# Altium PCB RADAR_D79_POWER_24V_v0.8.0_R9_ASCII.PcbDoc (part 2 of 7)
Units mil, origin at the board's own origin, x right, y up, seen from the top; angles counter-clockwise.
Board outline 3110.24 x 3110.24 mil, 8 copper layers (Top Layer, GND1, SIG1, PWR1, PWR2, SIG2, GND2, Bottom Layer), stack 55.2 mil thick; 304 components, 269 nets, 1408 pads, 1366 vias.

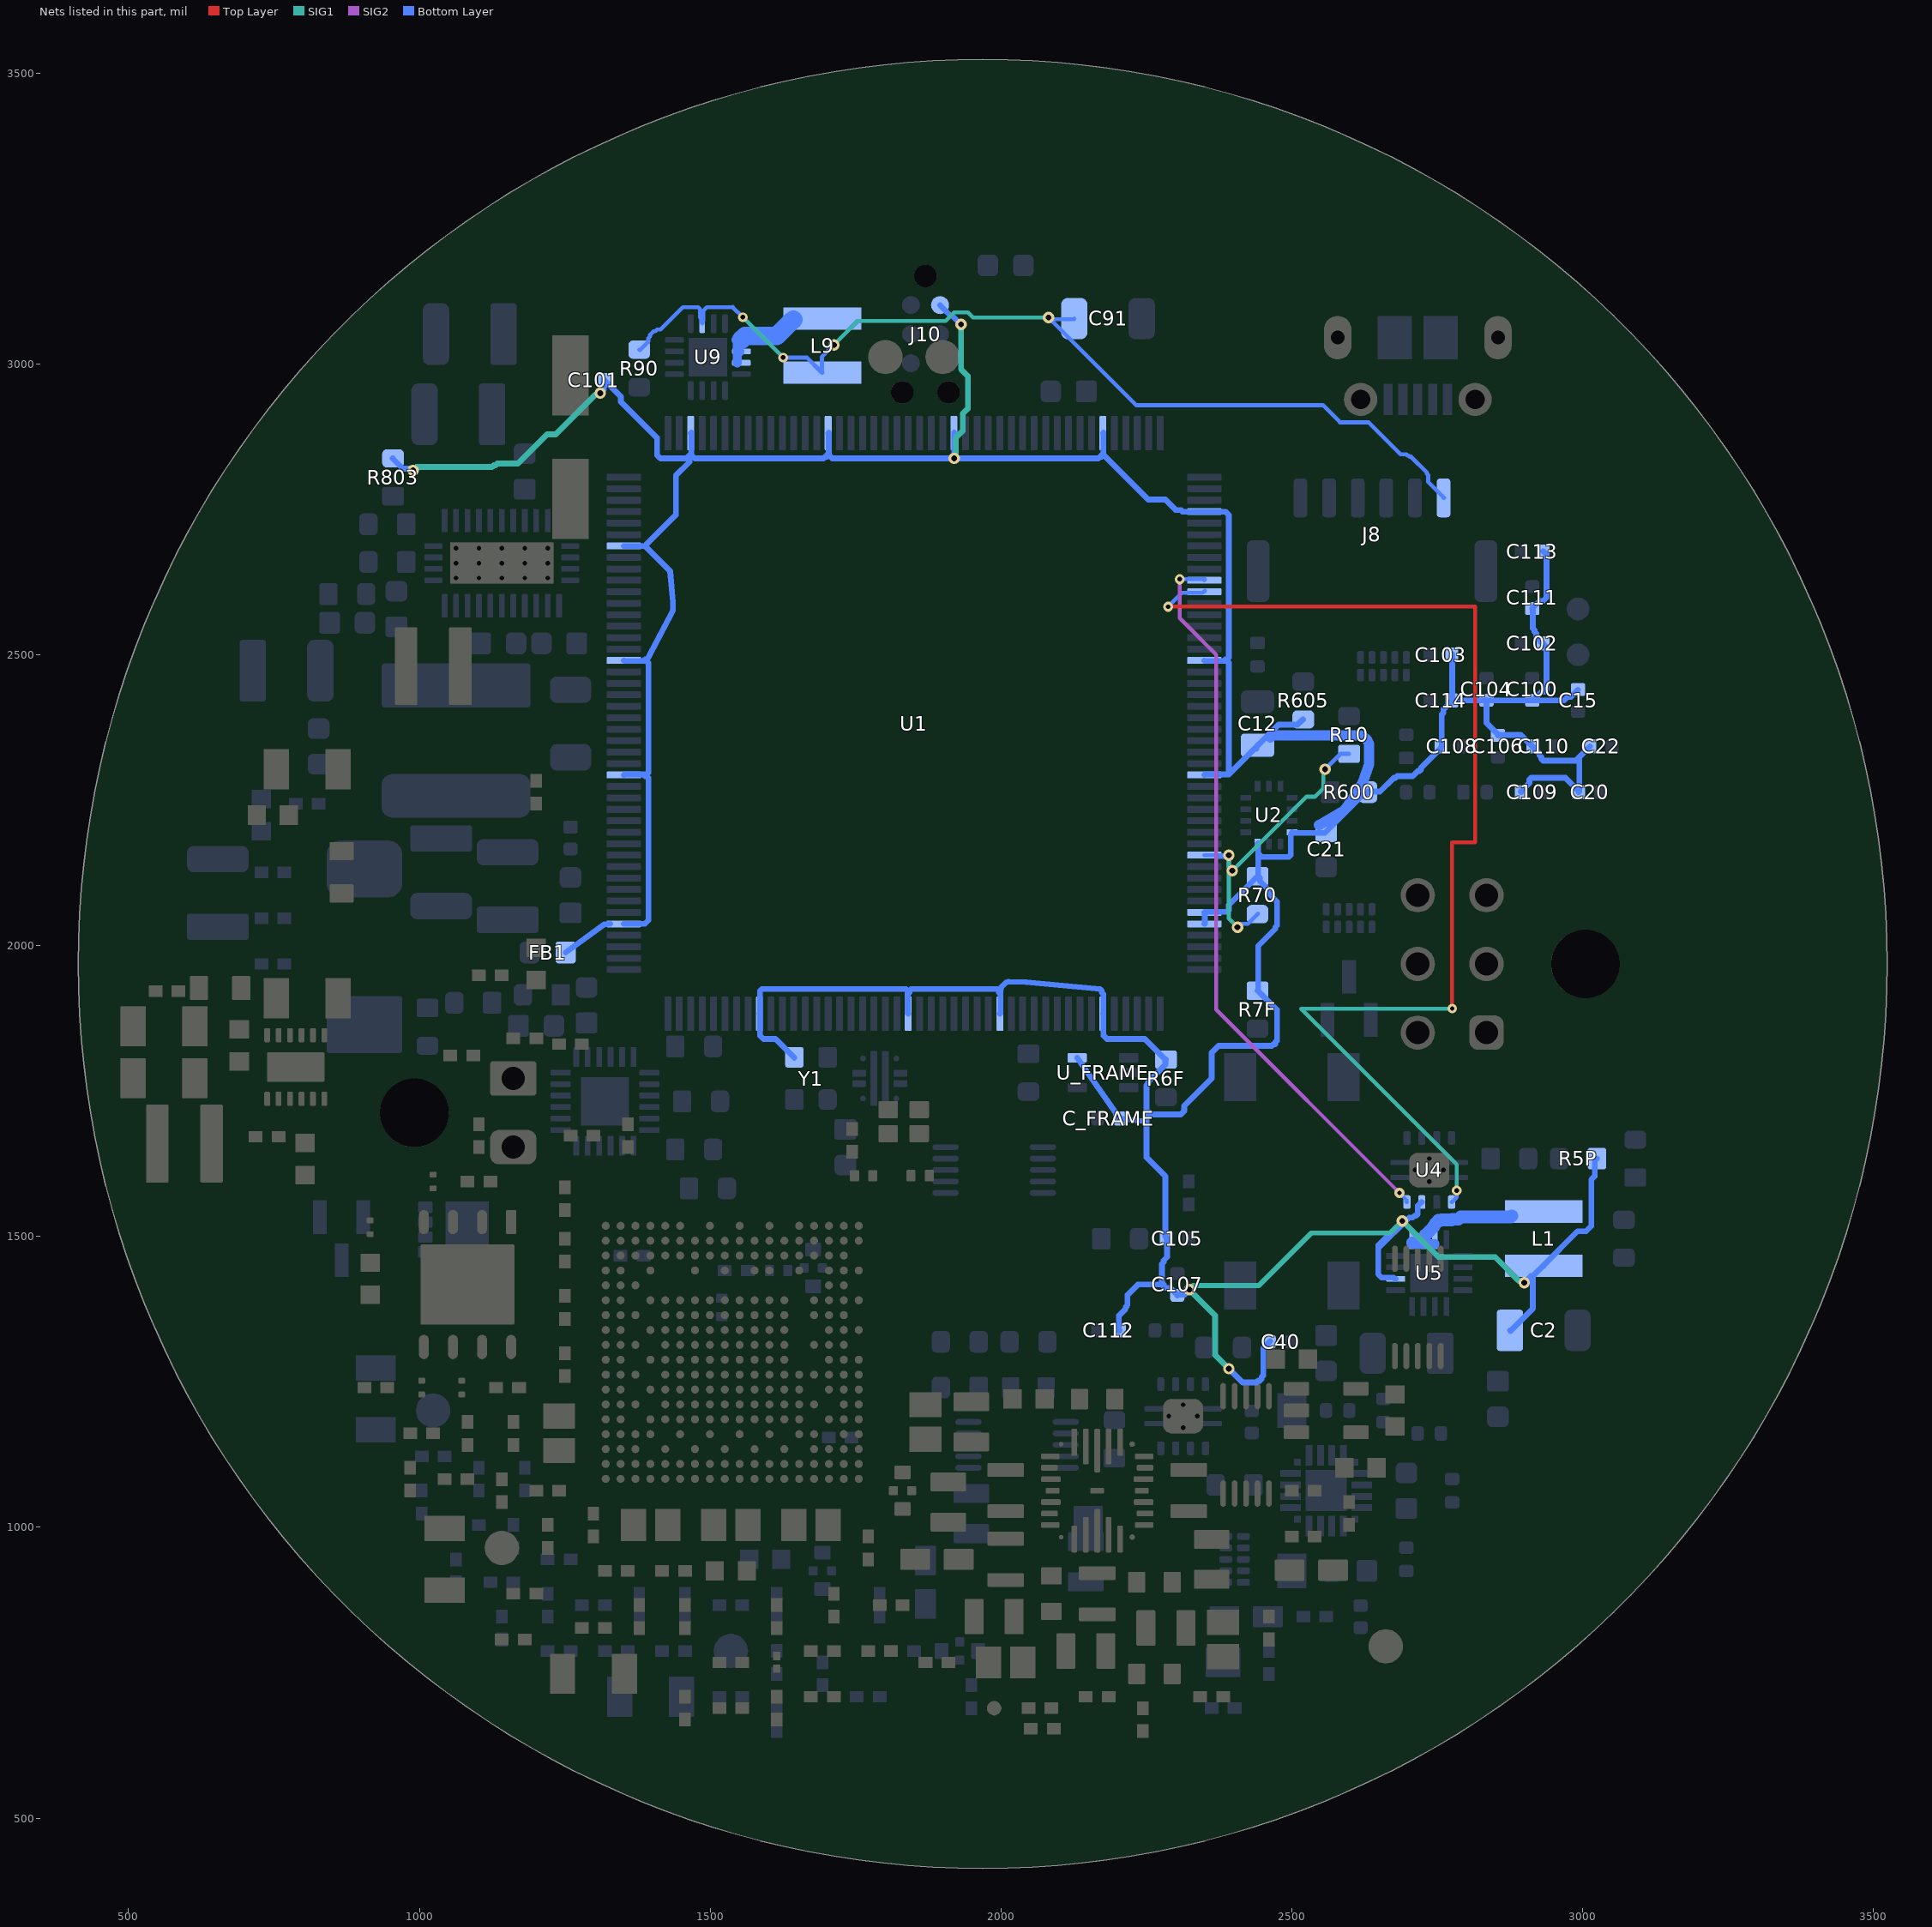
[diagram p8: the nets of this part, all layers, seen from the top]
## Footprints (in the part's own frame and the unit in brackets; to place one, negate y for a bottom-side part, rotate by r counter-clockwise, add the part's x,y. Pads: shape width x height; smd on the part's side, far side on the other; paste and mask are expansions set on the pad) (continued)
RXV0028A-MFG [mm]
  round 0.195 smd paste+0 mask+0: 1(-1.573,2.03) 9(-1.573,-2.03)
  rrect40% 0.8x0.25 smd paste+0 mask+0: 2(-2.05,1.5) 8(-2.05,-1.5) 16(2.05,-1.5) 22(2.05,1.5)
  rrect40% 0.725x0.25 smd paste+0 mask+0: 3(-2.087,1) 7(-2.087,-1) 17(2.087,-1) 21(2.087,1)
  rrect40% 0.85x0.25 smd paste+0 mask+0: 4(-2.025,0.5) 6(-2.025,-0.5) 18(2.025,-0.5) 20(2.025,0.5)
  rrect40% 0.6x0.25 smd paste+0 mask+0: 5(-1.95,0) 5-19(0,0) 19(1.95,0)
  rrect40% 0.25x1.175 smd paste+0 mask+0: 10(-1,-2.113) 14(1,-2.113) 24(1,2.113) 28(-1,2.113)
  rrect40% 0.25x1.55 smd paste-1000 mask+0: 11(-0.5,-1.925) 13(0.5,-1.925) 25(0.5,1.925) 27(-0.5,1.925)
  rrect40% 0.25x1.9 smd paste-1000 mask+0: 12(0,-1.75) 26(0,1.75)
  round 0.243 smd paste+0 mask+0: 15(1.53,-2.03) 23(1.53,2.03)
  silkscreen extent -2.58,-2.78 2.58,2.78
SM_RADIAL_6.3BMM [mm] "Nichicon 6.3x7.7"
  rect 3.5x1.6 smd: 1(-2.7,0) 2(2.7,0)
  silkscreen extent -0.79,-0.88 0.79,0.88
SOT-23 [mm] "JEDEC TO-236 AB, three-pad SOT-23"
  rect 1.475x0.6 smd: 1(-0.937,-0.95) 2(-0.937,0.95) 3(0.937,0)
  silkscreen extent -1.75,-1.33 1.76,1.33
TagConnect_TC2030_NL [mil]
  round 31 smd: 1(-50,-25) 2(-50,25) 3(0,-25) 4(0,25) 5(50,-25) 6(50,25)
  round 39 hole 39: Un1(-100,0) Un2(100,40) Un3(100,-40)
  silkscreen extent -123,-63 123,63
TestPoint_Pad_D1.0mm [mm]
  round 1 smd: 1(0,0)
  silkscreen extent -0.68,-0.68 0.68,0.68
TestPoint_Pad_D1.5mm [mm]
  round 1.5 smd paste-1 mask+0.06: 1(0,0)
  silkscreen extent -0.83,-0.83 0.83,0.83
Texas_DRB0008A [mm]
  rrect50% 0.6x0.31 smd: 1(-1.4,0.975) 2(-1.4,0.325) 3(-1.4,-0.325) 4(-1.4,-0.975) 5(1.4,-0.975) 6(1.4,-0.325) 7(1.4,0.325) 8(1.4,0.975)
  round 0.5 hole 0.2: 9(-0.5,0) 9(0,-0.625) 9(0,0.625) 9(0.5,0)
  rrect50% 0.23x1.025 smd: 9(-0.325,-1.188) 9(-0.325,1.188) 9(0.325,-1.188) 9(0.325,1.188)
  rrect50% 1.5x1.75 smd: 9(0,0)
  rrect50% 1.5x1.75 smd far side: 9(0,0)
  rrect50% 0.23x0.725 on Bottom Paste: Un1(-0.325,1.337) Un2(-0.325,-1.337) Un4(0.325,1.337) Un5(0.325,-1.337)
  rrect50% 1.34x1.55 on Bottom Paste: Un3(0,0)
  silkscreen extent -1.78,-1.78 1.78,1.78
Texas_RGE0024C_VQFN-24-1EP_4x4mm_P0.5mm_EP2.1x2.1mm [mm]
  rrect25% 0.875x0.25 smd mask+0: 1(-1.937,1.25) 2(-1.937,0.75) 3(-1.937,0.25) 4(-1.937,-0.25) 5(-1.937,-0.75) 6(-1.937,-1.25) 13(1.937,-1.25) 14(1.937,-0.75) 15(1.937,-0.25) 16(1.937,0.25) 17(1.937,0.75) 18(1.937,1.25)
  rrect25% 0.25x0.875 smd mask+0: 7(-1.25,-1.937) 8(-0.75,-1.937) 9(-0.25,-1.937) 10(0.25,-1.937) 11(0.75,-1.937) 12(1.25,-1.937) 19(1.25,1.937) 20(0.75,1.937) 21(0.25,1.937) 22(-0.25,1.937) 23(-0.75,1.937) 24(-1.25,1.937)
  rect 2.1x2.1 smd paste-2.1 mask+0: 25(0,0)
  rrect50% 0.85x0.85 on Bottom Paste mask+0: Un1(-0.525,0.525) Un2(-0.525,-0.525) Un3(0.525,0.525) Un4(0.525,-0.525)
  silkscreen extent -2.45,-2.45 2.45,2.45
Texas_RNP0030B_WQFN-30-1EP_4x6mm_P0.5mm_EP1.8x4.5mm_ThermalVias [mm]
  rrect25% 1.025x0.25 smd mask+0: 1(-1.863,2.5) 2(-1.863,2) 3(-1.863,1.5) 4(-1.863,1) 5(-1.863,0.5) 6(-1.863,0) 7(-1.863,-0.5) 8(-1.863,-1) 9(-1.863,-1.5) 10(-1.863,-2) 11(-1.863,-2.5) 16(1.863,-2.5) 17(1.863,-2) 18(1.863,-1.5) 19(1.863,-1) 20(1.863,-0.5) 21(1.863,0) 22(1.863,0.5) 23(1.863,1) 24(1.863,1.5) 25(1.863,2) 26(1.863,2.5)
  rrect25% 0.25x0.775 smd mask+0: 12(-0.75,-2.987) 13(-0.25,-2.987) 14(0.25,-2.987) 15(0.75,-2.987) 27(0.75,2.987) 28(0.25,2.987) 29(-0.25,2.987) 30(-0.75,2.987)
  round 0.5 hole 0.2 paste+0 mask+0: 31(-0.65,-2) 31(-0.65,-1) 31(-0.65,0) 31(-0.65,1) 31(-0.65,2) 31(0,-2) 31(0,-1) 31(0,0) 31(0,1) 31(0,2) 31(0.65,-2) 31(0.65,-1) 31(0.65,0) 31(0.65,1) 31(0.65,2)
  rect 1.8x4.5 smd paste-4.5 mask+0: 31(0,0)
  rect 1.8x4.5 smd far side paste-4.5 mask+0: 31(0,0)
  rrect50% 0.78x0.97 on Bottom Paste mask+0: Un1(-0.45,1.68) Un2(-0.45,0.56) Un3(-0.45,-0.56) Un4(-0.45,-1.68) Un5(0.45,1.68) Un6(0.45,0.56) Un7(0.45,-0.56) Un8(0.45,-1.68)
  silkscreen extent -2.46,-3.45 2.45,3.45
TFM201610ALMA [mm] "TDK"
  rrect17% 0.6x1.6 smd: 1(-0.9,0) 2(0.9,0)
  silkscreen extent -0.49,-0.88 0.49,0.88
TP_25MIL-SMT [mil]
  round 25 smd paste-25 mask+0: 1(0,0)
  silkscreen extent -27,-27 27,27
TPS259470A_RPW0010A_VQFN-HR-10_2x2mm_P0.475mm [mm]
  round 0.25 smd: 1(-0.725,0.875) 4(-0.725,-0.875) 7(0.725,-0.875) 10(0.725,0.875)
  rrect17% 0.6x0.3 smd: 2(-0.9,0.225) 3(-0.9,-0.225) 9(0.9,0.225)
  rrect17% 0.3x2.4 smd: 5(-0.25,0) 6(0.25,0)
  rrect50% 0.6x0.3 smd: 8(0.9,-0.225)
  rrect17% 0.3x1.05 on Bottom Paste: Un1(-0.25,0.675) Un2(-0.25,-0.675) Un3(0.25,0.675) Un4(0.25,-0.675)
  silkscreen extent -1.28,-1.28 1.28,1.28
USON-10_2.5x1.0mm_P0.5mm [mm]
  rrect50% 0.55x0.3 smd: 1(-0.385,1) 2(-0.385,0.5) 3(-0.385,0) 4(-0.385,-0.5) 5(-0.385,-1) 6(0.385,-1) 7(0.385,-0.5) 8(0.385,0) 9(0.385,0.5) 10(0.385,1)
  silkscreen extent -1.33,-1.23 1.33,1.23
VPP_SERVICE_SMT_D1p5_P2p5 [mm]
  round 1.5 smd paste-1 mask+0.06: 1(-1.25,0) 2(1.25,0)
  silkscreen extent -2.08,-0.83 2.08,0.83
VQFN-16-1EP_3x3mm_P0.5mm_EP1.68x1.68mm#1 [mm]
  rrect25% 0.825x0.25 smd: 1(-1.462,0.75) 2(-1.462,0.25) 3(-1.462,-0.25) 4(-1.462,-0.75) 9(1.462,-0.75) 10(1.462,-0.25) 11(1.462,0.25) 12(1.462,0.75)
  rrect25% 0.25x0.825 smd: 5(-0.75,-1.462) 6(-0.25,-1.462) 7(0.25,-1.462) 8(0.75,-1.462) 13(0.75,1.462) 14(0.25,1.462) 15(-0.25,1.462) 16(-0.75,1.462)
  rect 1.68x1.68 smd: 17(0,0)
  rrect25% 0.68x0.68 on Bottom Paste: Un1(-0.42,0.42) Un2(-0.42,-0.42) Un3(0.42,0.42) Un4(0.42,-0.42)
  silkscreen extent -1.95,-1.95 1.95,1.95
VQFN-16-1EP_3x3mm_P0.5mm_EP1.68x1.68mm#2 [mm]
  rrect50% 0.825x0.25 smd: 1(-1.462,0.75) 2(-1.462,0.25) 3(-1.462,-0.25) 4(-1.462,-0.75) 9(1.462,-0.75) 10(1.462,-0.25) 11(1.462,0.25) 12(1.462,0.75)
  rrect50% 0.25x0.825 smd: 5(-0.75,-1.462) 6(-0.25,-1.462) 7(0.25,-1.462) 8(0.75,-1.462) 13(0.75,1.462) 14(0.25,1.462) 15(-0.25,1.462) 16(-0.75,1.462)
  rect 1.68x1.68 smd: 17(0,0)
  rrect50% 0.68x0.68 on Bottom Paste: Un1(-0.42,0.42) Un2(-0.42,-0.42) Un3(0.42,0.42) Un4(0.42,-0.42)
  silkscreen extent -1.95,-1.95 1.95,1.95
VSON-8_3.3x3.3mm_P0.65mm_NexFET [mm]
  rrect25% 0.63x0.495 smd mask+0: 1(-1.44,0.975) 2(-1.44,0.325) 3(-1.44,-0.325) 4(-1.44,-0.975)
  rect 1.9x2.45 smd paste-2.45 mask+0: 5(0.385,0)
  rect 0.57x0.738 on Bottom Paste mask+0: Un1(-0.09,0.61) Un2(-0.09,-0.61) Un3(0.86,0.61) Un4(0.86,-0.61)
  rrect50% 0.63x0.5 on Bottom Paste mask+0: Un5(1.44,0.972) Un6(1.44,0.33) Un7(1.44,-0.33) Un8(1.44,-0.972)
  silkscreen extent -1.84,-1.73 1.83,1.73

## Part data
C1 C2 C3 C4 C6D C6I C7D C10 C11 C12 C13 C14 C15 C20 C21 C22 C40 C90 C91 C92 C93 C100 C101 C102 C103 C104 C105 C106 C107 C108 C109 C110 C111 C112 C113 C114 C115 C800 C801 C802 C803 C804 C805 C806 C807 C808 C809 C_USB_1U C_USB_4U7 C_USB_100N: library part C
D1: library part D_TVS
D3 D8 D_USB: library part TPD4E05U06DQAR
D4: library part ESD2CANFD24DBZRQ1
FB1: library part L_Ferrite
J1: library part Conn_01x02
J6 J8 J10: library part Conn_01x06
JUSB1: library part CMP-0055293-1, "Connector, Receptacle, Micro-USB Type B, R/A, Bottom Mount SMT"
L1 L8 L9: library part L
Q6: library part CSD19537Q3
Q7: library part BSS138
R1 R2 R5P R6F R7F R10 R40 R41 R42 R61 R62 R63 R70 R71 R72 R73 R90 R600 R601 R602 R603 R604 R605 R800 R801 R802 R803 R804 R805 R806 R_USB_CTS R_USB_RESET R_USB_VBUS_H R_USB_VBUS_L R_USB_WAKE: library part R
RAD_C1 RAD_C10 RAD_C60 RAD_C145: library part CMP-0007136-5, "CAP, CERM, 1 uF, 16 V, +/- 10%, X7R, AEC-Q200 Grade 1, 0603"
RAD_C2: library part CMP-0006325-2, "CAP, CERM, 0.1 uF, 50 V, +/- 10%, X7R, AEC-Q200 Grade 1, 0402"
RAD_C3 RAD_C123 RAD_C137 RAD_C146 RAD_C149: library part CMP-0007134-5, "CAP, CERM, 2.2 uF, 6.3 V, +/- 10%, X7R, AEC-Q200 Grade 1, 0603"
RAD_C5 RAD_C21 RAD_C22 RAD_C92 RAD_C96 RAD_C107 RAD_C111 RAD_C113 RAD_C115 RAD_C117 RAD_C138 RAD_C139 RAD_C140 RAD_C141 RAD_C142 RAD_C163 RAD_C164 RAD_C165 RAD_C168 RAD_C170 RAD_C172 RAD_C174 RAD_C175 RAD_C176 RAD_C177 RAD_C199: library part CMP-0078265-1, "CAP, CERM, 0.22 µF, 16 V,+/- 10%, X7R, AEC-Q200 Grade 1, 0402"
RAD_C6 RAD_C8 RAD_C124 RAD_C144 RAD_C153: library part CMP-0091520-1, "Cap Ceramic Multilayer 4.7uF 6.3V DC 10% SMD Paper T/R"
RAD_C9 RAD_C58 RAD_C179 RAD_C181: library part CMP-0088247-2, "3 Terminals Low ESL Chip Multilayer Ceramic Capacitors for Automotive"
RAD_C14 RAD_C17 RAD_C19 RAD_C81: library part CMP-0006350-2, "CAP, CERM, 0.1 uF, 10 V, +/- 10%, X7R, AEC-Q200 Grade 1, 0402"
RAD_C15 RAD_C31 RAD_C110 RAD_C112 RAD_C114 RAD_C116 RAD_C119: library part CMP-0008017-2, "CAP, CERM, 10 uF, 10 V, +/- 10%, X7R, 0805"
RAD_C23 RAD_C25 RAD_C26 RAD_C29: library part CMP-0008811-3, "CAP, CERM, 22 uF, 10 V, +/- 10%, X7R, AEC-Q200 Grade 1, 1206"
RAD_C99: library part CMP-0012608-3, "CAP, Polymer Hybrid, 68 uF, 35 V, +/- 20%, 35 ohm, 6.3x7.7 SMD"
RAD_C100 RAD_C101: library part CMP-0008702-2, "CAP, CERM, 4.7 uF, 50 V, +/- 10%, X7R, 1206"
RAD_C102 RAD_C103: library part CMP-0088425-1, "1µF ±10% 6.3V Ceramic Capacitor X7R 0402 (1005 Metric)"
RAD_C104 RAD_C126: library part CMP-0007104-4, "CAP, CERM, 0.1 uF, 50 V, +/- 10%, X8R, AEC-Q200 Grade 0, 0603"
RAD_C105 RAD_C150 RAD_C200: library part CMP-0006351-2, "CAP, CERM, 0.1 uF, 16 V, +/- 10%, X7R, 0402"
RAD_C106 RAD_C108: library part CMP-0048219-1, "Ceramic Capacitor for Automotive 3.9pF ±0.1pF 50VDC C0G 0402 Paper T/R"
RAD_C118 RAD_C173: library part CMP-0090082-1, "Cap Ceramic 4.7uF 50V X7R 10% Pad SMD 0805 +125°C Automotive T/R"
RAD_C125 RAD_C129 RAD_C130 RAD_C132 RAD_C134 RAD_C143 RAD_C201 RAD_C202: library part CMP-0860846-1, "CAP, CERM, 22 µF, 6.3 V,+/- 20%, X7T, AEC-Q200 Grade 1, 0805"
RAD_C180: library part CMP-0006330-2, "CAP, CERM, 0.047 uF, 50 V, +/- 10%, X7R, AEC-Q200 Grade 1, 0402"
RAD_C195: library part CMP-0007094-5, "CAP, CERM, 0.22 uF, 50 V, +/- 10%, X7R, AEC-Q200 Grade 1, 0603"
RAD_L1: library part CMP-0081093-1, "Inductor, Shielded, Metal Composite, 1.5 µH, 2.3 A, 0.11 ohm, AEC-Q200 Grade 0, SMD"
RAD_L2 RAD_L8 RAD_L9: library part CMP-0091696-1, "240nH Shielded Thin Film Inductor 5A 23mOhm Max 0806 (2016 Metric)"
RAD_L5: library part CMP-0089502-2, "Power Inductor (SMD), 4.7 µH, 5.1 A, Shielded, 4.5 A, XAL40xx Series, 4mm x 4mm x 3.1mm"
RAD_L6: library part CMP-0120010-1, "Ultra-Low Loss Shielded Power Inductors 2.2µH ±20% 7.8A 22.1mOhms"
RAD_NT1: library part CMP-0078142-4, "Single point connection between nets."
RAD_NT2 RAD_NT3 RAD_NT4: library part CMP-0078142-3, "Single point connection between nets."
RAD_R1 RAD_R13 RAD_R14 RAD_R17 RAD_R27 RAD_R29 RAD_R33 RAD_R35 RAD_R37 RAD_R57 RAD_R58 RAD_R59 RAD_R62 RAD_R63 RAD_R71 RAD_R75 RAD_R76 RAD_R128 RAD_R129 RAD_R186 RAD_R190 RAD_R291: library part CMP-0026992-3, "RES, 0, 5%, 0.1 W, AEC-Q200 Grade 0, 0402"
RAD_R2: library part CMP-0026555-2, "RES, 7.50 k, 1%, 0.063 W, AEC-Q200 Grade 0, 0402"
RAD_R7 RAD_R9 RAD_R41 RAD_R43 RAD_R49 RAD_R106 RAD_R125 RAD_R264 RAD_R299 RAD_R301 RAD_R305 RAD_R309 RAD_R310 RAD_R409: library part CMP-0025958-3, "RES, 10.0 k, 1%, 0.063 W, AEC-Q200 Grade 0, 0402"
RAD_R26 RAD_R32 RAD_R47 RAD_R56 RAD_R65 RAD_R66 RAD_R348 RAD_R352: library part CMP-0025964-3, "RES, 10.2, 1%, 0.063 W, AEC-Q200 Grade 0, 0402"
RAD_R30 RAD_R60 RAD_R64 RAD_R346: library part CMP-0017253-2, "RES, 0.001, 1%, 1 W, AEC-Q200 Grade 0, 1206"
RAD_R38: library part CMP-0026395-2, "RES, 47.5 k, 1%, 0.063 W, AEC-Q200 Grade 0, 0402"
RAD_R39 RAD_R40 RAD_R42 RAD_R44 RAD_R45: library part CMP-0089575-2, "Res Thick Film 0201 33.2 Ohm 1% 0.05W(1/20W) ±200ppm/C Pad SMD Automotive T/R"
RAD_R73 RAD_R104 RAD_R111 RAD_R200: library part CMP-0091690-1, "RES 0 OHM JUMPER 1/4W 0603"
RAD_R99: library part CMP-0026071-3, "RES, 1.00 k, 1%, 0.063 W, AEC-Q200 Grade 0, 0402"
RAD_R116: library part CMP-0081856-1, "RES, 0, 0%, 0.2 W, AEC-Q200 Grade 0, 0402"
RAD_R193 RAD_R386: library part CMP-0026299-2, "RES, 33.2, 1%, 0.063 W, AEC-Q200 Grade 0, 0402"
RAD_R218: library part CMP-0027008-4, "RES, 0, 5%, 0.05 W, 0201"
RAD_R276 RAD_R277: library part CMP-0026244-2, "RES, 2.94 k, 1%, 0.063 W, AEC-Q200 Grade 0, 0402"
RAD_R292: library part CMP-0026890-5, "RES, 2.2 k, 5%, 0.063 W, AEC-Q200 Grade 0, 0402"
RAD_R300 RAD_R311: library part CMP-0026557-2, "RES, 7.87 k, 1%, 0.063 W, AEC-Q200 Grade 0, 0402"
RAD_R302 RAD_R307 RAD_R313: library part CMP-0026574-2, "RES, 82.5 k, 1%, 0.063 W, AEC-Q200 Grade 0, 0402"
RAD_TP8: library part CMP-0078143-3, "TEST POINT.  No entry in BOM."
RAD_U1: library part CMP-0091081-1, "3.3V Uniform Sector Dual and Quad Serial Flash SPI 64Mbit 2.7-3.6V WSON8"
RAD_U2: library part CMP-0088353-1, "3.5-V to 36-V, 1.5-A, and 2.5-A Automotive Step-down Voltage Converter"
RAD_U8: library part CMP-0091078-3, "Three Buck Converters and 5-V Boost for AWR and IWR Radar Sensors"
RAD_U9 RAD_U11 RAD_U12 RAD_U22: library part CMP-0037979-1, "High-Side Measurement, Bi-Directional Current / Power Monitor with I2C Interface, 2.7 to 5.5 V, -40 to 125 degC, 10-pin SOP (DGS10), Green (RoHS & no Sb/Br)"
RAD_U27: library part CMP-0092338-1, "Linear Voltage Regulator IC Positive Fixed Output 300mA SOT-23-5"
RAD_U29: library part CMP-0122079-4, "Single-Chip 76- and 81-GHz FMCW Radar Sensor"
RAD_Y3: library part CMP-0001431-1, "50 MHz ±15ppm Crystal 8pF 50 Ohms 4-SMD, No Lead"
SW1: library part SW_Push
TP1 TP2: library part TestPoint
U1: library part STM32H753IITx
U2: library part ICM-42688-P
U4: library part TCAN3404DRBRQ1
U5: library part TPS62132RGTR
U6: library part TPS26630RGER
U7: library part TPS259470ARPWR
U8: library part LM76005RNPR
U9: library part TPS62133RGTR
U_FRAME: library part SN74LVC1G17DCKR
Y1: library part ECS-2520S33-250-FN-TR

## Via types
v1: diameter 13.77, hole 5.9, Top Layer to GND1, tented both sides, 513 vias
v2: diameter 19.68, hole 9.84, Top Layer to Bottom Layer, tented both sides, 196 vias
v3: diameter 16.54, hole 7.87, Top Layer to Bottom Layer, tented both sides, 129 vias
v4: diameter 13.77, hole 5.9, Top Layer to GND1, tented top, 104 vias
v5: diameter 13.78, hole 5.91, Top Layer to GND1, tented both sides, 83 vias
v6: diameter 17.32, hole 7.87, Top Layer to Bottom Layer, tented both sides, 69 vias
v7: diameter 13.78, hole 5.91, GND2 to Bottom Layer, tented both sides, 68 vias
v8: diameter 13.78, hole 5.91, Top Layer to GND1, tented bottom, 55 vias
v9: diameter 13.78, hole 5.91, GND2 to Bottom Layer, tented top, 43 vias
v10: diameter 22.05, hole 11.81, Top Layer to Bottom Layer, tented both sides, 23 vias
v11: diameter 16.54, hole 7.87, GND2 to Bottom Layer, tented both sides, 22 vias
v12: diameter 16.54, hole 7.87, Top Layer to Bottom Layer, 14 vias
v13: diameter 22.83, hole 11.81, Top Layer to Bottom Layer, tented both sides, 11 vias
v14: diameter 18.11, hole 9.06, Top Layer to Bottom Layer, tented both sides, 8 vias
v15: diameter 19.68, hole 7.87, Top Layer to Bottom Layer, 3 vias
v16: diameter 17.32, hole 8.66, Top Layer to Bottom Layer, tented both sides, 3 vias
v17: diameter 20.47, hole 9.84, Top Layer to Bottom Layer, tented both sides, 3 vias
v18: diameter 17.72, hole 9.84, Top Layer to Bottom Layer, tented both sides, 2 vias
v19: diameter 22.05, hole 11.02, Top Layer to Bottom Layer, tented both sides, 2 vias
v20: diameter 19.68, hole 11.81, Top Layer to Bottom Layer, tented both sides, 2 vias
v21: diameter 19.68, hole 9.84, SIG1 to Bottom Layer, tented both sides, 2 vias
v22: diameter 16.54, hole 7.87, SIG1 to SIG2, tented both sides, 2 vias
v23: diameter 16.54, hole 7.87, Top Layer to SIG1, 2 vias
v24: diameter 13.78, hole 5.91, Top Layer to GND1, 2 vias
v25: diameter 18, hole 9.84, Top Layer to Bottom Layer, tented both sides, 1 vias
v26: diameter 19.68, hole 9.84, GND2 to Bottom Layer, tented both sides, 1 vias
v27: diameter 17.32, hole 7.87, SIG1 to Bottom Layer, tented both sides, 1 vias
v28: diameter 19.68, hole 9.84, SIG2 to Bottom Layer, tented both sides, 1 vias
v29: diameter 16.54, hole 7.87, PWR2 to GND1, tented both sides, 1 vias

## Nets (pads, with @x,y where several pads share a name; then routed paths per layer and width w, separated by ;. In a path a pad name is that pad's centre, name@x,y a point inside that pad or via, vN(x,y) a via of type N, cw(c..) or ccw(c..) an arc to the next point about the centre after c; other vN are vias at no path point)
3V3: C2.1 C12.1 C15.1 C20.1 C21.1 C22.1 C40.1 C100.1 C101.1 C102.1 C103.1 C104.1 C105.1 C106.1 C107.1 C108.1 C109.1 C110.1 C111.1 C112.1 C113.1 C114.1 C_FRAME.1 FB1.1 J10.1 L1.2 R5P.2 R6F.2 R7F.2 R70.2 R600.1 R605.1 R803.2 U1.6 U1.15 U1.23 U1.36 U1.49 U1.62 U1.72 U1.82 U1.91 U1.103 U1.114 U1.127 U1.136 U1.149 U1.159 U1.171 U1.172 U2.5 U2.8 U4.3 U5.14 U_FRAME.5 Y1.4 | length 10676.6
  SIG1 w8.66: v2(2323.82,1408.46) 2324.8,1409.45 2330.71,1415.35 2442.91,1415.35 2533.46,1505.91 2669.29,1505.91 2690.94,1527.56 v2(2689.96,1526.57)
  SIG1 w9.84: v2(989.17,2816.93) 995.08,2822.83 1125,2822.83 1127.95,2825.79 1130.91,2825.79 1133.86,2828.74 1169.29,2828.74 1219.49,2878.94 1234.25,2878.94 1302.17,2946.85 1308.07,2946.85 v2(1311.02,2949.8) ; v2(1919.29,2837.6) 1922.24,2840.55 1922.24,2873.03 1934.06,2884.84 1934.06,2914.37 1942.91,2923.23 1942.91,2979.33 1931.1,2991.14 v2(1931.1,3067.91) ; v2(2323.82,1408.46) 2368.11,1364.17 2368.11,1296.26 v2(2391.73,1272.64) ; v2(2689.96,1526.57) 2751.97,1464.57 2849.41,1464.57 2890.75,1423.23 2896.65,1423.23 v2(2899.61,1420.28)
  Bottom Layer w9.84: R803.2@954.72,2837.6 953.74,2837.6 971.46,2819.88 986.22,2819.88 v2(989.17,2816.93) ; FB1.1@1251.48,1988.19 1317.91,2036.42 U1.49@1328.15,2037.4 ; v2(1311.02,2949.8) 1316.93,2955.71 C101.1@1316.93,2973.43 ; C101.1@1318.11,2972.44 C101.1@1316.93,2973.43 ; U1.49@1351.38,2037.4 1352.36,2037.4 1387.8,2037.4 1393.7,2043.31 1393.7,2288.39 1390.75,2291.34 1387.8,2291.34 1384.84,2294.29 U1.62@1352.36,2294.29 ; U1.62@1351.38,2293.31 U1.62@1352.36,2294.29 ; U1.72@1351.38,2490.16 U1.72@1352.36,2489.17 ; U1.82@1351.38,2687.01 1352.36,2687.01 1387.8,2687.01 ; U1.91@1466.54,2880.91 U1.91@1467.52,2881.89 ; U1.36@1584.65,1882.87 U1.36@1585.63,1883.86 ; Y1.4@1644.68,1808.07 1644.68,1807.09 1612.2,1839.57 1591.54,1839.57 1585.63,1845.47 U1.36@1585.63,1883.86 ; U1.103@1702.76,2880.91 U1.103@1703.74,2881.89 ; U1.23@1840.55,1882.87 U1.23@1839.57,1883.86 ; J10.1@1895.08,3101.18 1895.67,3100.39 1913.39,3082.68 1916.34,3082.68 v2(1931.1,3067.91) ; v2(1919.29,2837.6) U1.114@1919.29,2881.89 ; U1.114@1919.29,2880.91 U1.114@1919.29,2881.89 ; U1.15@1998.03,1882.87 U1.15@1999.02,1883.86 ; U_FRAME.5@2130.91,1807.09 C_FRAME.1@2203.94,1702.76 2250,1697.83 ; U1.6@2175.2,1882.87 U1.6@2176.18,1883.86 ; U1.127@2175.2,2880.91 U1.127@2176.18,2881.89 ; C112.1@2203.94,1338.58 2202.76,1337.6 2202.76,1364.17 2214.57,1375.98 2214.57,1378.94 2217.52,1381.89 2217.52,1399.61 2235.24,1417.32 2276.57,1417.32 2282.48,1411.42 ; R6F.2@2283.46,1804.13 R6F.2@2282.48,1804.13 ; C105.1@2284.25,1496.06 C105.1@2285.43,1497.05 ; C107.1@2303.15,1398.42 C107.1@2303.15,1399.61 ; v2(2323.82,1408.46) 2314.96,1399.61 C107.1@2303.15,1399.61 ; U1.172@2349.41,2037.4 2350.39,2037.4 U1.171@2350.39,2058.07 ; U1.171@2349.41,2057.09 U1.171@2350.39,2058.07 ; U1.159@2349.41,2293.31 U1.159@2350.39,2294.29 ; U1.149@2349.41,2490.16 U1.149@2350.39,2489.17 ; U1.136@2349.41,2746.06 U1.136@2350.39,2746.06 ; v2(2391.73,1272.64) 2415.35,1249.02 2438.98,1249.02 2441.93,1251.97 2444.88,1251.97 2447.83,1254.92 2447.83,1257.87 2450.79,1260.83 2450.79,1308.07 2462.6,1319.88 C40.1@2461.42,1318.9 ; C12.1@2438.98,2338.58 2438.98,2341.54 C12.1@2441.93,2344.49 ; R7F.2@2440.94,1922.24 R7F.2@2441.93,1922.24 ; R70.2@2440.94,2119.09 R70.2@2441.93,2120.08 ; U2.5@2440.94,2174.7 U2.5@2441.93,2176.18 ; C12.1@2440.94,2344.49 C12.1@2441.93,2344.49 ; U2.8@2500.49,2194.88 U2.8@2500.98,2193.9 ; R605.1@2519.68,2388.78 2518.7,2388.78 2509.84,2379.92 2477.36,2379.92 C12.1@2441.93,2344.49 ; C21.1@2559.06,2195.87 C21.1@2560.04,2196.85 ; R600.1@2630.91,2263.78 R600.1@2630.91,2264.76 ; U5.14@2678.64,1427.17 2678.15,1426.18 2675.2,1429.13 2654.53,1429.13 2648.62,1435.04 ; v2(2689.96,1526.57) 2648.62,1485.24 2648.62,1435.04 ; U4.3@2723.43,1559.06 2722.44,1559.06 2716.54,1553.15 2716.54,1538.39 2713.58,1535.43 2710.63,1535.43 2707.68,1532.48 2701.77,1532.48 2648.62,1479.33 2648.62,1435.04 ; C108.1@2756.69,2342.52 C108.1@2757.87,2341.54 ; C114.1@2774.8,2421.26 C114.1@2775.59,2421.26 ; C103.1@2774.8,2500 2775.59,2500.98 C114.1@2775.59,2421.26 ; C104.1@2834.65,2422.05 C104.1@2834.65,2421.26 ; C106.1@2854.33,2361.42 C106.1@2855.32,2362.2 ; C2.1@2875,1338.58 2875.98,1337.6 2914.37,1375.98 L1.2@2914.37,1432.09 ; C109.1@2894.49,2263.78 2893.7,2264.76 2908.46,2279.53 2908.46,2285.43 2911.42,2288.39 2970.47,2288.39 C20.1@2994.09,2264.76 ; v2(2899.61,1420.28) 2911.42,1432.09 L1.2@2914.37,1432.09 ; C100.1@2913.39,2422.05 C100.1@2914.37,2421.26 ; C111.1@2913.39,2579.53 C111.1@2914.37,2580.71 ; C110.1@2914.17,2342.52 C110.1@2914.37,2341.54 ; C102.1@2932.28,2519.68 C102.1@2932.09,2518.7 ; C113.1@2932.28,2677.17 2932.09,2678.15 2937.99,2672.24 2937.99,2598.43 2932.09,2592.52 2926.18,2592.52 C111.1@2914.37,2580.71 ; L1.2@2933.07,1449.41 L1.2@2932.09,1449.8 ; C15.1@2992.13,2440.16 2991.14,2438.98 2979.33,2427.17 2973.43,2427.17 2967.52,2421.26 C100.1@2914.37,2421.26 ; C20.1@2992.91,2263.78 C20.1@2994.09,2264.76 ; C22.1@3012.6,2342.52 C22.1@3011.81,2341.54 ; R5P.2@3024.61,1633.86 3023.62,1632.87 3020.67,1629.92 3020.67,1603.35 3014.76,1597.44 3014.76,1517.72 3005.91,1508.86 2991.14,1508.86 L1.2@2932.09,1449.8 ; C101.1@1316.93,2973.43 1346.46,2943.9 1346.46,2935.04 1408.46,2873.03 1408.46,2843.5 1414.37,2837.6 1458.66,2837.6 1461.61,2840.55 1464.57,2840.55 1464.57,2843.5 ; U1.62@1352.36,2294.29 1390.75,2294.29 1393.7,2297.24 1393.7,2486.22 1390.75,2489.17 U1.72@1352.36,2489.17 ; U1.72@1352.36,2489.17 1384.84,2489.17 1387.8,2492.13 1390.75,2492.13 1393.7,2495.08 1436.02,2576.77 1436.02,2590.55 1431.1,2643.7 1393.7,2681.1 1387.8,2687.01 ; 1387.8,2687.01 1440.94,2740.16 1440.94,2808.07 1464.57,2831.69 1464.57,2843.5 ; 1464.57,2843.5 1467.52,2846.46 U1.91@1467.52,2881.89 ; U1.91@1467.52,2881.89 1467.52,2843.5 1473.43,2837.6 1694.88,2837.6 1697.83,2840.55 1700.79,2840.55 1700.79,2843.5 1703.74,2846.46 U1.103@1703.74,2881.89 ; U1.36@1585.63,1883.86 1585.63,1922.24 1588.58,1925.2 1836.61,1925.2 1839.57,1922.24 U1.23@1839.57,1883.86 ; U1.103@1703.74,2881.89 1703.74,2843.5 1709.65,2837.6 1913.39,2837.6 v2@1919.29,2843.5 ; U1.23@1839.57,1883.86 1839.57,1916.34 1842.52,1919.29 1842.52,1922.24 1845.47,1925.2 1993.11,1925.2 1996.06,1922.24 1996.06,1919.29 1999.02,1916.34 U1.15@1999.02,1883.86 ; v2@1919.29,2843.5 U1.114@1919.29,2881.89 ; v2@1919.29,2843.5 1925.2,2837.6 2167.32,2837.6 2170.28,2840.55 2173.23,2840.55 2173.23,2843.5 2176.18,2846.46 U1.127@2176.18,2881.89 ; U1.15@1999.02,1883.86 1999.02,1922.24 2000.98,1929.13 2007.87,1936.02 2012.8,1937.99 2043.31,1937.01 2170.28,1925.2 2173.23,1922.24 2173.23,1919.29 2176.18,1916.34 U1.6@2176.18,1883.86 ; U1.6@2176.18,1883.86 2176.18,1845.47 2182.09,1839.57 2247.05,1839.57 R6F.2@2282.48,1804.13 ; U1.127@2176.18,2881.89 2176.18,2843.5 2252.95,2766.73 2282.48,2766.73 2300.2,2749.02 2309.06,2749.02 2312.01,2746.06 U1.136@2350.39,2746.06 ; 2250,1759.84 2252.95,1762.8 2252.95,1765.75 2282.48,1795.28 R6F.2@2282.48,1804.13 ; 2250,1759.84 2250,1715.55 2252.95,1712.6 2255.91,1712.6 2258.86,1709.65 2309.06,1709.65 2314.96,1715.55 2314.96,1724.41 2362.2,1771.65 2362.2,1815.94 2374.02,1827.76 2465.55,1827.76 2468.5,1830.71 2471.46,1830.71 2471.46,1833.66 2474.41,1836.61 2474.41,1889.76 R7F.2@2441.93,1922.24 ; 2250,1759.84 2250,1635.83 2282.48,1603.35 2282.48,1500 C105.1@2285.43,1497.05 ; 2282.48,1411.42 2291.34,1411.42 C107.1@2303.15,1399.61 ; 2282.48,1411.42 2279.53,1414.37 2279.53,1417.32 2276.57,1420.28 2276.57,1452.76 2279.53,1455.71 2279.53,1458.66 2285.43,1464.57 C105.1@2285.43,1497.05 ; U1.171@2350.39,2058.07 2388.78,2058.07 2391.73,2061.02 2391.73,2069.88 R70.2@2441.93,2120.08 ; U1.159@2350.39,2294.29 2391.73,2294.29 C12.1@2441.93,2344.49 ; U1.159@2350.39,2294.29 2388.78,2294.29 2391.73,2297.24 2391.73,2486.22 2388.78,2489.17 U1.149@2350.39,2489.17 ; U1.149@2350.39,2489.17 2382.87,2489.17 2385.83,2492.13 2388.78,2492.13 2391.73,2495.08 2391.73,2740.16 2385.83,2746.06 U1.136@2350.39,2746.06 ; R7F.2@2441.93,1922.24 2441.93,1999.02 2471.46,2028.54 2471.46,2031.5 2474.41,2034.45 2474.41,2075.79 2462.6,2087.6 2462.6,2093.5 2444.88,2111.22 2444.88,2117.13 R70.2@2441.93,2120.08 ; R70.2@2441.93,2120.08 U2.5@2441.93,2176.18 ; U2.5@2441.93,2176.18 2441.93,2158.46 2447.83,2152.56 2495.08,2152.56 2498.03,2155.51 2498.03,2190.94 U2.8@2500.98,2193.9 ; U2.8@2500.98,2193.9 2557.09,2193.9 C21.1@2560.04,2196.85 ; C21.1@2560.04,2196.85 2622.05,2258.86 2625,2258.86 R600.1@2630.91,2264.76 ; R600.1@2630.91,2264.76 2651.57,2264.76 2675.2,2288.39 2678.15,2288.39 2681.1,2291.34 2707.68,2291.34 2716.54,2300.2 2719.49,2300.2 2722.44,2303.15 2722.44,2306.1 C108.1@2757.87,2341.54 ; C108.1@2757.87,2341.54 2757.87,2397.64 2760.83,2400.59 2760.83,2406.5 C114.1@2775.59,2421.26 ; C114.1@2775.59,2421.26 C104.1@2834.65,2421.26 ; C104.1@2834.65,2421.26 2834.65,2382.87 C106.1@2855.32,2362.2 ; C104.1@2834.65,2421.26 C100.1@2914.37,2421.26 ; C106.1@2855.32,2362.2 2893.7,2362.2 C110.1@2914.37,2341.54 ; L1.2@2914.37,1432.09 L1.2@2932.09,1449.8 ; C110.1@2914.37,2341.54 2926.18,2329.72 2926.18,2326.77 2929.13,2323.82 2929.13,2320.87 2932.09,2317.91 2988.19,2317.91 C22.1@3011.81,2341.54 ; C100.1@2914.37,2421.26 2929.13,2436.02 2935.04,2436.02 2937.99,2438.98 2937.99,2512.8 C102.1@2932.09,2518.7 ; C111.1@2914.37,2580.71 2914.37,2545.28 2917.32,2542.32 2917.32,2539.37 2920.28,2536.42 2920.28,2530.51 C102.1@2932.09,2518.7 ; C20.1@2994.09,2264.76 2994.09,2323.82 C22.1@3011.81,2341.54
  Bottom Layer w17.72: C12.1@2463.19,2357.87 2466.54,2361.22 2618.11,2361.22 2621.06,2360.24 2629.92,2353.35 2632.87,2346.46 2632.87,2312.99 2623.03,2282.48 2596.46,2241.14 2589.57,2232.28 C21.1@2546.65,2207.28
5V_GNSS: C91.1 J8.1 L9.2 R90.2 U9.14 | length 1760.2
  SIG1 w7.09: v3(1555.91,3080.32) v3(1625.2,3011.02) ; v2(1712.6,3032.48) 1753.94,3073.82 1904.53,3073.82 1919.29,3088.58 1942.91,3088.58 1951.77,3079.72 v2(2081.69,3079.72)
  Bottom Layer w7.09: R90.2@1377.95,3024.61 1378.94,3023.62 1393.7,3038.39 1393.7,3044.29 1396.65,3047.24 1396.65,3050.2 1402.56,3056.1 1405.51,3056.1 1408.46,3059.06 1414.37,3059.06 1452.76,3097.44 1479.33,3097.44 1482.28,3094.49 1482.28,3079.72 1485.24,3076.77 U9.14@1485.24,3070.87 ; U9.14@1486.22,3069.39 U9.14@1485.24,3070.87 ; v3(1555.91,3080.32) 1538.58,3097.64 1538.39,3097.44 1494.09,3097.44 1488.19,3091.54 1488.19,3073.82 U9.14@1485.24,3070.87 ; v3(1625.2,3011.02) 1666.14,3011.02 1691.34,2985.83 L9.2@1691.93,2985.24 ; L9.2@1692.91,2984.84 L9.2@1691.93,2985.24 ; v2(1712.6,3032.48) 1691.93,3011.81 L9.2@1691.93,2985.24 ; C91.1@2125.79,3077.95 2125.98,3076.77 2084.65,3076.77 v2(2081.69,3079.72) 2082.68,3078.74 2232.28,2929.13 2553.15,2929.13 2582.68,2899.61 2631.89,2899.61 2687.01,2844.49 2696.85,2844.49 2698.82,2842.52 2700.79,2842.52 2702.76,2840.55 2704.72,2840.55 2732.28,2812.99 2732.28,2811.02 2734.25,2809.06 2734.25,2797.24 2761.81,2769.68 J8.1@2760.83,2769.68
BOOT0: R10.1 R70.1 U1.166 | length 587.2
  SIG1 w7.09: v2(2391.73,2155.51) 2391.73,2046.26 v2(2406.5,2031.5) ; v2(2397.64,2128.94) 2524.61,2255.91 2539.37,2255.91 2554.13,2270.67 2554.13,2300.2 v21(2557.09,2303.15)
  Bottom Layer w7.09: U1.166@2349.41,2155.51 U1.166@2350.39,2155.51 ; v2(2391.73,2155.51) U1.166@2350.39,2155.51 ; v2(2397.64,2128.94) 2391.73,2134.84 2391.73,2146.65 2388.78,2149.61 2388.78,2152.56 2374.02,2152.56 2371.06,2155.51 U1.166@2350.39,2155.51 ; v2(2406.5,2031.5) 2412.4,2037.4 2424.21,2037.4 2441.93,2055.12 R70.1@2440.94,2054.13 ; v21(2557.09,2303.15) 2583.66,2329.72 R10.1@2598.43,2329.72
BUCK5_SW: L9.1 U9.1 U9.2 U9.3 | length 145.7
  Bottom Layer w15.75: U9.3@1546.65,3001.97 1546.26,3001.97 1546.26,3021.65 U9.2@1546.65,3021.65
  Bottom Layer w19.68: U9.2@1548.62,3021.65 1548.23,3021.65 1548.23,3041.34 U9.1@1548.62,3041.34
  Bottom Layer w31.5: U9.1@1553.64,3041.34 1553.15,3041.34 1560.04,3048.23 1614.17,3048.23 1640.75,3074.8 1641.73,3074.8 1642.72,3075.79 L9.1@1643.11,3075.98
BUCK_SW: L1.1 U5.1 U5.2 U5.3 | length 210.2
  Bottom Layer w15.75: U5.2@2726.38,1487.6 2726.38,1487.2 2746.06,1487.2 U5.3@2746.06,1487.6
  Bottom Layer w19.68: U5.1@2706.69,1489.57 2706.69,1489.17 2726.38,1489.17 U5.2@2726.38,1489.57
  Bottom Layer w21.65: U5.2@2726.38,1498.62 2726.38,1499.02 2744.09,1516.73 2744.09,1517.72 2745.08,1518.7 2745.08,1519.68 2747.05,1521.65 2747.05,1522.64 2751.97,1527.56 2755.91,1527.56 2756.89,1528.54 2774.61,1528.54 2775.59,1529.53 2786.42,1529.53 2790.35,1533.46 2875.98,1533.46 2877.95,1535.43 L1.1@2878.35,1535.63
CAN_RX: U1.142 U4.4 | length 1278.8
  SIG2 w6.69: v6(2307.09,2629.92) 2307.09,2562.99 2370.08,2500 2370.08,1889.76 v6(2685.04,1574.8)
  Bottom Layer w6.69: v6(2307.09,2629.92) 2350.39,2629.92 U1.142@2349.41,2627.95 ; v6(2685.04,1574.8) 2696.85,1562.99 2696.85,1559.06 U4.4@2697.83,1559.06
CAN_TX: U1.143 U4.1 | length 2042.1
  Top Layer w6.69: v6(2287.4,2582.68) 2814.96,2582.68 2814.96,2177.17 2775.59,2177.17 v23(2775.59,1891.73)
  SIG1 w6.69: v23(2775.59,1891.73) 2515.75,1891.73 2783.46,1624.02 v6(2783.46,1578.74)
  Bottom Layer w6.69: v6(2287.4,2582.68) 2311.02,2606.3 2346.46,2606.3 2350.39,2610.24 U1.143@2349.41,2608.27 ; U4.1@2774.61,1559.06 2775.59,1559.06 2783.46,1566.93 v6(2783.46,1578.74)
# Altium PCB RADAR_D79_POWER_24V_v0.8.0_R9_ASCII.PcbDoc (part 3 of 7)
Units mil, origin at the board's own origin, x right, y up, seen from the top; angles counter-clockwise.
Board outline 3110.24 x 3110.24 mil, 8 copper layers (Top Layer, GND1, SIG1, PWR1, PWR2, SIG2, GND2, Bottom Layer), stack 55.2 mil thick; 304 components, 269 nets, 1408 pads, 1366 vias.

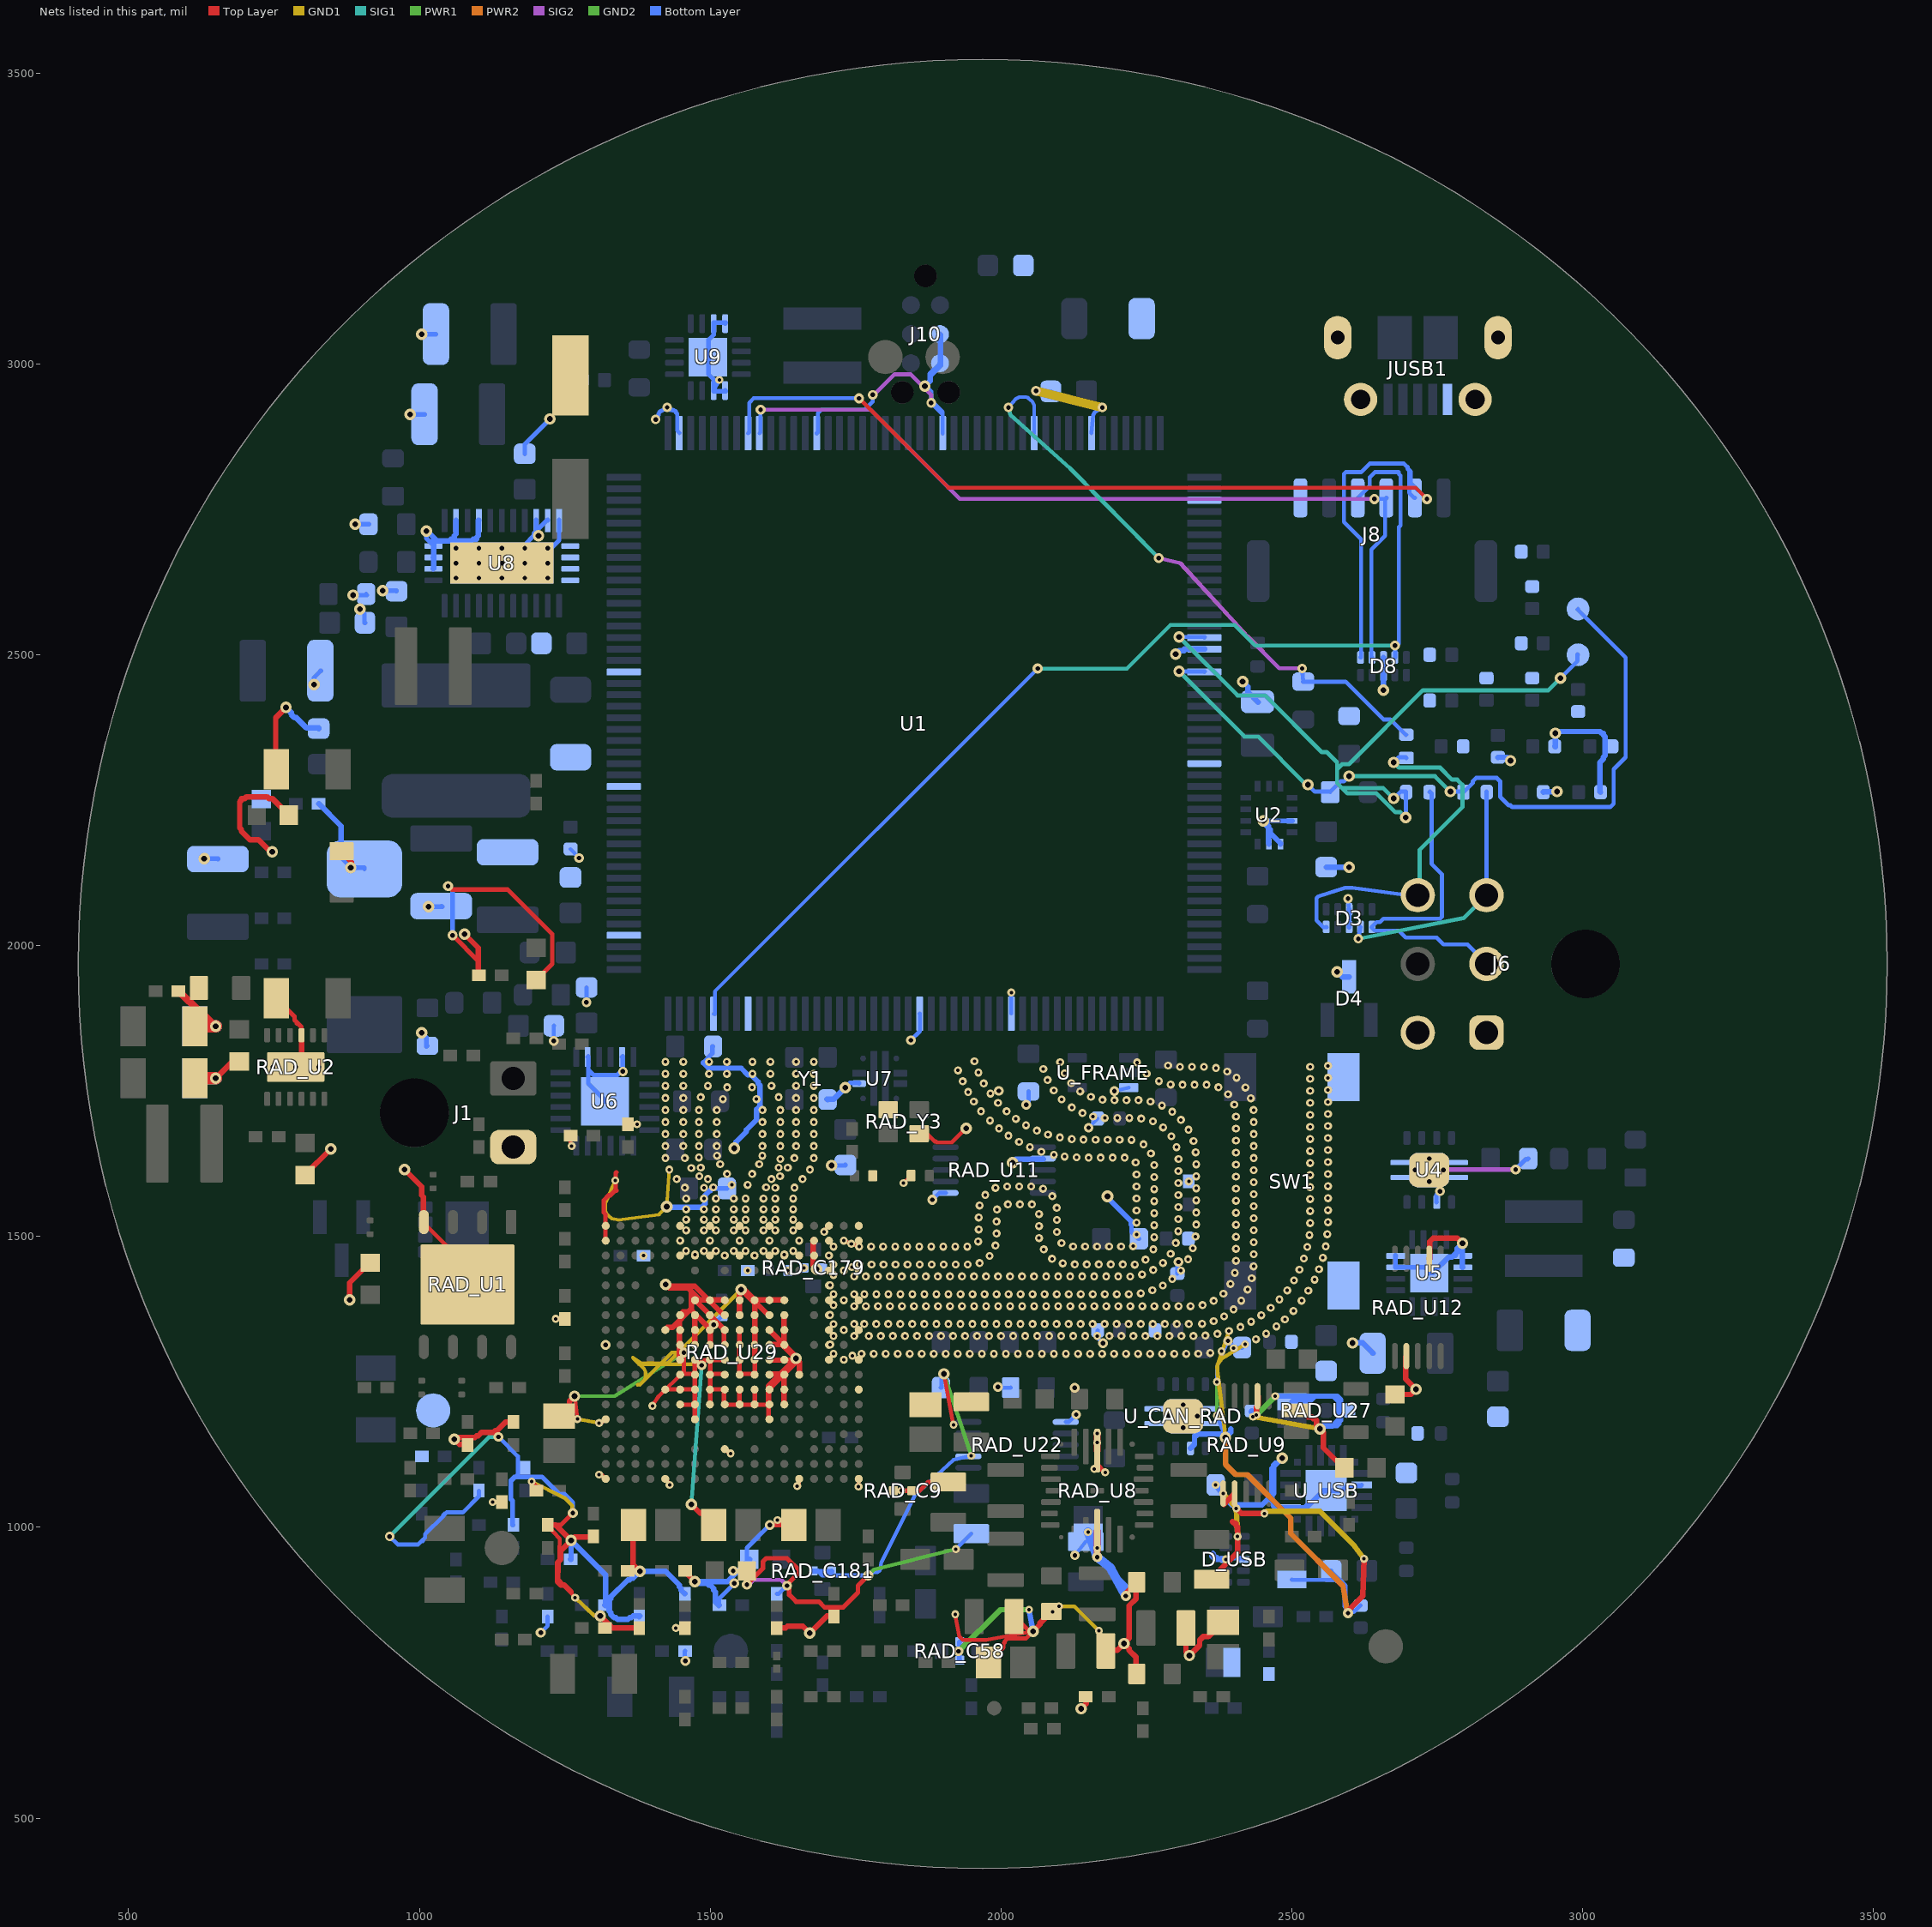
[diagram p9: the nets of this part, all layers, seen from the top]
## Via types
v1: diameter 13.77, hole 5.9, Top Layer to GND1, tented both sides, 513 vias
v2: diameter 19.68, hole 9.84, Top Layer to Bottom Layer, tented both sides, 196 vias
v3: diameter 16.54, hole 7.87, Top Layer to Bottom Layer, tented both sides, 129 vias
v4: diameter 13.77, hole 5.9, Top Layer to GND1, tented top, 104 vias
v5: diameter 13.78, hole 5.91, Top Layer to GND1, tented both sides, 83 vias
v6: diameter 17.32, hole 7.87, Top Layer to Bottom Layer, tented both sides, 69 vias
v7: diameter 13.78, hole 5.91, GND2 to Bottom Layer, tented both sides, 68 vias
v8: diameter 13.78, hole 5.91, Top Layer to GND1, tented bottom, 55 vias
v9: diameter 13.78, hole 5.91, GND2 to Bottom Layer, tented top, 43 vias
v10: diameter 22.05, hole 11.81, Top Layer to Bottom Layer, tented both sides, 23 vias
v11: diameter 16.54, hole 7.87, GND2 to Bottom Layer, tented both sides, 22 vias
v12: diameter 16.54, hole 7.87, Top Layer to Bottom Layer, 14 vias
v13: diameter 22.83, hole 11.81, Top Layer to Bottom Layer, tented both sides, 11 vias
v14: diameter 18.11, hole 9.06, Top Layer to Bottom Layer, tented both sides, 8 vias
v15: diameter 19.68, hole 7.87, Top Layer to Bottom Layer, 3 vias
v16: diameter 17.32, hole 8.66, Top Layer to Bottom Layer, tented both sides, 3 vias
v17: diameter 20.47, hole 9.84, Top Layer to Bottom Layer, tented both sides, 3 vias
v18: diameter 17.72, hole 9.84, Top Layer to Bottom Layer, tented both sides, 2 vias
v19: diameter 22.05, hole 11.02, Top Layer to Bottom Layer, tented both sides, 2 vias
v20: diameter 19.68, hole 11.81, Top Layer to Bottom Layer, tented both sides, 2 vias
v21: diameter 19.68, hole 9.84, SIG1 to Bottom Layer, tented both sides, 2 vias
v22: diameter 16.54, hole 7.87, SIG1 to SIG2, tented both sides, 2 vias
v23: diameter 16.54, hole 7.87, Top Layer to SIG1, 2 vias
v24: diameter 13.78, hole 5.91, Top Layer to GND1, 2 vias
v25: diameter 18, hole 9.84, Top Layer to Bottom Layer, tented both sides, 1 vias
v26: diameter 19.68, hole 9.84, GND2 to Bottom Layer, tented both sides, 1 vias
v27: diameter 17.32, hole 7.87, SIG1 to Bottom Layer, tented both sides, 1 vias
v28: diameter 19.68, hole 9.84, SIG2 to Bottom Layer, tented both sides, 1 vias
v29: diameter 16.54, hole 7.87, PWR2 to GND1, tented both sides, 1 vias

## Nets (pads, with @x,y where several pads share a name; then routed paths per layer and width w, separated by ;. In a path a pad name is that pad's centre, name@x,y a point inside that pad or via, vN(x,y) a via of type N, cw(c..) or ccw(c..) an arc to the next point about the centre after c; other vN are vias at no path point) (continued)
GND: C1.2 C2.2 C3.2 C4.2 C6D.2 C6I.2 C7D.2 C10.2 C11.2 C12.2 C13.2 C14.2 C15.2 C20.2 C21.2 C22.2 C40.2 C90.2 C91.2 C92.2 C93.2 C100.2 C101.2 C102.2 C103.2 C104.2 C105.2 C106.2 C107.2 C108.2 C109.2 C110.2 C111.2 C112.2 C113.2 C114.2 C115.2 C800.2 C801.2 C802.2 C803.2 C804.2 C806.2 C807.2 C808.2 C809.2 C_CAN_RAD.2 C_FRAME.2 C_USB_1U.2 C_USB_4U7.2 C_USB_100N.2 D1.2 D3.3 D3.8 D4.3 D8.3 D8.8 D_USB.3 D_USB.8 J1.2 J6.1 J6.4 J8.6 J10.3 J10.5 JUSB1.5 JUSB1.6 JUSB1.9 JUSB1.10 JUSB1.11 R1.2 R2.2 R10.2 R41.2 R42.2 R63.2 R73.2 R801.2 R802.2 R805.2 R_CAN_SHDN.2 R_CAN_STB.2 R_FRAME_PD.2 R_USB_CTS.1 R_USB_VBUS_L.2 RAD_C1.1 RAD_C2.1 RAD_C5.1 RAD_C6.1 RAD_C8.1 RAD_C9.2 RAD_C10.2 RAD_C15.2 RAD_C22.1 RAD_C23.2 RAD_C25.2 RAD_C26.2 RAD_C29.2 RAD_C31.2 RAD_C58.2 RAD_C60.2 RAD_C92.1 RAD_C96.1 RAD_C99.2 RAD_C100.2 RAD_C101.2 RAD_C102.2 RAD_C103.2 RAD_C104.2 RAD_C105.1 RAD_C106.2 RAD_C107.1 RAD_C108.2 RAD_C110.2 RAD_C111.1 RAD_C112.2 RAD_C113.1 RAD_C114.2 RAD_C115.1 RAD_C116.2 RAD_C117.1 RAD_C118.1 RAD_C119.2 RAD_C125.2 RAD_C126.2 RAD_C129.2 RAD_C130.2 RAD_C132.2 RAD_C134.2 RAD_C137.1 RAD_C138.1 RAD_C139.1 RAD_C140.1 RAD_C141.1 RAD_C142.1 RAD_C143.2 RAD_C144.1 RAD_C145.2 RAD_C146.1 RAD_C149.1 RAD_C150.1 RAD_C153.1 RAD_C163.1 RAD_C164.1 RAD_C165.1 RAD_C168.1 RAD_C170.1 RAD_C172.1 RAD_C173.1 RAD_C174.1 RAD_C175.1 RAD_C176.1 RAD_C177.1 RAD_C179.2 RAD_C180.2 RAD_C181.2 RAD_C195.2 RAD_C199.2 RAD_C200.2 RAD_C201.2 RAD_C202.2 RAD_NT1.1 RAD_NT2.2 RAD_NT3.2 RAD_NT4.2 RAD_R1.2 RAD_R2.1 RAD_R292.1 RAD_R302.1 RAD_R307.1 RAD_R313.1 RAD_U1.4 RAD_U1.9 RAD_U2.9 RAD_U2.13 RAD_U8.12 RAD_U8.26 RAD_U9.1 RAD_U9.2 RAD_U9.7 RAD_U11.1 RAD_U11.7 RAD_U12.2 RAD_U12.7 RAD_U22.1 RAD_U22.7 RAD_U27.2 RAD_U29.A1 RAD_U29.A2 RAD_U29.A4 RAD_U29.A6 RAD_U29.A8 RAD_U29.A10 RAD_U29.A12 RAD_U29.A18 RAD_U29.B2 RAD_U29.B4 RAD_U29.B6 RAD_U29.B8 RAD_U29.B10 RAD_U29.C1 RAD_U29.C2 RAD_U29.C3 RAD_U29.C4 RAD_U29.C5 RAD_U29.C6 RAD_U29.C7 RAD_U29.C8 RAD_U29.C9 RAD_U29.C10 RAD_U29.D2 RAD_U29.D3 RAD_U29.E1 RAD_U29.E2 RAD_U29.E3 RAD_U29.E11 RAD_U29.E18 RAD_U29.F3 RAD_U29.F6 RAD_U29.F7 RAD_U29.F8 RAD_U29.F9 RAD_U29.F10 RAD_U29.F11 RAD_U29.F12 RAD_U29.F13 RAD_U29.G1 RAD_U29.G2 RAD_U29.G3 RAD_U29.G6 RAD_U29.G7 RAD_U29.G8 RAD_U29.G9 RAD_U29.G10 RAD_U29.G11 RAD_U29.G12 RAD_U29.G13 RAD_U29.G14 RAD_U29.H3 RAD_U29.H6 RAD_U29.H7 RAD_U29.H8 RAD_U29.H9 RAD_U29.H10 RAD_U29.H11 RAD_U29.H12 RAD_U29.H13 RAD_U29.J1 RAD_U29.J2 RAD_U29.J3 RAD_U29.J6 RAD_U29.J7 RAD_U29.J8 RAD_U29.J9 RAD_U29.J10 RAD_U29.J11 RAD_U29.J12 RAD_U29.J13 RAD_U29.K3 RAD_U29.K6 RAD_U29.K7 RAD_U29.K8 RAD_U29.K9 RAD_U29.K10 RAD_U29.K11 RAD_U29.K12 RAD_U29.K13 RAD_U29.K16 RAD_U29.L1 RAD_U29.L2 RAD_U29.L3 RAD_U29.L6 RAD_U29.L7 RAD_U29.L8 RAD_U29.L9 RAD_U29.L10 RAD_U29.L11 RAD_U29.L12 RAD_U29.L13 RAD_U29.M3 RAD_U29.M6 RAD_U29.M7 RAD_U29.M8 RAD_U29.M9 RAD_U29.M10 RAD_U29.M11 RAD_U29.M12 RAD_U29.M13 RAD_U29.M14 RAD_U29.N1 RAD_U29.N2 RAD_U29.N3 RAD_U29.N7 RAD_U29.N8 RAD_U29.N9 RAD_U29.N10 RAD_U29.N11 RAD_U29.N12 RAD_U29.N13 RAD_U29.P8 RAD_U29.P12 RAD_U29.P18 RAD_U29.V1 RAD_U29.V2 RAD_U29.V9 RAD_U29.V14 RAD_U29.V18 RAD_Y3.2 RAD_Y3.4 SW1.2 TP_RAD_GND.1 U1.14 U1.22 U1.37 U1.48 U1.61 U1.71 U1.90 U1.102 U1.113 U1.126 U1.135 U1.148 U1.158 U2.6 U2.7 U2.9 U4.2 U4.9 U5.5 U5.6 U5.15 U5.16 U5.17 U6.8 U6.11 U6.25 U7.8 U8.13 U8.14 U8.15 U8.17 U8.19 U8.24 U8.25 U8.26 U8.27 U8.28 U8.29 U8.30 U8.31 U9.5 U9.6 U9.15 U9.16 U9.17 U_CAN_RAD.2 U_CAN_RAD.9 U_FRAME.3 U_USB.3 U_USB.12 U_USB.21 Y1.2 | length 20619
  Top Layer w6.3: v5(1309.06,1179.13) 1310.04,1180.12 1313.98,1180.12 1319.88,1186.02 RAD_U29.V14@1320.3,1185.62 ; RAD_U29.P18@1422.67,1083.26 1422.24,1083.66 1428.15,1077.76 1428.15,1074.8 v5(1430.12,1072.83) ; v5(1649.61,1070.87) 1652.56,1073.82 1652.56,1083.66 RAD_U29.E18@1652.98,1083.26 ; v5(1696.01,1507.92) 1696.65,1508.56 1696.65,1510.48 1704.33,1518.16 RAD_U29.C1@1704.16,1518.3 ; v5(1754.92,1069.88) 1754.92,1083.66 RAD_U29.A18@1755.34,1083.26 ; v5(1832.28,1591.73) 1845.08,1604.53 RAD_C108.2@1845.21,1604.58
  Top Layer w6.69: RAD_C176.1@1219.49,1003.94 1241.14,980.32 1239.17,910.43 v5(1267.72,878.94) ; v2(1266.73,1225.39) v5(1271.65,1186.02) ; v5(1400.59,1208.66) 1411.42,1225.39 1454.72,1267.72 v3(1454.72,1300.2) ; v2(1901.57,1263.78) v5(1918.31,1176.18) ; v5(1921.26,850.39) 1928.15,812.01 1934.06,806.1 1974.41,806.1 v2(2055.12,820.87) v5(2088.58,854.33) ; v5(2099.41,864.17) RAD_C8.1@2099.61,845.28 ; v8(2160.43,1100.39) 2171.26,1100.39 ; v8(2165.35,964.57) RAD_U8.12@2165.35,994.09 ; v5(2168.31,821.85) RAD_C202.2@2168.6,813.19
  Top Layer w7.09: v5(1125.98,1043.31) RAD_C174.1@1141.73,1043.31 ; v5(1192.91,1078.74) 1200.79,1070.87 RAD_C115.1@1200.79,1062.99 ; v5(1234.25,1358.27) RAD_C2.1@1250,1358.27 ; RAD_C139.1@1259.84,1673.23 1259.84,1657.48 v5(1261.81,1655.51) ; v5(1309.06,1090.55) 1312.99,1090.55 1320.87,1082.68 RAD_U29.V18@1320.3,1083.26 ; v5(1336.71,1596.26) 1337.6,1597.15 1337.6,1609.55 1337.6,1609.25 ; RAD_C142.1@1358.27,1692.91 v5(1374.02,1692.91) ; v5(1440.94,826.77) RAD_C168.1@1456.69,826.77 ; RAD_U29.K16@1525.03,1134.44 1525.39,1134.74 1530.71,1129.43 1532.48,1129.43 v5(1535.14,1126.77) ; v6(1602.36,1003.94) RAD_C114.2@1643.7,1003.94 1644.09,1003.64 1624.61,1003.64 v5(1615.75,1012.5) ; v1(1729.75,1492.7) v1(1742.56,1487.4) v1(1756,1482.45) ; RAD_C9.2@1815.35,1062.99 RAD_C9.2@1814.96,1062.99 v5(1828.74,1062.99) ; RAD_Y3.2@1859.26,1676.68 1860.24,1677.17 1872.05,1677.17 1885.83,1663.39 1887.8,1663.39 1889.76,1661.42 1915.35,1661.42 1938.98,1685.04 v2(1939.96,1686.02) ; RAD_C119.2@1978.35,767.72 2003.94,793.31 2003.94,799.21 2005.91,801.18 2005.91,803.15 2011.81,809.06 2043.31,809.06 v2(2055.12,820.87) ; RAD_U8.26@2165.35,1131.89 2165.35,1108.27 2171.26,1102.36 2171.26,1100.39 2173.23,1098.43 2175.2,1098.43 v5(2179.13,1094.49)
  Top Layer w7.87: RAD_C101.2@753.94,1909.45 785.43,1877.95 785.43,1872.05 789.37,1868.11 789.37,1866.14 791.34,1866.14 797.24,1860.24 797.24,1846.46 RAD_U2.9@797.24,1846.06 ; RAD_U1.4@1006.89,1523.62 1083.66,1446.85 1083.66,1417.32 RAD_U1.9@1082.68,1417.32 ; v6(1049.21,2102.36) 1055.12,2096.46 1151.57,2096.46 1228.35,2019.68 1228.35,1968.5 RAD_C126.2@1200.79,1940.94 ; v6(1057.09,2017.72) 1102.36,1972.44 RAD_R1.2@1102.36,1948.82 ; RAD_C176.1@1219.49,1003.94 1243.11,1003.94 v6(1263.78,1024.61) ; RAD_U29.V2@1320.3,1492.7 1319.88,1494.09 RAD_U29.V1@1319.88,1517.72 ; RAD_U29.V1@1320.3,1518.3 RAD_U29.V1@1319.88,1517.72 ; 1338.58,1578.74 1337.6,1579.72 ; 1338.58,1610.24 1337.6,1609.25 1337.6,1579.72 ; RAD_U29.P12@1422.67,1236.8 1423.23,1237.2 RAD_U29.N12@1446.85,1237.2 ; RAD_U29.N13@1448.26,1211.21 1446.85,1210.63 RAD_U29.M13@1473.43,1210.63 ; RAD_U29.N12@1448.26,1236.8 RAD_U29.N12@1446.85,1237.2 ; RAD_U29.N11@1448.26,1262.39 1446.85,1263.78 RAD_U29.M11@1473.43,1263.78 ; RAD_U29.M14@1473.85,1185.62 1473.43,1187.01 RAD_U29.M13@1473.43,1210.63 ; RAD_U29.M13@1473.85,1211.21 RAD_U29.M13@1473.43,1210.63 ; RAD_U29.M12@1473.85,1236.8 RAD_U29.M12@1473.43,1237.2 ; RAD_U29.M11@1473.85,1262.39 RAD_U29.M11@1473.43,1263.78 ; RAD_U29.M10@1473.85,1287.98 RAD_U29.M10@1473.43,1287.4 ; RAD_U29.L13@1499.44,1211.21 1500,1210.63 RAD_U29.L12@1500,1237.2 ; RAD_U29.L12@1499.44,1236.8 RAD_U29.L12@1500,1237.2 ; RAD_U29.L11@1499.44,1262.39 RAD_U29.L11@1500,1263.78 ; RAD_U29.L10@1499.44,1287.98 RAD_U29.L10@1500,1287.4 ; RAD_U29.K13@1525.03,1211.21 RAD_U29.K13@1523.62,1210.63 ; RAD_U29.K12@1525.03,1236.8 RAD_U29.K12@1523.62,1237.2 ; RAD_U29.K11@1525.03,1262.39 1523.62,1263.78 RAD_U29.L11@1500,1263.78 ; RAD_U29.K10@1525.03,1287.98 1523.62,1287.4 RAD_U29.L10@1500,1287.4 ; RAD_U29.K9@1525.03,1313.57 1523.62,1313.98 1523.62,1340.55 RAD_U29.K8@1525.03,1339.16 ; v6(1539.37,925.2) RAD_C146.1@1562.99,925.2 ; RAD_U29.J13@1550.62,1211.21 RAD_U29.J13@1550.2,1210.63 ; RAD_U29.J12@1550.62,1236.8 1550.2,1237.2 RAD_U29.J13@1550.2,1210.63 ; RAD_U29.J11@1550.62,1262.39 RAD_U29.J11@1550.2,1263.78 ; RAD_U29.J10@1550.62,1287.98 RAD_U29.J10@1550.2,1287.4 ; RAD_U29.J9@1550.62,1313.57 RAD_U29.J9@1550.2,1313.98 ; RAD_U29.J8@1550.62,1339.16 1550.2,1340.55 RAD_U29.J9@1550.2,1313.98 ; v6(1562.99,901.57) 1590.55,929.13 1590.55,940.94 1596.46,946.85 1631.89,946.85 1653.54,925.2 1653.54,923.23 1635.83,905.51 1635.83,883.86 1647.64,872.05 1687.01,872.05 1696.85,862.2 1728.35,862.2 1753.94,887.8 1753.94,899.61 v6(1771.65,917.32) ; RAD_U29.H13@1576.21,1211.21 RAD_U29.H13@1576.77,1210.63 ; RAD_U29.H12@1576.21,1236.8 1576.77,1237.2 RAD_U29.H13@1576.77,1210.63 ; RAD_U29.H11@1576.21,1262.39 RAD_U29.H11@1576.77,1263.78 ; RAD_U29.H10@1576.77,1287.4 RAD_U29.H11@1576.77,1263.78 ; RAD_U29.G14@1601.8,1185.62 1600.39,1187.01 1600.39,1210.63 RAD_U29.H13@1576.77,1210.63 ; v6(1602.36,1003.94) RAD_C114.2@1643.7,1003.94 ; RAD_C9.2@1814.96,1062.99 1815.94,1062.99 RAD_C9.2@1845.47,1062.99 ; RAD_C9.2@1846.46,1062.99 RAD_C9.2@1845.47,1062.99 ; RAD_C134.2@1909.45,1077.76 1910.43,1077.76 1875,1077.76 1860.24,1062.99 RAD_C9.2@1845.47,1062.99 ; RAD_C129.2@2022.64,846.46 2022.64,847.44 2049.21,820.87 v2(2055.12,820.87) ; v6(2214.57,881.89) 2214.57,887.8 2232.28,905.51 RAD_C6.1@2232.28,906.5 ; RAD_U29.V1@1319.88,1517.72 1319.88,1538.39 1316.93,1541.34 1316.93,1562.01 1325.79,1570.87 1328.74,1570.87 1337.6,1579.72 ; RAD_U29.N12@1446.85,1237.2 RAD_U29.M12@1473.43,1237.2 ; RAD_U29.M13@1473.43,1210.63 RAD_U29.M12@1473.43,1237.2 ; RAD_U29.M12@1473.43,1237.2 RAD_U29.M11@1473.43,1263.78 ; RAD_U29.M11@1473.43,1263.78 RAD_U29.M10@1473.43,1287.4 ; RAD_U29.M10@1473.43,1287.4 RAD_U29.L10@1500,1287.4 ; RAD_U29.L12@1500,1237.2 RAD_U29.K12@1523.62,1237.2 ; RAD_U29.L12@1500,1237.2 RAD_U29.L11@1500,1263.78 ; RAD_U29.L11@1500,1263.78 RAD_U29.L10@1500,1287.4 ; RAD_U29.K13@1523.62,1210.63 RAD_U29.J13@1550.2,1210.63 ; RAD_U29.K13@1523.62,1210.63 RAD_U29.K12@1523.62,1237.2 ; RAD_U29.J13@1550.2,1210.63 RAD_U29.H13@1576.77,1210.63 ; RAD_U29.J11@1550.2,1263.78 RAD_U29.J10@1550.2,1287.4 ; RAD_U29.J11@1550.2,1263.78 RAD_U29.H11@1576.77,1263.78 ; RAD_U29.J10@1550.2,1287.4 RAD_U29.J9@1550.2,1313.98
  Top Layer w9.45: v2(649.61,1772.02) 649.61,1771.65 679.13,1801.18 690.94,1801.18 RAD_C195.2@690.2,1801.01 ; v2(747.05,2161.42) 744.09,2164.37 741.14,2164.37 723.43,2182.09 708.66,2182.09 693.9,2196.85 693.9,2199.8 690.94,2202.76 690.94,2247.05 693.9,2250 693.9,2252.95 699.8,2252.95 702.76,2255.91 738.19,2255.91 741.14,2252.95 747.05,2252.95 776.57,2223.43 RAD_C104.2@775.59,2224.41 ; RAD_C100.2@753.94,2303.15 752.95,2303.15 752.95,2391.73 v2(770.67,2409.45) ; v15(787.4,1791.34) 788.39,1792.32 797.24,1801.18 797.24,1845.47 RAD_U2.9@797.24,1846.06 ; RAD_C10.2@803.56,1605.4 803.15,1606.3 v2(847.44,1650.59) ; RAD_C173.1@866.14,2162.4 865.16,2161.42 882.87,2143.7 882.87,2134.84 v2(881.89,2133.86) ; v2(879.92,1390.75) 879.92,1420.28 915.35,1455.71 RAD_C1.1@915.35,1454.72 ; v2(974.41,1615.16) 1003.94,1585.63 1003.94,1570.87 1006.89,1567.91 1006.89,1523.62 RAD_U1.4@1007.68,1524.67 ; v2(1077.76,2019.68) 1101.38,1996.06 1101.38,1948.82 RAD_R1.2@1102.36,1948.82 ; RAD_C5.1@1082.68,1141.73 1083.66,1142.72 1068.9,1142.72 v2(1060.04,1151.57) 1062.99,1154.53 1095.47,1154.53 1098.43,1157.48 1101.38,1157.48 1107.28,1163.39 1127.95,1163.39 1130.91,1166.34 1133.86,1166.34 1148.62,1181.1 1160.43,1181.1 RAD_C117.1@1161.42,1181.1 ; RAD_C176.1@1220.47,1003.94 1219.49,1003.94 1234.25,1003.94 v2(1260.83,977.36) ; RAD_C112.2@1240.16,1190.94 1240.16,1189.96 1257.87,1207.68 1257.87,1216.54 v2(1266.73,1225.39) ; 1259.84,889.76 1260.83,888.78 1249.02,900.59 1243.11,900.59 1237.2,906.5 1237.2,938.98 1243.11,944.88 1243.11,959.65 v2(1260.83,977.36) ; RAD_C111.1@1299.21,984.25 1299.21,983.27 1266.73,983.27 v2(1260.83,977.36) ; RAD_R307.1@1318.9,826.77 1319.88,826.77 1319.88,838.58 v2(1311.02,847.44) 1331.69,826.77 1378.94,826.77 RAD_C96.1@1377.95,826.77 ; RAD_C165.1@1358.27,925.2 1358.27,924.21 v2(1378.94,924.21) 1367.13,936.02 1367.13,1003.94 RAD_C116.2@1368.11,1003.94 ; RAD_U29.P8@1422.67,1339.16 1423.23,1340.55 1426.18,1343.5 1435.04,1343.5 1467.52,1375.98 ; RAD_U29.N10@1448.26,1287.98 1446.85,1287.4 1446.85,1355.32 ; RAD_U29.N9@1448.26,1313.57 1446.85,1313.98 1446.85,1355.32 ; RAD_U29.N8@1448.26,1339.16 1446.85,1340.55 1446.85,1355.32 ; RAD_U29.N7@1448.26,1364.75 1446.85,1364.17 1452.76,1370.08 1461.61,1370.08 1467.52,1375.98 ; RAD_C107.1@1456.69,925.2 1455.71,924.21 v2(1473.43,906.5) ; v2(1467.52,1039.37) 1482.28,1024.61 1485.24,1024.61 RAD_C110.2@1505.91,1003.94 ; RAD_U29.M9@1473.85,1313.57 1473.43,1313.98 RAD_U29.M7@1473.43,1367.13 ; RAD_U29.M8@1473.85,1339.16 1473.43,1340.55 RAD_U29.M7@1473.43,1367.13 ; RAD_U29.M7@1473.85,1364.75 1473.43,1364.17 RAD_U29.M7@1473.43,1367.13 ; RAD_U29.M6@1473.85,1390.34 1473.43,1390.75 1467.52,1396.65 ; RAD_U29.L9@1499.44,1313.57 1500,1313.98 RAD_U29.L8@1500,1340.55 ; RAD_U29.L8@1499.44,1339.16 RAD_U29.L8@1500,1340.55 ; RAD_U29.L7@1499.44,1364.75 1500,1364.17 1467.52,1396.65 ; RAD_U29.L6@1499.44,1390.34 1500,1390.75 1482.28,1390.75 ; RAD_U29.K8@1525.03,1339.16 1523.62,1340.55 1467.52,1396.65 ; RAD_U29.K7@1525.03,1364.75 1523.62,1364.17 1473.43,1414.37 1426.18,1414.37 v2(1423.23,1417.32) 1429.13,1411.42 1461.61,1411.42 ; RAD_U29.K6@1525.03,1390.34 1523.62,1390.75 1482.28,1390.75 ; RAD_U29.J7@1550.62,1364.75 1550.2,1364.17 1550.2,1405.51 v2(1553.15,1408.46) ; RAD_U29.H10@1576.21,1287.98 1576.77,1287.4 RAD_U29.H6@1576.77,1384.84 ; RAD_U29.H9@1576.21,1313.57 1576.77,1313.98 RAD_U29.H6@1576.77,1384.84 ; RAD_U29.H8@1576.21,1339.16 1576.77,1340.55 RAD_U29.H6@1576.77,1384.84 ; RAD_U29.H7@1576.21,1364.75 1576.77,1364.17 RAD_U29.H6@1576.77,1384.84 ; RAD_U29.H6@1576.21,1390.34 1576.77,1390.75 1559.06,1408.46 v2(1553.15,1408.46) ; RAD_U29.G13@1601.8,1211.21 1600.39,1210.63 1600.39,1243.11 v2(1647.64,1290.35) ; RAD_U29.G12@1601.8,1236.8 1600.39,1237.2 1635.83,1272.64 1635.83,1278.54 v2(1647.64,1290.35) ; RAD_U29.G11@1601.8,1262.39 1600.39,1263.78 1621.06,1263.78 v2(1647.64,1290.35) ; RAD_U29.G10@1601.8,1287.98 1600.39,1287.4 v2@1644.68,1287.4 ; RAD_U29.G9@1601.8,1313.57 1600.39,1313.98 1624.02,1313.98 v2(1647.64,1290.35) ; RAD_U29.G8@1601.8,1339.16 1600.39,1340.55 1635.83,1305.12 1635.83,1302.17 v2(1647.64,1290.35) ; RAD_U29.G7@1601.8,1364.75 1600.39,1364.17 1564.96,1399.61 1562.01,1399.61 v2(1553.15,1408.46) ; RAD_C163.1@1614.17,826.77 1615.16,826.77 1629.92,826.77 1632.87,829.72 1659.45,829.72 v2(1671.26,817.91) 1700.79,847.44 1712.6,847.44 RAD_C175.1@1712.6,846.46 ; RAD_U29.F13@1627.39,1211.21 1626.97,1210.63 1626.97,1269.68 ; RAD_U29.F12@1627.39,1236.8 1626.97,1237.2 1626.97,1269.68 ; RAD_U29.F11@1627.39,1262.39 1626.97,1263.78 1644.68,1281.5 v2@1644.68,1287.4 ; RAD_U29.F10@1627.39,1287.98 1626.97,1287.4 v2@1644.68,1287.4 ; RAD_U29.F9@1627.39,1313.57 1626.97,1313.98 1644.68,1296.26 1644.68,1293.31 v2(1647.64,1290.35) ; RAD_U29.F8@1627.39,1339.16 1626.97,1340.55 RAD_U29.F9@1626.97,1311.02 ; RAD_U29.F7@1627.39,1364.75 1626.97,1364.17 RAD_U29.F9@1626.97,1311.02 ; RAD_U29.F6@1627.39,1390.34 1626.97,1390.75 1570.87,1390.75 v2(1553.15,1408.46) ; RAD_U29.E11@1652.98,1262.39 1653.54,1263.78 1653.54,1284.45 v2(1647.64,1290.35) ; RAD_U29.D3@1678.57,1467.11 1677.17,1467.52 v2@1677.17,1449.8 ; RAD_U29.D2@1678.57,1492.7 1677.17,1494.09 v2@1677.17,1449.8 ; v2(1683.07,1443.9) v2@1677.17,1449.8 ; v2(2055.12,820.87) 2066.93,832.68 2066.93,835.63 2087.6,856.3 RAD_C8.1@2086.61,855.32 ; v2(2137.8,687.99) 2146.65,696.85 2146.65,708.66 RAD_C200.2@2145.67,708.66 ; RAD_C202.2@2180.12,787.4 2179.13,788.39 2199.8,788.39 v2(2211.61,800.2) ; RAD_C153.1@2233.27,748.03 2232.28,747.05 2232.28,776.57 2220.47,788.39 2220.47,791.34 v2(2211.61,800.2) ; RAD_C6.1@2233.27,905.51 2232.28,906.5 2232.28,876.97 2220.47,865.16 2220.47,809.06 v2(2211.61,800.2) ; RAD_C201.2@2317.91,826.77 2317.91,785.43 v2(2323.82,779.53) 2341.54,797.24 2341.54,806.1 2347.44,812.01 2356.3,812.01 2379.92,835.63 2382.87,835.63 RAD_C31.2@2381.89,836.61 ; RAD_C143.2@2362.2,910.43 2362.2,909.45 2362.2,912.4 2406.5,956.69 2406.5,1000.98 2403.54,1003.94 2403.54,1006.89 2400.59,1006.89 2397.64,1009.84 ; v8(2381.89,1058.07) RAD_U9.1@2382.87,1057.09 ; RAD_U9.1@2382.87,1039.37 2400.59,1057.09 RAD_U9.2@2401.57,1058.07 ; v5(2404.53,1032.48) 2413.39,1023.62 v5(2452.76,1023.62) ; 2438.98,1195.87 2438.98,1207.68 2441.93,1210.63 2441.93,1225.39 RAD_U9.7@2440.94,1225.39 ; RAD_U27.2@2507.87,1200.79 2506.89,1201.77 2515.75,1201.77 2527.56,1189.96 2533.46,1189.96 2536.42,1187.01 2539.37,1187.01 2542.32,1184.06 2542.32,1175.2 v2(2548.23,1169.29) 2554.13,1163.39 2554.13,1136.81 2589.57,1101.38 RAD_C149.1@2590.55,1102.36 ; v6@2595.47,855.32 2622.05,881.89 v5(2624.02,945.87) ; RAD_C145.2@2677.17,1228.35 2678.15,1228.35 2704.72,1228.35 v2(2713.58,1237.2) 2695.87,1254.92 2695.87,1293.31 RAD_U12.7@2696.85,1294.29 ; RAD_U12.2@2736.22,1461.61 2737.2,1461.61 2737.2,1491.14 2743.11,1497.05 2784.45,1497.05 v2(2793.31,1488.19) ; 1446.85,1355.32 1467.52,1375.98 ; 1461.61,1411.42 1467.52,1405.51 ; 1461.61,1411.42 1482.28,1390.75 ; 1467.52,1373.03 RAD_U29.M7@1473.43,1367.13 ; 1467.52,1373.03 1467.52,1405.51 ; 1467.52,1373.03 RAD_U29.L8@1500,1340.55 ; 1467.52,1375.98 1467.52,1405.51 ; 1467.52,1396.65 1467.52,1405.51 ; v2(1553.15,1408.46) RAD_U29.H6@1576.77,1384.84 ; 1626.97,1269.68 v2(1647.64,1290.35) ; RAD_U29.F9@1626.97,1311.02 v2(1647.64,1290.35) ; v2@1644.68,1287.4 v2(1647.64,1290.35)
  Top Layer w11.81: v6(2165.35,948.82) RAD_U8.12@2165.35,994.09 ; v8(2165.35,1145.67) RAD_U8.26@2165.35,1131.89 v5(2165.35,1161.42)
  Top Layer w12.6: RAD_C22.1@585.65,1921.91 v2(649.61,1861.12)
  Top Layer w21.65: RAD_C29.2@614.12,1772.02 v2(649.61,1772.02) ; RAD_C25.2@614.12,1861.12 v2(649.61,1861.12)
  PWR1 w6.3: v2(1266.73,1225.39) 1335.63,1225.39 v3(1454.72,1300.2)
  PWR2 w9.45: v2(2385.83,1154.53) 2385.83,1108.27 2403.54,1090.55 2423.23,1090.55 2498.03,1015.75 2498.03,989.17 2587.6,899.61 v6@2595.47,855.32
  GND1 w6.3: v5(1336.71,1596.26) 1319.88,1557.09 1319.88,1543.31 1322.83,1537.4 1330.71,1530.51 1342.52,1528.54 1411.42,1537.4 v17(1425.2,1551.18) v1(1429.74,1615) ; 1367.13,1291.34 1386.81,1271.65 1388.78,1265.75 1388.78,1258.86 1385.83,1251.97 1379.92,1246.06 1375,1245.08 ; 1378.94,1245.08 1434.06,1300.2 v3(1454.72,1300.2)
  GND1 w6.69: v5(1192.91,1078.74) 1250,1050.2 1262.8,1037.4 v6(1263.78,1024.61) ; v5(1267.72,878.94) 1301.18,847.44 v2(1311.02,847.44) ; v5(1271.65,1186.02) v5(1309.06,1179.13) ; v3(1485.24,1278.54) 1483.27,1280.51 1377.95,1280.51 1367.13,1291.34 1381.89,1281.5 1426.18,1281.5 v2(1553.15,1408.46) ; v5(2099.41,864.17) 2125.98,864.17 v5(2168.31,821.85) ; v1(2392,1337.51) 2371.06,1275.59 v2(2385.83,1154.53) 2372.05,1263.78 2372.05,1279.53 2378.94,1289.37 v1(2419.66,1314.71)
  GND1 w7.09: v1(1729.75,1492.7) v1(1742.56,1487.4) v1(1756,1482.45)
  GND1 w9.45: v8(2381.89,1058.07) v5(2404.53,1032.48) v8(2406.5,984.25) ; v8(2433.07,1189.96) v2(2548.23,1169.29) ; v5(2452.76,1023.62) 2456.69,1027.56 2548.23,1027.56 2606.3,969.49 v5(2624.02,945.87)
  GND1 w15.75: v3(2060.04,2953.74) v3(2174.21,2925.2)
  SIG1 w6.69: v2(1467.52,1039.37) v3(1485.24,1278.54)
  SIG1 w7.09: v3(948.82,984.25) 1120.08,1155.51 v3(1135.83,1155.51)
  SIG2 w7.09: v6(1562.99,901.57) 1566.93,901.57 1574.8,909.45 1622.05,909.45 v3(1631.89,899.61) ; v3(1779.53,2946.85) 1781.5,2946.85 1816.93,2982.28 1844.49,2982.28 1879.92,2946.85 v3(1879.92,2933.07)
  SIG2 w7.87: U4.9@2760.83,1614.17 2760.83,1615.16 v6(2884.84,1615.16)
  GND2 w6.69: v6(1771.65,917.32) 1781.5,927.17 v7(1922.24,962.6) ; v2(1901.57,1263.78) v9(1948.82,1123.03) ; v7(2371.06,1191.93) v7(2371.06,1250)
  GND2 w9.45: v11(1926.97,786.91) 1999.02,858.27 v7(2048.23,858.27) ; v9(2369.09,1072.83) v9@2370.08,1071.85 ; v9(2438.98,1192.91) v7(2471.46,1225.39)
  Bottom Layer w6.3: C13.2@1259.84,2166.14 v11(1274.61,2150.59) ; v11(1505.91,1348.43) RAD_C103.2@1519.69,1362.21 ; U9.6@1505.91,2953.49 v7(1515.75,2972.44) ; U1.14@2017.72,1882.87 v7(2017.72,1919.29) ; v11(2126.97,951.77) RAD_C132.2@2145.67,975.39 ; v11(2150.59,1687.01) C_FRAME.2@2166.14,1702.76 ; v11(2194.88,1750) U_FRAME.3@2219.49,1755.91 ; v11(2596.46,2080.71) D3.8@2598.43,2062.4
  Bottom Layer w6.69: v6(1771.65,917.32) 1792.32,928.15 1794.29,939.96 1851.38,1054.13 1918.31,1116.14 ; v7(1922.24,962.6) RAD_C130.2@1948.82,989.17 ; RAD_U22.7@1943.9,1122.05 1918.31,1116.14 ; v9(1948.82,1123.03) 1918.31,1116.14 ; v7(2371.06,1191.93) v2(2385.83,1154.53) ; v7(2371.06,1250) 2371.06,1275.59 v11(2390.16,1320.47)
  Bottom Layer w7.09: v3(948.82,984.25) 962.6,970.47 998.03,970.47 1003.94,976.38 1005.91,976.38 1005.91,978.35 1009.84,982.28 1009.84,988.19 1041.34,1019.68 1041.34,1021.65 1043.31,1021.65 1043.31,1023.62 1045.28,1023.62 1047.24,1025.59 1074.8,1025.59 1102.36,1053.15 RAD_C177.1@1102.36,1062.99 ; v3(1135.83,1155.51) 1169.29,1122.05 1169.29,1090.55 1157.48,1078.74 1157.48,1047.24 1157.48,1048.23 ; v6(1208.66,818.9) 1220.47,830.71 RAD_R302.1@1220.47,846.46 ; v11(1230.91,1836.12) 1230.91,1861.71 C6I.2@1231.3,1862.2 ; v11(1287.2,1902.66) 1287.2,1928.25 C6D.2@1287.4,1928.15 ; v11@1349.41,1786.42 1349.9,1786.22 v11(1349.9,1783.66) ; v11(1406.2,2904.53) 1410.04,2908.37 1410.04,2910.93 1411.32,2912.2 1411.32,2914.76 1412.6,2916.04 1412.6,2917.32 1413.88,2918.6 1415.16,2918.6 1416.44,2919.88 1417.72,2919.88 1419,2921.16 1435.63,2921.16 1436.91,2919.88 1438.19,2919.88 1439.47,2918.6 1440.75,2918.6 1440.75,2917.32 1443.31,2914.76 1443.31,2885.33 1447.15,2881.5 U1.90@1446.85,2880.91 ; v11(1425.89,2925.39) 1426.97,2924.31 1428.05,2924.31 1431.3,2921.06 1434.55,2921.06 1435.63,2919.98 1437.8,2919.98 1442.13,2915.65 1442.37,2916.09 ; RAD_C105.1@1456.69,787.4 1456.1,786.91 1456.1,771.56 v11(1457.38,770.28) ; RAD_C170.1@1614.17,885.83 1618.11,885.83 v3(1631.89,899.61) ; U1.102@1683.07,2880.91 1683.07,2879.92 1685.04,2881.89 1685.04,2915.35 1690.94,2921.26 1765.75,2921.26 1779.53,2935.04 v3(1779.53,2946.85) ; v6(1771.65,917.32) 1777.56,923.23 1787.4,923.23 1789.37,925.2 1791.34,925.2 ; v11(1845.08,1837.4) 1860.43,1852.76 1860.43,1883.46 U1.22@1860.24,1882.87 ; v2(1869.09,2961.61) 1870.08,2962.6 1879.92,2952.76 1879.92,2940.94 1881.89,2938.98 1881.89,2935.04 1899.61,2917.32 U1.113@1899.61,2879.92 ; v3(1879.92,2933.07) 1899.61,2913.39 U1.113@1899.61,2879.92 ; v6(1881.89,1562.99) 1893.7,1574.8 1905.51,1574.8 RAD_U11.1@1904.53,1574.8 ; U1.113@1899.61,2880.91 U1.113@1899.61,2879.92 ; v11(1926.97,786.91) 1928.25,785.63 1928.25,770.28 RAD_C58.2@1928.15,770.67 ; v11(1994.78,1241.14) 1996.06,1239.86 2016.54,1239.86 RAD_C144.1@2016.73,1240.16 ; v6(2043.31,1726.38) 2047.24,1730.32 2047.24,1750 R_FRAME_PD.2@2047.24,1749.02 ; v3(2060.04,2953.74) C11.2@2085.63,2952.76 ; RAD_U22.1@2111.22,1181.1 2111.22,1181 2116.34,1181 v11(2129.13,1193.8) ; U1.126@2155.51,2880.91 2158.46,2911.42 2160.43,2916.34 v3(2174.21,2925.2) ; C112.2@2166.14,1338.58 2166.24,1338.39 2166.24,1325.59 v11(2175.2,1316.63) ; C107.2@2303.15,1436.22 2302.85,1436.71 2302.85,1454.04 v11(2305.02,1456.2) ; 2364.17,956.69 2366.14,954.72 2366.14,952.76 2370.08,948.82 2372.05,948.82 2374.02,946.85 2415.35,946.85 2417.32,944.88 D_USB.3@2416.73,944.88 ; v11(2390.16,1320.47) 2401.67,1308.96 2414.47,1308.96 R_CAN_SHDN.2@2414.37,1309.06 ; RAD_NT1.1@2500,910.2 2500,909.45 2574.8,909.45 2576.77,907.48 2578.74,907.48 2590.55,895.67 2590.55,864.17 2594.49,860.24 2594.49,854.33 v6(2596.46,852.36) ; C_USB_4U7.2@2567.91,925.2 2566.93,925.2 2592.52,899.61 2592.52,856.3 v6(2596.46,852.36) ; C_USB_100N.2@2618.11,865.35 2618.11,866.14 2606.3,854.33 2598.43,854.33 v6(2596.46,852.36) ; U4.2@2749.02,1559.06 2748.43,1558.46 2748.43,1571.26 v11(2754.82,1577.66)
  Bottom Layer w7.87: v2(629.92,2149.61) 653.54,2149.61 C809.2@653.54,2148.62 ; v2(818.9,2448.82) 818.9,2460.63 830.71,2472.44 C808.2@829.72,2472.44 ; v2(881.89,2133.86) 905.51,2133.86 D1.2@905.51,2131.89 ; v2(885.83,2602.36) 909.45,2602.36 R802.2@908.46,2604.33 ; v2(889.76,2724.41) 913.39,2724.41 R801.2@912.4,2724.41 ; v2(897.64,2578.74) 905.51,2570.87 905.51,2555.12 C804.2@906.5,2555.12 ; v2(937.01,2610.24) 960.63,2610.24 C803.2@960.63,2609.25 ; v2(984.25,2913.39) 1007.87,2913.39 C800.2@1008.86,2913.39 ; v2(1003.94,1850.39) 1011.81,1842.52 1011.81,1826.77 R63.2@1013.78,1827.76 ; v2(1003.94,3051.18) 1027.56,3051.18 C801.2@1028.54,3051.18 ; v2(1011.81,2712.6) 1011.81,2700.79 1023.62,2688.98 U8.15@1024.11,2687.01 ; v2(1015.75,2066.93) 1039.37,2066.93 C806.2@1037.4,2067.91 ; v6(1049.21,2102.36) 1057.09,2094.49 v6(1057.09,2017.72) ; RAD_C92.1@1161.42,1003.94 1160.43,1003.94 1160.43,1045.28 1157.48,1048.23 1157.48,1080.71 1163.39,1086.61 1210.63,1086.61 1240.16,1057.09 1249.02,1057.09 1263.78,1042.32 v6(1263.78,1024.61) ; U8.31@1181.1,2688.98 1196.85,2704.72 1196.85,2708.66 1220.47,2732.28 U8.25@1220.47,2730.81 ; C802.2@1181.1,2845.47 1181.1,2846.46 1181.1,2862.2 v2(1224.41,2905.51) ; U8.24@1200.79,2730.81 1200.79,2732.28 1200.79,2708.66 v2(1204.72,2704.72) ; U8.31@1224.41,2681.1 1240.16,2696.85 1240.16,2732.28 U8.26@1240.16,2730.81 ; U6.8@1289.37,1808.56 U6.8@1290.35,1810.04 ; U6.25@1318.9,1732.28 1319.88,1733.27 1290.35,1762.8 U6.8@1290.35,1810.04 ; U6.11@1348.43,1808.56 1349.41,1810.04 1349.41,1786.42 1340.55,1777.56 1299.21,1777.56 1290.35,1786.42 U6.8@1290.35,1810.04 ; 1488.19,1799.21 1503.94,1814.96 1503.94,1826.77 R1.2@1504.92,1826.77 ; U9.17@1496.06,3011.81 U9.17@1497.05,3011.81 ; 1500,1578.74 1503.94,1582.68 1527.56,1582.68 R805.2@1528.54,1582.68 ; U9.6@1505.91,2954.23 U9.6@1505.91,2952.76 ; U9.15@1505.91,3069.39 U9.15@1505.91,3070.87 ; RAD_C164.1@1514.76,865.16 1514.76,876.97 v6(1541.34,903.54) ; U9.5@1525.59,2954.23 1526.57,2952.76 U9.6@1505.91,2952.76 ; U9.16@1525.59,3069.39 1526.57,3070.87 U9.15@1505.91,3070.87 ; v6(1539.37,925.2) 1547.24,925.2 RAD_C137.1@1566.93,944.88 ; v6(1562.99,901.57) 1562.99,964.57 v6(1602.36,1003.94) ; RAD_C181.2@1708.66,925.2 1709.65,924.21 1677.17,924.21 RAD_C181.2@1677.17,925.2 1685.04,925.2 1692.91,917.32 v6(1771.65,917.32) ; v2(1708.66,1622.05) 1732.28,1622.05 C7D.2@1732.28,1623.03 ; v2(1732.28,1755.91) 1740.16,1763.78 1755.91,1763.78 U7.8@1755.91,1762.8 ; R73.2@1896.65,1240.16 1897.64,1240.16 1897.64,1259.84 v2(1901.57,1263.78) ; RAD_C58.2@1929.13,771.65 1928.15,770.67 1928.15,803.15 RAD_C58.2@1929.13,803.15 ; v6(2165.35,948.82) 2214.57,899.61 v6(2214.57,881.89) ; 2224.41,1519.68 2224.41,1507.87 2236.22,1496.06 R2.2@2237.2,1496.06 ; v2(2450.79,2214.57) 2500.98,2214.57 U2.9@2500.49,2214.57 ; U_USB.21@2560.04,1062.99 2586.61,1062.99 2595.47,1071.85 2619.09,1071.85 U_USB.3@2620.08,1072.83 ; D3.3@2598.43,2032.09 2598.43,2031.5 2598.43,2061.02 D3.8@2598.43,2062.4 ; U5.15@2678.64,1446.85 U5.15@2678.15,1446.85 ; U5.16@2678.64,1466.54 2678.15,1467.52 U5.15@2678.15,1446.85 ; U5.17@2736.22,1437.01 2737.2,1437.99 2728.35,1446.85 U5.15@2678.15,1446.85 ; v6(2884.84,1615.16) 2902.56,1632.87 2905.51,1632.87 R41.2@2906.5,1633.86 ; U9.17@1497.05,3011.81 1497.05,3041.34 1505.91,3050.2 U9.15@1505.91,3070.87 ; U9.17@1497.05,3011.81 1497.05,2982.28 1505.91,2973.43 U9.6@1505.91,2952.76
  Bottom Layer w9.06: v17(1425.2,1551.18) 1426.18,1550.2 1485.24,1550.2 1491.14,1556.1 1491.14,1570.87 1500,1579.72 1500,1578.74 ; 1488.19,1799.21 1488.19,1798.23 1497.05,1789.37 1553.15,1789.37 1564.96,1777.56 1570.87,1777.56 1582.68,1765.75 1582.68,1762.8 1585.63,1759.84 1585.63,1724.41 1579.72,1718.5 1579.72,1700.79 1562.01,1683.07 1562.01,1680.12 1544.29,1662.4 1544.29,1653.54 1541.34,1650.59 v17(1541.34,1651.57) ; v17(2183.07,1568.9) 2182.09,1567.91 2223.43,1526.57 2223.43,1520.67 2224.41,1519.68
  Bottom Layer w9.45: v2(770.67,2409.45) 779.53,2400.59 779.53,2397.64 785.43,2391.73 788.39,2391.73 806.1,2374.02 826.77,2374.02 C93.2@826.77,2373.03 ; RAD_R2.1@826.77,2244.09 865.16,2205.71 865.16,2152.56 882.87,2134.84 v2(881.89,2133.86) ; v2(1011.81,2712.6) v2@1012.8,2713.58 ; U8.13@1024.11,2647.64 1024.61,2648.62 1024.61,2701.77 ; U8.14@1024.11,2667.32 1024.61,2666.34 1024.61,2701.77 ; U8.17@1062.99,2730.81 1062.99,2731.3 1062.99,2707.68 1060.04,2704.72 1060.04,2701.77 1057.09,2698.82 1054.13,2698.82 1051.18,2695.87 1030.51,2695.87 ; U8.19@1102.36,2730.81 1101.38,2731.3 1101.38,2704.72 1098.43,2701.77 1098.43,2698.82 1092.52,2698.82 1089.57,2695.87 1030.51,2695.87 ; RAD_C138.1@1259.84,944.88 1260.83,944.88 v2(1260.83,977.36) 1319.88,918.31 1319.88,865.16 RAD_C140.1@1318.9,866.14 ; RAD_C113.1@1377.95,846.46 1378.94,847.44 1367.13,847.44 1364.17,844.49 1361.22,844.49 1358.27,841.54 1340.55,841.54 1337.6,844.49 1334.65,844.49 1328.74,850.39 1328.74,853.35 1325.79,856.3 1325.79,874.02 1328.74,876.97 1328.74,879.92 1358.27,909.45 1361.22,909.45 1364.17,912.4 1367.13,912.4 v2(1378.94,924.21) 1423.23,924.21 1446.85,900.59 1446.85,897.64 1449.8,894.68 1449.8,891.73 1455.71,885.83 RAD_C172.1@1456.69,885.83 ; RAD_C164.1@1515.75,866.14 1514.76,865.16 1508.86,871.06 1508.86,888.78 1505.91,891.73 1505.91,894.68 1500,900.59 1497.05,900.59 1494.09,903.54 1476.38,903.54 v2(1473.43,906.5) 1529.53,906.5 1567.91,944.88 RAD_C137.1@1566.93,944.88 ; Y1.2@1701.77,1735.24 1700.79,1736.22 1712.6,1736.22 1733.27,1756.89 v2(1732.28,1755.91) ; v2(1869.09,2961.61) 1877.95,2970.47 ; J10.5@1895.08,3001.18 1895.67,3000 1877.95,2982.28 1877.95,2970.47 ; J10.3@1895.08,3051.18 1895.67,3050.2 1895.67,2997.05 1877.95,2979.33 1877.95,2970.47 ; v2(2019.68,1626.97) 2025.59,1632.87 2072.83,1632.87 RAD_U11.7@2071.85,1633.86 ; v7(2048.23,858.27) v2(2055.12,820.87) ; v2(2300.2,2500.98) 2306.1,2506.89 2314.96,2506.89 2314.96,2509.84 2350.39,2509.84 U1.148@2349.41,2509.84 ; U_CAN_RAD.2@2325.79,1135.83 2326.77,1136.81 2332.68,1142.72 2332.68,1157.48 2335.63,1157.48 2338.58,1160.43 2379.92,1160.43 v2(2385.83,1154.53) 2394.68,1163.39 2394.68,1169.29 ; 2362.2,950.79 2368.11,944.88 2385.83,944.88 v9(2386.42,944.88) ; R_CAN_STB.2@2368.11,1071.85 v9(2369.09,1072.83) ; R_CAN_STB.2@2370.08,1071.85 2385.83,1049.21 2396.65,1038.39 2448.82,1038.39 2468.5,1058.07 2468.5,1104.33 ; v2(2415.35,2453.74) 2424.21,2444.88 2424.21,2436.02 2441.93,2418.31 C12.2@2440.94,2419.29 ; C_CAN_RAD.2@2430.12,1198.82 C_CAN_RAD.2@2431.1,1200 ; U2.6@2460.63,2174.7 2459.65,2176.18 2459.65,2205.71 v2(2450.79,2214.57) 2450.79,2211.61 2462.6,2199.8 2462.6,2193.9 2480.32,2176.18 U2.7@2480.31,2174.7 ; v7(2471.46,1225.39) 2571.85,1225.39 2580.71,1216.54 2580.71,1185.04 2569.88,1174.21 2553.15,1174.21 v2(2548.23,1169.29) 2554.13,1175.2 2577.76,1175.2 2580.71,1178.15 2580.71,1181.1 2583.66,1184.06 2583.66,1219.49 2577.76,1225.39 2539.37,1225.39 2530.51,1216.54 2500.98,1216.54 RAD_NT2.2@2500,1215.79 ; U_USB.21@2559.06,1062.99 2560.04,1062.99 2554.13,1062.99 2527.56,1036.42 2524.61,1036.42 2521.65,1033.46 2474.41,1033.46 2471.46,1036.42 2468.5,1036.42 2468.5,1042.32 2465.55,1045.28 2465.55,1101.38 2468.5,1104.33 ; C21.2@2559.06,2134.84 2560.04,2134.84 v2(2598.43,2134.84) ; v26(2577.76,1954.72) 2586.61,1945.87 2598.43,1945.87 D4.3@2598.43,1946.36 ; v2(2604.33,1316.93) 2622.05,1316.93 2639.76,1299.21 C1.2@2638.78,1299.21 ; D8.8@2657.48,2465.16 2657.48,2465.55 v2(2657.48,2438.98) 2657.48,2495.08 D8.3@2657.48,2495.47 ; U5.17@2736.22,1437.01 2737.2,1437.99 2743.11,1437.99 2769.68,1464.57 2775.59,1464.57 2778.54,1467.52 2781.5,1467.52 2781.5,1470.47 2784.45,1473.43 2784.45,1479.33 v2(2793.31,1488.19) 2793.31,1446.85 U5.6@2793.8,1446.85 ; C106.2@2854.33,2323.62 2855.32,2323.82 2870.08,2323.82 v2(2875.98,2317.91) ; C109.2@2932.28,2263.78 2932.09,2264.76 v2(2955.71,2264.76) ; C110.2@2951.97,2342.52 2952.76,2341.54 v2(2952.76,2365.16) 2955.71,2368.11 3029.53,2368.11 3032.48,2365.16 3035.43,2365.16 3035.43,2362.2 3038.39,2359.25 3038.39,2326.77 3035.43,2323.82 3035.43,2320.87 3029.53,2314.96 3029.53,2264.76 C20.2@3030.71,2263.78 ; v2@1012.8,2713.58 1024.61,2701.77 ; v2@1012.8,2713.58 1030.51,2695.87 ; 2468.5,1104.33 2468.5,1107.28 2471.46,1110.24 2474.41,1110.24 v2(2483.27,1119.09) 2468.5,1104.33
  Bottom Layer w15.75: v7(2149.61,991.65) v6(2165.35,948.82) 2187.99,930.61 v6(2214.57,881.89)
  Bottom Layer w21.65: RAD_C26.2@614.12,1772.02 v2(649.61,1772.02) ; RAD_C23.2@614.12,1861.12 v2(649.61,1861.12)
  other v1: 1729.75,1287.99 1744.37,1294.88 1712.04,1298.21 1760.24,1298.23 1780.91,1298.23 1801.58,1298.23 1822.25,1298.23 1842.92,1298.23 1863.59,1298.23 1884.26,1298.23 1904.93,1298.23 1925.6,1298.23 1946.27,1298.23 1966.94,1298.23 1987.61,1298.23 2008.28,1298.23 2028.95,1298.23 2049.62,1298.23 2070.29,1298.23 2090.96,1298.23 2111.63,1298.23 2132.3,1298.23 2152.97,1298.23 2173.64,1298.23 2194.31,1298.23 2214.98,1298.23 2235.65,1298.23 2256.32,1298.23 2276.99,1298.23 2297.66,1298.23 2318.33,1298.23 2339,1298.38 2359.62,1299.73 2379,1302.66 2400.09,1308.07 1706.32,1314.04 2438.43,1323.23 1712.04,1328.92 1747.47,1328.91 1772.7,1328.91 1793.37,1328.91 1814.04,1328.91 1834.71,1328.91 1855.38,1328.91 1876.05,1328.91 1896.72,1328.91 1917.39,1328.91 1938.06,1328.91 1958.73,1328.91 1979.4,1328.91 2000.07,1328.91 2020.74,1328.91 2041.41,1328.91 2062.08,1328.91 2082.75,1328.91 2103.42,1328.91 2124.09,1328.91 2144.76,1328.91 2165.43,1328.91 2186.1,1328.91 2206.77,1328.91 2227.44,1328.91 2248.11,1328.91 2268.78,1328.91 2289.45,1328.91 2310.12,1328.91 2330.79,1328.91 2351.45,1329.74 2371.91,1332.63 2455.69,1332.7 1729.75,1339.17 2411.5,1344.36 2473.41,1345.4 1712.04,1349.39 1747.47,1349.41 1764.76,1349.41 1785.43,1349.41 1806.1,1349.41 1826.77,1349.41 1847.44,1349.41 1868.11,1349.41 1888.78,1349.41 1909.45,1349.41 1930.12,1349.41 1950.79,1349.41 1971.46,1349.41 1992.13,1349.41 2012.8,1349.41 2033.47,1349.41 2054.14,1349.41 2074.81,1349.41 2095.48,1349.41 2116.15,1349.41 2136.82,1349.41 2157.49,1349.41 2178.16,1349.41 2198.83,1349.41 2219.5,1349.41 2240.17,1349.41 2260.84,1349.41 2281.51,1349.41 2302.18,1349.41 2322.85,1349.41 2345.71,1349.81 2430.04,1353.5 2365.56,1354.36 2487.89,1357.48 2383.56,1362.57 1706.09,1364.91 2447.48,1364.6 2502.65,1371.87 2399.72,1374.56 2463.74,1377.36 1747.47,1380.09 1767.62,1380.09 1788.29,1380.09 1808.96,1380.09 1829.63,1380.09 1850.3,1380.09 1870.97,1380.09 1891.64,1380.09 1912.31,1380.09 1932.98,1380.09 1953.65,1380.09 1974.32,1380.09 1994.99,1380.09 2015.66,1380.09 2036.33,1380.09 2057,1380.09 2077.67,1380.09 2098.34,1380.09 2119.01,1380.09 2139.68,1380.09 2160.35,1380.09 2181.02,1380.09 2201.69,1380.09 2222.36,1380.09 2243.03,1380.09 2263.7,1380.09 2284.37,1380.09 2305.04,1380.09 2325.71,1380.09 1712.04,1381.9 2346.31,1381.9 2365.56,1389.42 1729.75,1390.35 2412.9,1389.51 2516.82,1389.51 2478.66,1391.67 1712.04,1400.57 1747.47,1400.59 1764.95,1400.59 1785.62,1400.59 1806.29,1400.59 1826.96,1400.59 1847.63,1400.59 1868.3,1400.59 1888.97,1400.59 1909.64,1400.59 1930.31,1400.59 1950.98,1400.59 1971.65,1400.59 1992.32,1400.59 2012.99,1400.59 2033.66,1400.59 2054.33,1400.59 2075,1400.59 2095.67,1400.59 2116.34,1400.59 2137.01,1400.59 2157.68,1400.59 2178.35,1400.59 2199.02,1400.59 2219.69,1400.59 2240.22,1402.13 2382.28,1401.57 2492.09,1407.37 2528.3,1406.7 2260.27,1407.54 2423.95,1408.82 1706.09,1416.13 2278.2,1415.68 2394.44,1418.28 2503.58,1424.56 2539.06,1425.63 2294.34,1427 2431.02,1428.24 1747.47,1431.27 1767.44,1431.27 1788.11,1431.27 1808.78,1431.27 1829.45,1431.27 1850.12,1431.27 1870.79,1431.27 1891.46,1431.27 1912.13,1431.27 1932.8,1431.27 1953.47,1431.27 1974.14,1431.27 1994.81,1431.27 2015.48,1431.27 2036.15,1431.27 2056.82,1431.27 2077.49,1431.27 2098.16,1431.27 2118.83,1431.27 2139.5,1431.27 2160.17,1431.27 2180.84,1431.27 2201.51,1431.27 2222.18,1431.18 1712.04,1433.8 2242.4,1434.57 2401.98,1437.53 2309.37,1441.25 1729.75,1441.53 2261.74,1442.51 2513.09,1442.91 2546.69,1443.69 1743.37,1447.38 2434.12,1448.68 1712.04,1451.75 1756.68,1451.78 1777.35,1451.78 1798.02,1451.78 1818.69,1451.78 2278.25,1454.41 2403.81,1458.12 2248.48,1460.21 2321.56,1460.89 2520.75,1462.11 2553.33,1463.27 1525.03,1467.11 1576.21,1467.11 1704.16,1467.11 1473.85,1469 1627.51,1469 2434.49,1469.34 2291.54,1470.21 1458.5,1474.99 1489.21,1474.99 1509.68,1474.99 1540.39,1474.99 1560.86,1474.99 1591.57,1474.99 1612.04,1474.99 1642.75,1474.99 2403.81,1478.79 2329.8,1479.84 1712.04,1482.46 1776.67,1482.45 1797.34,1482.45 1818.01,1482.45 2526.47,1481.97 2558.24,1482.98 2300.47,1488.85 2434.49,1490.01 1448.26,1492.7 1499.43,1492.7 1550.61,1492.7 1601.79,1492.7 1652.97,1492.7 2403.81,1499.46 2334.41,1499.99 2530.22,1502.3 2560.87,1503.89 2304.57,1509.11 1458.51,1510.42 1489.19,1510.42 1509.69,1510.42 1540.37,1510.42 1560.87,1510.42 1591.55,1510.42 1612.05,1510.42 1642.73,1510.42 2434.49,1510.68 2403.81,1520.13 2335.64,1520.63 2531.57,1522.93 2562.22,1524.51 1458.51,1528.81 1489.19,1528.81 1509.69,1528.81 1540.37,1528.81 1560.87,1528.81 1591.55,1528.81 1612.05,1528.81 1642.73,1528.81 2304.96,1529.78 2434.49,1531.35 2335.64,1541.3 2403.81,1540.8 2531.49,1543.6 2562.16,1545.18 1458.51,1546.48 1489.19,1546.48 1509.69,1546.48 1540.37,1546.48 1560.87,1546.48 1591.55,1546.48 1612.05,1546.48 1642.73,1546.48 2304.96,1550.45 2434.49,1552.02 2403.81,1561.47 2335.64,1561.97 2531.49,1564.27 1458.51,1565.15 1489.19,1565.15 1509.69,1565.15 1540.37,1565.15 1560.87,1565.15 1591.55,1565.15 1612.05,1565.15 1642.73,1565.15 2562.16,1565.85 2088.07,1569.29 2304.96,1571.12 2434.49,1572.69 2403.81,1582.14 2335.64,1582.64 1456.32,1583.87 1489.39,1583.78 1505.27,1584.43 1595.96,1584.43 1611.85,1583.78 1644.92,1583.87 2531.49,1584.94 2562.16,1586.52 1537.02,1588.67 1564.21,1588.67 2304.96,1591.79 2434.49,1593.36 1442.47,1598.71 1495.95,1598.71 1605.28,1598.71 1658.77,1598.71 2335.64,1603.31 2403.81,1602.81 1481.13,1603.5 1620.1,1603.5 2531.49,1605.61 1528.96,1607.5 1572.27,1607.5 2562.16,1607.19 2304.96,1612.46 2434.49,1614.03 1671.49,1615 1467.45,1617.7 1483.69,1618.42 1617.55,1618.42 1633.3,1618.42 2403.81,1623.48 1517.16,1624.22 1584.08,1624.22 2335.64,1623.98 2531.49,1626.28 2562.16,1627.86 1620.62,1632.98 2305.08,1633.13 1423.08,1634.73 1456.53,1634.79 1644.71,1634.79 1678.17,1634.73 2434.49,1634.7 1480.61,1635.81 1511.76,1638.83 1589.48,1638.83 2403.81,1644.15 2334.72,1644.55 2531.49,1646.95 2562.16,1648.53 2301.61,1653.5 1423.08,1655.46 1453.75,1655.46 1480.61,1655.46 1511.29,1655.46 1589.95,1655.46 1620.62,1655.46 1647.48,1655.46 1678.16,1655.46 2434.49,1655.37 2245.04,1658.29 2330.87,1664.12 2403.81,1664.82 2531.49,1667.62 2562.16,1669.2 2292.97,1672.28 1423.08,1676.13 1453.75,1676.13 1480.61,1676.13 1511.29,1676.13 1589.95,1676.13 1620.62,1676.13 1647.48,1676.13 1678.16,1676.13 2434.49,1676.04 2322.33,1683.47 2403.81,1685.49 2278.55,1687.28 2531.49,1688.29 2562.16,1689.87 1423.08,1696.8 1453.75,1696.8 1480.61,1696.8 1511.29,1696.8 1589.95,1696.8 1620.62,1696.8 1647.48,1696.8 1678.16,1696.8 2434.49,1696.71 2261.23,1697.97 2309.37,1700.34 2241,1702.67 2178.35,1703.67 2199.86,1703.67 2220.53,1703.67 2158.11,1706.16 2403.81,1706.16 2531.49,1708.96 2562.16,1710.54 2140.12,1712.27 2294.34,1714.52 1423.08,1717.47 1453.75,1717.47 1480.61,1717.47 1511.29,1717.47 1589.95,1717.47 1620.62,1717.47 1647.48,1717.47 1678.16,1717.47 2434.12,1717.46 2121.71,1721.9 2276.67,1725 2400.91,1726.62 2531.49,1729.63 2562.16,1731.21 2256.97,1731.84 2194.95,1734.34 2215.62,1734.34 2236.29,1734.24 2104.14,1735.44 2174.29,1735.04 1521.71,1735.97 1579.53,1735.97 1423.08,1738.14 1453.75,1738.14 1647.48,1738.14 1678.16,1738.14 2429.45,1737.58 1483.69,1739.6 1617.55,1739.6 2154.51,1740.1 2390.36,1744.39 2135.99,1749.41 2531.49,1750.3 2090.6,1751 2562.16,1751.88 1529.26,1756.34 1571.98,1756.34 2373.59,1756.48 2420.19,1756.06 1423.08,1758.81 1453.75,1758.81 1495.95,1758.81 1605.28,1758.81 1647.48,1758.81 1678.16,1758.81 2291.54,1761.07 2312.06,1760.84 2332.73,1760.84 2353.4,1760.9 2120.86,1763.48 2271.41,1767.02 2080.02,1768.88 2531.49,1770.97 2404.8,1773.02 2562.16,1772.55 1423.08,1779.48 1453.75,1779.48 1497.88,1779.48 1528.56,1779.48 1572.68,1779.48 1603.36,1779.48 1647.48,1779.48 1678.16,1779.48 2250.23,1779.72 2109.22,1780.52 2388.94,1783.42 2072.69,1787.96 2369.58,1789.73 2307.65,1791.52 2328.32,1791.52 2348.99,1791.52 2531.49,1791.64 2562.16,1793.22 2287.12,1793.89 2233.77,1799.27 1423.08,1800.15 1453.75,1800.15 1497.88,1800.15 1528.56,1800.15 1572.68,1800.15 1603.36,1800.15 1647.48,1800.15 1678.16,1800.15 2101.73,1799.58
  other v3: 1320.3,1313.57
  other v4: 1839.36,1451.78 1860.03,1451.78 1880.7,1451.78 1901.37,1451.78 1922.04,1451.78 1942.71,1451.78 2126.73,1452.11 2147.4,1452.11 2168.07,1452.11 2188.74,1452.11 2209.41,1452.11 2230.07,1451.58 1963.15,1454.3 2106.13,1453.76 2087.7,1461.46 1980.35,1466.44 2073.32,1477.76 2261.9,1477.87 1838.68,1482.45 1859.35,1482.45 1880.02,1482.45 1900.69,1482.45 1921.36,1482.45 1942.03,1482.45 2123.72,1482.78 2144.39,1482.78 2165.06,1482.78 2185.73,1482.78 2206.4,1482.78 2227.06,1483.33 1990.48,1484.46 2103.88,1488.59 1960.72,1491.29 2065.42,1497.25 2263.46,1498.66 2232.79,1503.19 1992.42,1505.04 2096.1,1507.74 1961.74,1511.93 2065.42,1517.89 2263.46,1519.34 2232.79,1523.86 1992.42,1525.71 2096.1,1528.41 1961.74,1532.6 2065.42,1538.56 2263.46,1540.01 2232.79,1544.53 1992.99,1546.37 2095.67,1549.33 1963.15,1553.22 2011.71,1555.12 2032.38,1555.12 2053.05,1555.12 2263.46,1560.67 2232.79,1565.2 1972.82,1571.49 2263.46,1581.35 2072.22,1581.87 1990.48,1583.43 2010.48,1585.8 2031.15,1585.8 2051.82,1585.8 2232.79,1585.87 2263.46,1602.02 2232.79,1606.54 2263.26,1622.68 2231.37,1627.16 2129.85,1635.98 2150.52,1635.66 2171.19,1635.66 2191.86,1635.66 2212.53,1635.66 2109.23,1637.34 2090.96,1640.28 2257.74,1642.6 2069.2,1645.53 2049.5,1653.53 2030.96,1662.67 2162.62,1666.34 2183.29,1666.34 2203.96,1666.34 2224.28,1665.99 2121.62,1667.37 2141.66,1666.62 2101.13,1670.23 2012.8,1673.06 2080.9,1675.04 2061.53,1682.03 1996.63,1685.65 2042.9,1691.19 1981.09,1699.28 2025.63,1702.26 1965.66,1715.09 2009.48,1715.24 1994.85,1729.7 1953.36,1731.84 1981.71,1745.71 1943.34,1748.32 1970.3,1762.96 1934.2,1766.85 1961.21,1781.7 1926.03,1785.47 1954.28,1801.21
  other v9: 1564.4,1441.52 1633.29,1441.52 1661.42,1445.87 1385.26,1467.11 2322.83,1594.49
  other v11: 2126.57,1239.86 1996.06,1750.39
  other v15: 748.03,1791.34 826.77,1791.34
GNSS_PPS: D8.4 J8.4 U1.40 | length 1929.4
  SIG1 w6.69: v27(2062.99,2476.38) 2216.54,2476.38 2291.34,2551.18 2401.57,2551.18 2437.01,2515.75 v6(2677.17,2515.75)
  Bottom Layer w6.69: U1.40@1505.91,1882.87 1507.87,1881.89 1507.87,1921.26 v27(2062.99,2476.38) ; D8.4@2677.17,2495.47 2677.17,2496.06 v6(2677.17,2515.75)
  Bottom Layer w7.09: J8.4@2613.19,2769.68 2633.86,2790.35 2633.86,2805.12 2642.72,2813.98 2684.06,2813.98 2684.06,2811.02 2687.01,2808.07 2687.01,2722.44 2684.06,2719.49 2684.06,2518.7 2678.15,2512.8 2678.15,2495.08 D8.4@2677.17,2495.47
GNSS_RX_EXT: D8.1 J8.2 U1.96 | length 1867.5
  Top Layer w6.69: v6(1755.91,2940.94) 1909.45,2787.4 2712.6,2787.4 v6(2732.28,2767.72)
  Bottom Layer w6.69: U1.96@1564.96,2880.91 1566.93,2881.89 1566.93,2933.07 1574.8,2940.94 v6(1755.91,2940.94) ; 2698.82,2819.88 2700.79,2818.9 2704.72,2814.96 2704.72,2795.28 v6(2732.28,2767.72)
  Bottom Layer w7.09: D8.1@2618.11,2495.47 2619.09,2495.08 2619.09,2698.82 2589.57,2728.35 2589.57,2811.02 2592.52,2813.98 2619.09,2813.98 2633.86,2828.74 2692.91,2828.74 2698.82,2822.83 2698.82,2819.88 2701.77,2816.93 2701.77,2778.54 2710.63,2769.68 J8.2@2711.61,2769.68
GNSS_TX_EXT: D8.2 J8.3 U1.97 | length 1469.8
  SIG2 w6.69: v6(1586.61,2921.26) 1775.59,2921.26 1929.13,2767.72 v6(2641.73,2767.72)
  Bottom Layer w6.69: U1.97@1584.65,2880.91 1586.61,2881.89 v6(1586.61,2921.26) ; v6(2641.73,2767.72) 2661.42,2767.72 J8.3@2662.4,2769.68
  Bottom Layer w7.09: D8.2@2637.8,2495.47 2636.81,2495.08 2636.81,2681.1 2660.43,2704.72 2660.43,2766.73 2663.39,2769.68 J8.3@2662.4,2769.68
HOST_UART1_RX: R600.2 R602.2 TP2.1 U1.150 | length 1331.2
  SIG1 w7.09: v2(2306.1,2471.46) 2418.31,2359.25 2441.93,2359.25 2521.65,2279.53 2524.61,2279.53 v21(2527.56,2276.57) ; v2(2598.43,2291.34) 2746.06,2291.34 v2(2772.64,2264.76)
  Bottom Layer w7.09: v2(2306.1,2471.46) 2350.39,2471.46 U1.150@2349.41,2470.47 ; v21(2527.56,2276.57) 2539.37,2264.76 R600.2@2565.94,2264.76 ; R600.2@2565.94,2263.78 R600.2@2565.94,2264.76 ; v2(2598.43,2291.34) 2589.57,2282.48 2583.66,2282.48 R600.2@2565.94,2264.76 ; v2(2772.64,2264.76) R602.2@2796.26,2264.76 ; R602.2@2794.88,2263.78 R602.2@2796.26,2264.76 ; TP2.1@2992.13,2578.74 2991.14,2577.76 3073.82,2495.08 3073.82,2323.82 3053.15,2303.15 3053.15,2244.09 3047.24,2238.19 2878.94,2238.19 2875.98,2241.14 2873.03,2241.14 2858.27,2255.91 2858.27,2282.48 2852.36,2288.39 2816.93,2288.39 2811.02,2282.48 2811.02,2279.53 R602.2@2796.26,2264.76
HOST_UART1_RX_EXT: D3.2 J6.3 R602.1 | length 440.1
  SIG1 w7.09: v3(2614.17,2011.81) 2795.28,2047.24 J6.3@2834.65,2086.61
  Bottom Layer w7.09: v3(2614.17,2011.81) D3.2@2618.11,2032.09 ; J6.3@2834.65,2086.61 2834.65,2087.6 2834.65,2264.76 R602.1@2835.04,2263.78
HOST_UART1_TX: R601.2 TP1.1 U1.147 | length 1291.3
  SIG1 w7.09: v2(2306.1,2530.51) 2406.5,2430.12 2453.74,2430.12 2551.18,2332.68 2560.04,2332.68 2577.76,2314.96 2577.76,2279.53 ; v2(2675.2,2252.95) 2657.48,2270.67 2586.61,2270.67 2577.76,2279.53 ; v2(2695.87,2220.47) 2687.01,2229.33 2678.15,2229.33 2645.67,2261.81 2595.47,2261.81 2577.76,2279.53 ; v2(2961.61,2459.65) 2940.94,2438.98 2725.39,2438.98 2598.43,2312.01 2586.61,2312.01 2577.76,2303.15 2577.76,2279.53
  Bottom Layer w7.09: v2(2306.1,2530.51) 2350.39,2530.51 U1.147@2349.41,2529.53 ; v2(2675.2,2252.95) 2687.01,2264.76 R601.2@2695.87,2264.76 ; v2(2695.87,2220.47) R601.2@2695.87,2264.76 ; R601.2@2696.46,2263.78 R601.2@2695.87,2264.76 ; v2(2961.61,2459.65) 2991.14,2489.17 2991.14,2500.98 TP1.1@2992.13,2500
HOST_UART1_TX_EXT: D3.1 J6.2 R601.1 | length 579.3
  Bottom Layer w7.09: D3.1@2637.8,2032.09 D3.1@2636.81,2031.5 ; R601.1@2736.61,2263.78 2737.2,2264.76 2740.16,2261.81 2740.16,2140.75 2757.87,2123.03 2757.87,2049.21 2754.92,2046.26 2657.48,2046.26 2651.57,2040.35 2645.67,2040.35 D3.1@2636.81,2031.5 ; J6.2@2834.65,1968.5 2834.65,1969.49 2802.17,2001.97 2760.83,2001.97 2749.02,2013.78 2695.87,2013.78 2684.06,2025.59 2642.72,2025.59 D3.1@2636.81,2031.5
HOST_UART2_RX: R604.2 R605.2 U1.121 | length 1039.6
  SIG1 w7.09: v3(2012.8,2925.2) 2016.14,2912.6 2118.9,2820.47 v3(2271.26,2666.34)
  SIG2 w7.09: v3(2271.26,2666.34) 2308.46,2657.48 2423.62,2531.69 2478.54,2476.77 v3(2517.72,2476.38)
  Bottom Layer w6.3: v3(2012.8,2925.2) 2025.59,2939.96 2031.5,2942.91 2043.31,2942.91 2046.26,2941.93 2054.13,2935.04 2057.09,2929.13 U1.121@2057.09,2880.91
  Bottom Layer w7.09: v3(2517.72,2476.38) R605.2@2519.68,2453.74 2518.7,2453.74 2592.52,2453.74 2657.48,2388.78 2669.29,2388.78 2695.87,2362.2 R604.2@2696.85,2362.6
HOST_UART2_RX_EXT: D3.5 J6.6 R604.1 | length 624.9
  SIG1 w7.09: v2(2675.2,2314.96) 2684.06,2306.1 2754.92,2306.1 2775.59,2285.43 2784.45,2285.43 2793.31,2276.57 2793.31,2238.19 2719.49,2164.37 2719.49,2090.55 2716.54,2087.6 J6.6@2716.54,2086.61
  Bottom Layer w7.09: D3.5@2559.06,2032.09 2560.04,2031.5 2554.13,2031.5 2542.32,2043.31 2542.32,2081.69 2545.28,2084.65 2591.54,2099.41 2604.33,2099.41 2713.58,2084.65 2716.54,2087.6 J6.6@2716.54,2086.61 ; v2(2675.2,2314.96) 2684.06,2323.82 2695.87,2323.82 R604.1@2696.85,2322.44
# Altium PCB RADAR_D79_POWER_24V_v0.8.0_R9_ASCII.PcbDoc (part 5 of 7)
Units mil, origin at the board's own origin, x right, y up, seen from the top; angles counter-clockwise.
Board outline 3110.24 x 3110.24 mil, 8 copper layers (Top Layer, GND1, SIG1, PWR1, PWR2, SIG2, GND2, Bottom Layer), stack 55.2 mil thick; 304 components, 269 nets, 1408 pads, 1366 vias.

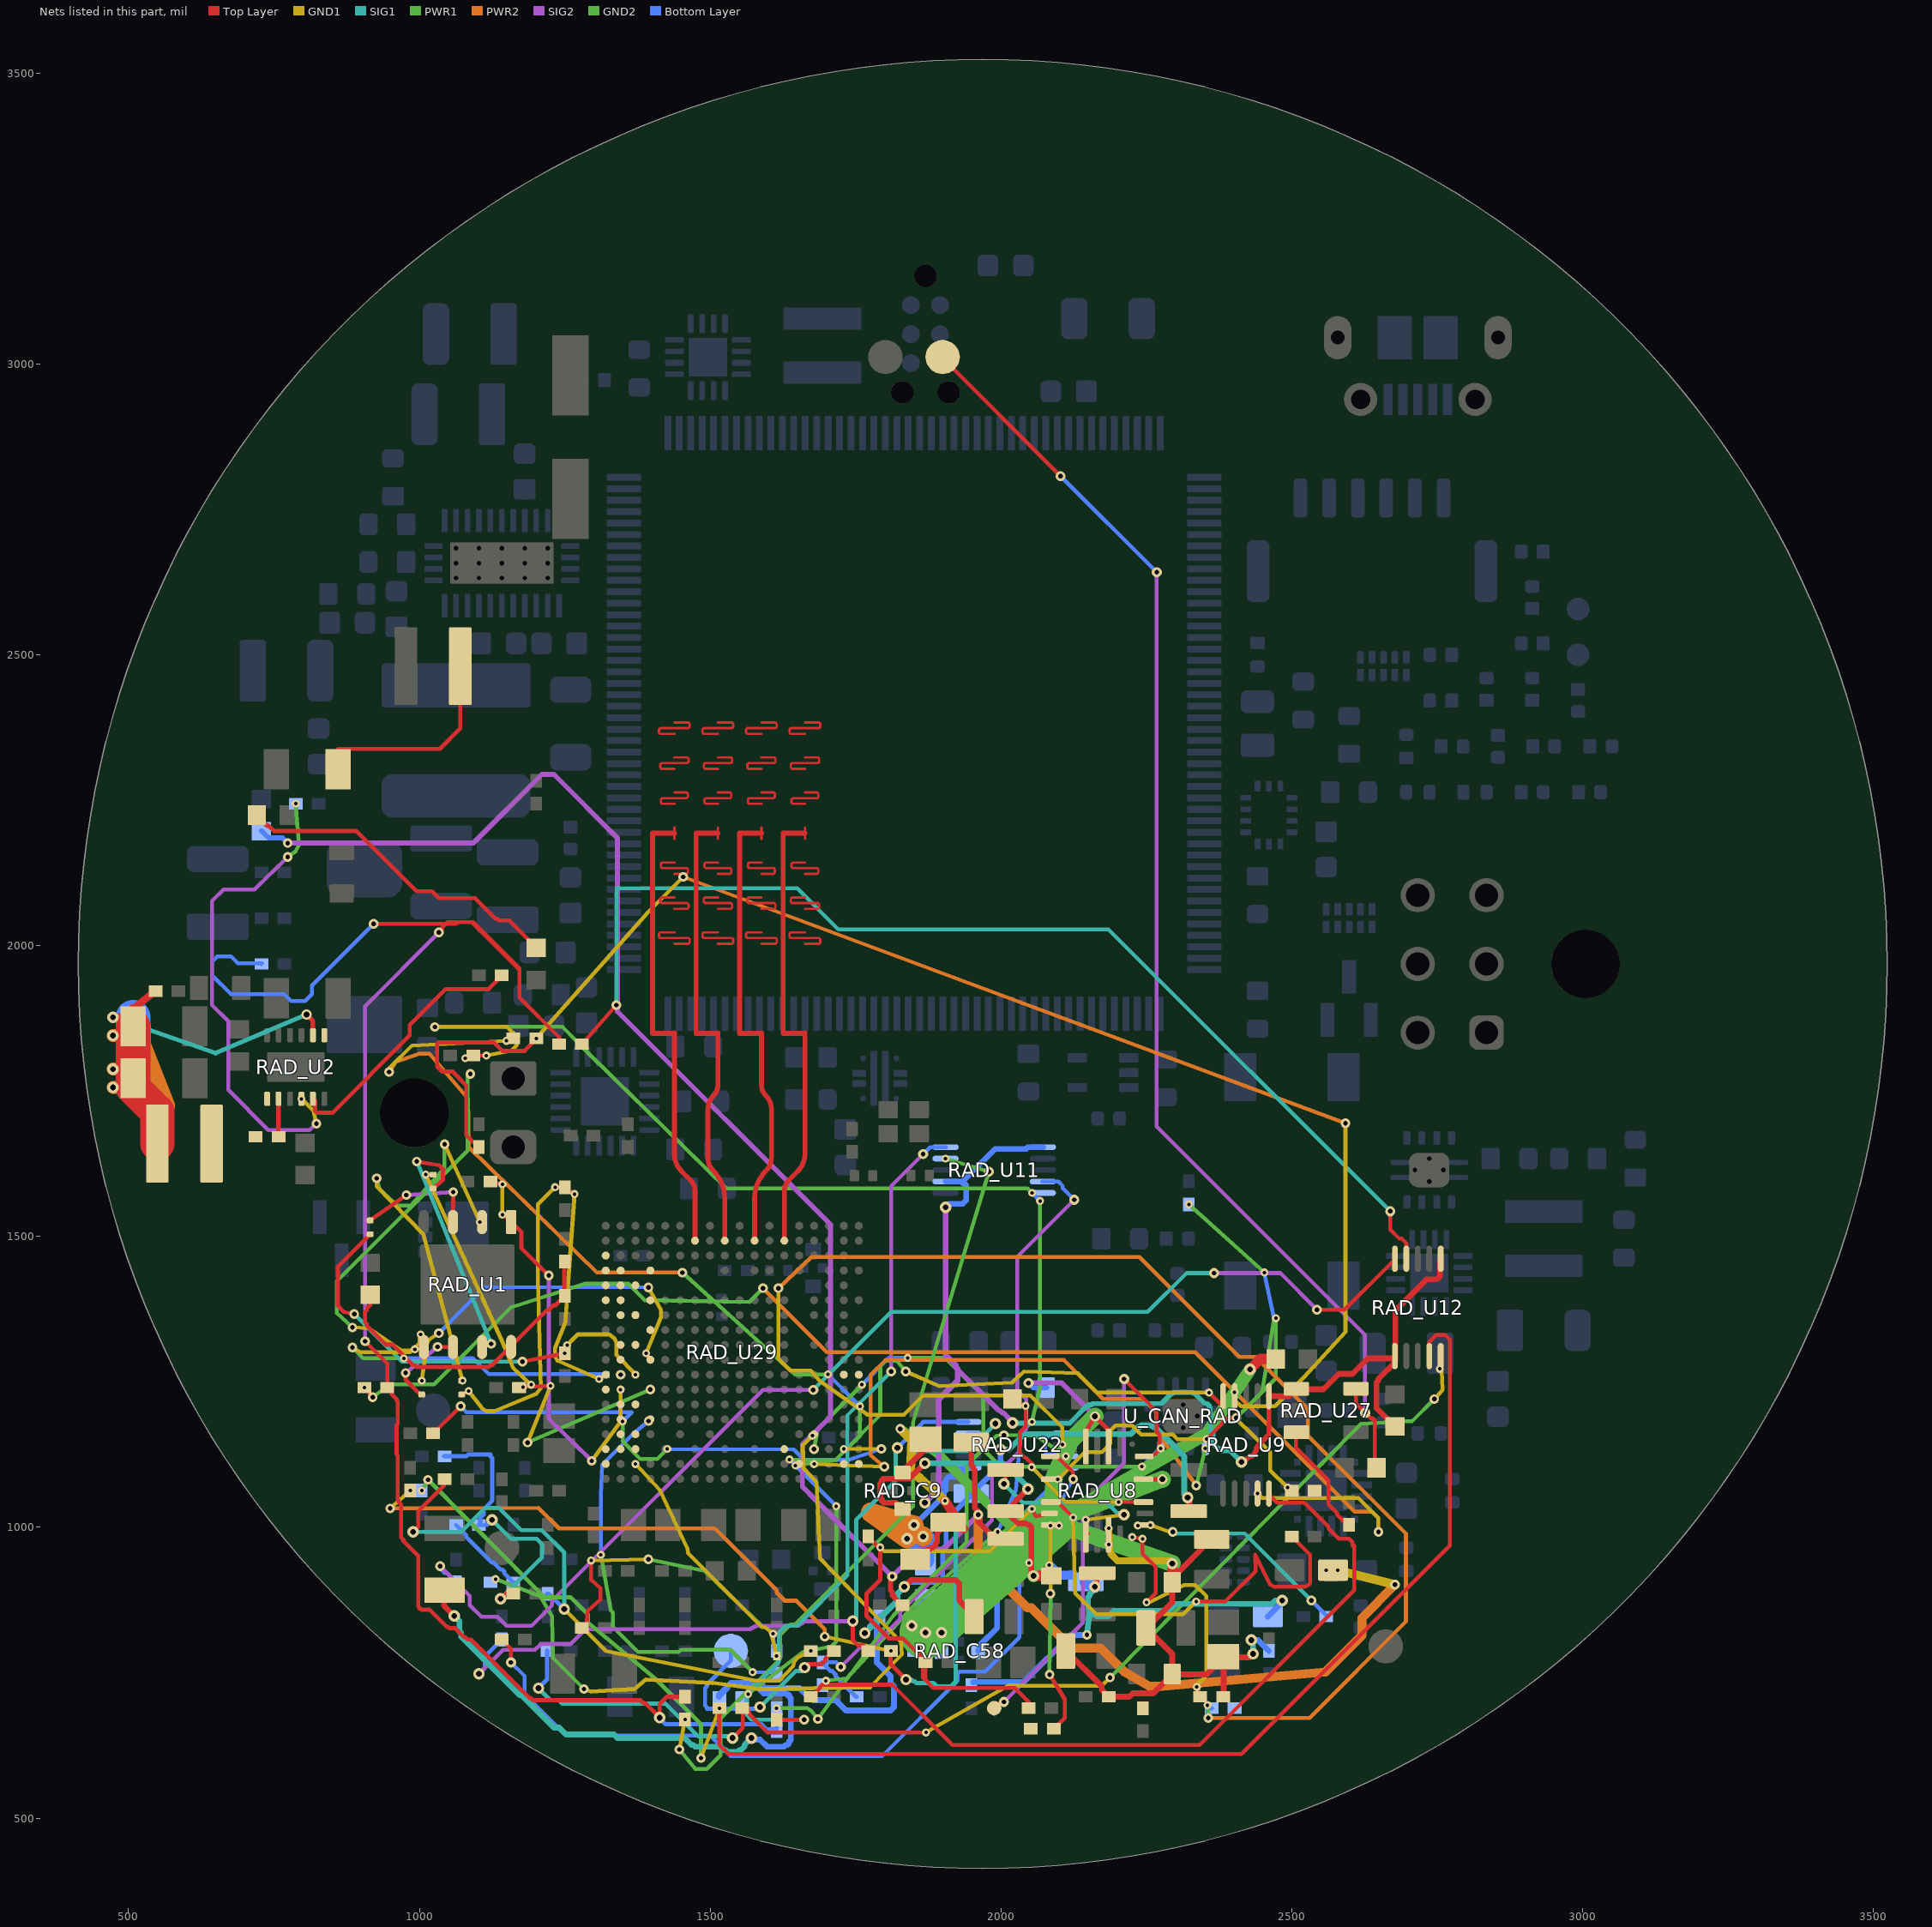
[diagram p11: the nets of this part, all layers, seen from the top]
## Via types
v1: diameter 13.77, hole 5.9, Top Layer to GND1, tented both sides, 513 vias
v2: diameter 19.68, hole 9.84, Top Layer to Bottom Layer, tented both sides, 196 vias
v3: diameter 16.54, hole 7.87, Top Layer to Bottom Layer, tented both sides, 129 vias
v4: diameter 13.77, hole 5.9, Top Layer to GND1, tented top, 104 vias
v5: diameter 13.78, hole 5.91, Top Layer to GND1, tented both sides, 83 vias
v6: diameter 17.32, hole 7.87, Top Layer to Bottom Layer, tented both sides, 69 vias
v7: diameter 13.78, hole 5.91, GND2 to Bottom Layer, tented both sides, 68 vias
v8: diameter 13.78, hole 5.91, Top Layer to GND1, tented bottom, 55 vias
v9: diameter 13.78, hole 5.91, GND2 to Bottom Layer, tented top, 43 vias
v10: diameter 22.05, hole 11.81, Top Layer to Bottom Layer, tented both sides, 23 vias
v11: diameter 16.54, hole 7.87, GND2 to Bottom Layer, tented both sides, 22 vias
v12: diameter 16.54, hole 7.87, Top Layer to Bottom Layer, 14 vias
v13: diameter 22.83, hole 11.81, Top Layer to Bottom Layer, tented both sides, 11 vias
v14: diameter 18.11, hole 9.06, Top Layer to Bottom Layer, tented both sides, 8 vias
v15: diameter 19.68, hole 7.87, Top Layer to Bottom Layer, 3 vias
v16: diameter 17.32, hole 8.66, Top Layer to Bottom Layer, tented both sides, 3 vias
v17: diameter 20.47, hole 9.84, Top Layer to Bottom Layer, tented both sides, 3 vias
v18: diameter 17.72, hole 9.84, Top Layer to Bottom Layer, tented both sides, 2 vias
v19: diameter 22.05, hole 11.02, Top Layer to Bottom Layer, tented both sides, 2 vias
v20: diameter 19.68, hole 11.81, Top Layer to Bottom Layer, tented both sides, 2 vias
v21: diameter 19.68, hole 9.84, SIG1 to Bottom Layer, tented both sides, 2 vias
v22: diameter 16.54, hole 7.87, SIG1 to SIG2, tented both sides, 2 vias
v23: diameter 16.54, hole 7.87, Top Layer to SIG1, 2 vias
v24: diameter 13.78, hole 5.91, Top Layer to GND1, 2 vias
v25: diameter 18, hole 9.84, Top Layer to Bottom Layer, tented both sides, 1 vias
v26: diameter 19.68, hole 9.84, GND2 to Bottom Layer, tented both sides, 1 vias
v27: diameter 17.32, hole 7.87, SIG1 to Bottom Layer, tented both sides, 1 vias
v28: diameter 19.68, hole 9.84, SIG2 to Bottom Layer, tented both sides, 1 vias
v29: diameter 16.54, hole 7.87, PWR2 to GND1, tented both sides, 1 vias

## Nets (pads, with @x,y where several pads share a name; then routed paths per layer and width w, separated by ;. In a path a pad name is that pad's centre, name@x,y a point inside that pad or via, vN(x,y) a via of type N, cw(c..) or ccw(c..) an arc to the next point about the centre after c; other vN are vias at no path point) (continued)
TI_MSS_I2CA_SDA: RAD_R29.2 RAD_R35.2 RAD_R59.2 RAD_R62.2 RAD_R277.1 | length 3308.9
  Top Layer w6.3: v3(906.5,1319.88) 944.88,1281.5 RAD_R29.2@944.88,1240.16 ; v3(1033.46,2022.64) 1039.37,2028.54 1039.37,2031.5 1048.23,2040.35 1089.57,2040.35 1172.24,1957.68 1172.24,1910.43 1240.16,1842.52 RAD_R59.2@1240.16,1830.71
  Top Layer w6.69: v6(921.26,2037.4) 1062.99,2037.4 1065.94,2040.35 1092.52,2040.35 1172.24,1960.63 1172.24,1910.43 1240.16,1842.52 RAD_R59.2@1240.16,1830.71
  Top Layer w7.09: RAD_R29.2@944.88,1240.16 952.76,1232.28 952.76,1228.35 960.63,1220.47 960.63,1218.5 962.6,1216.54 962.6,1177.17 960.63,1175.2 960.63,1125.98 962.6,1124.02 962.6,1047.24 964.57,1045.28 964.57,1043.31 968.5,1039.37 968.5,982.28 972.44,978.35 972.44,976.38 998.03,950.79 998.03,864.17 1000,862.2 1000,860.24 1001.97,860.24 1003.94,858.27 1017.72,858.27 1047.24,828.74 1049.21,828.74 1051.18,826.77 1061.02,826.77 1076.77,811.02 1078.74,811.02 1082.68,807.09 1088.58,807.09 1188.98,706.69 1190.94,706.69 1194.88,702.76 1379.92,702.76 1383.86,698.82 1385.83,698.82 1387.8,696.85 1389.76,696.85 1413.39,673.23 v2(1413,672.68) 1413,696.16 1425.5,708.66 RAD_R35.2@1456.69,708.66
  SIG2 w6.3: v3(906.5,1319.88) 906.5,1895.67 v3(1033.46,2022.64)
  Bottom Layer w6.69: RAD_R277.1@728.35,1968.5 729.33,1969.49 687.99,1969.49 676.18,1981.3 652.56,1981.3 643.7,1972.44 643.7,1948.82 676.18,1916.34 767.72,1916.34 779.53,1904.53 803.15,1904.53 814.96,1916.34 814.96,1931.1 v6(921.26,2037.4)
  Bottom Layer w7.09: v2(1413,672.68) 1414.37,673.23 1417.32,670.28 1417.32,667.32 1423.23,661.42 1588.58,661.42 1597.44,652.56 1612.2,652.56 1615.16,649.61 RAD_R62.2@1614.17,649.61 1614.17,663.59 1613,664.76
TI_MSS_MCANA_RX: RAD_U29.D16 U_CAN_RAD.4 | length 818.4
  GND2 w6.69: v12(1678.57,1134.44) 1685.04,1169.29 v7(1760.83,1245.08) ; v7(1839.57,1291.34) 1903.54,1291.34 1969.49,1225.39 1969.49,1133.86 1999.02,1104.33 v7(2242.13,1104.33)
  Bottom Layer w6.69: v7(1760.83,1245.08) 1807.09,1291.34 v7(1839.57,1291.34) ; v7(2242.13,1104.33) U_CAN_RAD.4@2273.23,1135.83
  other v9: 2274.61,1135.83
TI_MSS_MCANA_TX: RAD_U29.D17 U_CAN_RAD.1 | length 1042.8
  PWR2 w6.69: v3(1799.21,1104.33) 1775.59,1124.02 1775.59,1261.81 1801.18,1287.4 2108.27,1287.4 2175.2,1220.47 2244.09,1220.47 2267.72,1196.85 2267.72,1163.39 v3(2335.63,1071.85)
  GND1 w6.69: v8(1678.57,1108.85) v3(1799.21,1104.33)
  GND2 w6.69: v3(2335.63,1071.85) v9(2351.38,1135.83)
TI_MSS_MCANB_RX: RAD_U29.A17
TI_MSS_MCANB_TX: RAD_U29.B17
TI_MSS_MDIO_CLK: RAD_U29.R4
TI_MSS_MDIO_DATA: RAD_U29.T5
TI_MSS_RGMII_RCLK: RAD_U29.T9
TI_MSS_RGMII_RCTL: RAD_U29.T7
TI_MSS_RGMII_RD0: RAD_U29.V6
TI_MSS_RGMII_RD1: RAD_U29.V4
TI_MSS_RGMII_RD2: RAD_U29.V5
TI_MSS_RGMII_RD3: RAD_U29.U10
TI_MSS_RGMII_TCLK: RAD_U29.V3
TI_MSS_RGMII_TCTL: RAD_U29.R6
TI_MSS_RGMII_TD0: RAD_U29.U7
TI_MSS_RGMII_TD1: RAD_U29.U5
TI_MSS_RGMII_TD2: RAD_U29.U6
TI_MSS_RGMII_TD3: RAD_U29.U4
TI_MSS_RS232RX: RAD_U29.F16
TI_MSS_RS232TX: RAD_U29.E17
TI_MSS_SPIA_CLK: RAD_U29.T16
TI_MSS_SPIA_CS0: RAD_U29.T15
TI_MSS_SPIA_HOSTIRQ: RAD_U29.V17
TI_MSS_SPIA_MOSI: RAD_U29.U15
TI_MSS_SPIB_CS0: RAD_U29.U14
TI_MSS_SPIB_CS1: RAD_U29.V16
TI_MSS_SPIB_MISO: RAD_U29.U13
TI_MSS_UARTA_RX: RAD_R129.1 RAD_U29.B16 | length 962.1
  Top Layer w6.69: RAD_R129.1@1023.62,1161.42 1024.02,1161.22 v12(1070.87,1208.07)
  GND1 w6.3: v8(1729.75,1134.44) v12(1794.29,1134.84)
  GND2 w6.69: v7(1349.41,1182.09) 1349.41,1147.64 1379.92,1117.13 1408.46,1117.13 v7(1426.18,1134.84)
  Bottom Layer w6.69: v12(1070.87,1208.07) 1080.91,1198.03 1365.35,1198.03 v7(1349.41,1182.09) ; v7(1426.18,1134.84) 1428.94,1134.45 1643.7,1133.86 1661.42,1116.14 1738.19,1116.14 v12(1794.29,1134.84)
TI_NERR_MCU: RAD_R76.2 RAD_U8.16 | length 388.5
  Top Layer w6.69: v5(2235.24,1002.95) 2246.08,1003.34 v5(2257.09,1003.74) ; RAD_U8.16@2246.06,1003.94 RAD_U8.16@2247.05,1003.94
  GND1 w6.69: v5(2257.09,1003.74) v3@2297.64,988.98
  SIG1 w6.69: v3@2297.64,988.98 2418.9,988.98 v6(2533.46,874.02)
  Bottom Layer w6.69: v6(2533.46,874.02) 2560.04,847.44 RAD_R76.2@2559.06,846.46
  other v3: 2295.28,992.13
TI_NetC1_2: RAD_C1.2 RAD_C2.2 RAD_R37.2 RAD_U1.8 | length 540
  Top Layer w7.09: RAD_C1.2@915.35,1399.61 915.35,1381.89 909.45,1375.98 909.45,1373.03 906.5,1370.08 906.5,1352.36 909.45,1349.41 909.45,1346.46 941.93,1313.98 953.74,1313.98 989.17,1278.54 992.13,1278.54 995.08,1275.59 1119.09,1275.59 1122.05,1278.54 1125,1278.54 RAD_U1.8@1157.48,1311.02 ; RAD_U1.8@1157.68,1309.98 RAD_U1.8@1157.48,1311.02 ; RAD_C2.2@1250,1397.64 RAD_C2.2@1249.02,1396.65 ; RAD_R37.2@1250,1456.69 1249.02,1455.71 RAD_C2.2@1249.02,1396.65 ; RAD_U1.8@1157.48,1311.02 1219.49,1373.03 1222.44,1373.03 1231.3,1381.89 1234.25,1381.89 RAD_C2.2@1249.02,1396.65
TI_NetC14_1: RAD_C14.1 RAD_R26.2 RAD_U9.9 | length 2626
  Top Layer w6.69: RAD_U9.9@2401.57,1225.39 v8(2401.57,1232.28)
  Top Layer w7.09: RAD_R26.2@1102.36,1653.54 1101.38,1653.54 1080.71,1674.21 1080.71,1759.84 1057.09,1783.46 1039.37,1783.46 1030.51,1792.32 1030.51,1830.71 1033.46,1833.66 1127.95,1833.66 1142.72,1818.9 1181.1,1818.9 1201.77,1839.57 v8(1200.79,1840.55)
  PWR2 w6.69: v29(1453.54,2118.11) v3(2592.13,1694.49)
  GND1 w6.69: v8(1200.79,1840.55) 1392.13,2056.69 v29(1453.54,2118.11) ; v8(2401.57,1232.28) 2401.57,1218.9 2412.6,1207.87 2470.87,1207.87 2521.26,1258.27 2592.13,1335.43 v3(2592.13,1694.49)
TI_NetC14_2: RAD_C14.2 RAD_R32.2 RAD_U9.10 | length 3012.8
  Top Layer w6.69: v5(1149.61,1836.22) RAD_C14.2@1168.5,1835.43 ; v5(2357.48,1231.5) 2381.69,1207.48 RAD_U9.10@2381.69,1225.39
  PWR2 w6.69: v3(948.03,1782.68) 959.06,1800 1000,1814.17 1017.32,1814.17 1083.46,1737.01 1085.04,1653.54 1305.51,1437.8 v3(1451.97,1437.8)
  GND1 w6.69: v3(948.03,1782.68) 948.03,1788.98 987.4,1828.35 v5(1149.61,1836.22) ; v3(1836.22,1267.72) 1894.49,1242.52 2018.9,1248.82 2039.37,1267.72 2132.28,1264.57 2165.35,1231.5 v5(2357.48,1231.5)
  GND2 w6.69: v3(1451.97,1437.8) 1645.67,1262.99 v7(1702.36,1262.99) ; v9(1565.35,713.39) 1659.84,785.83 1708.66,795.28 1716.54,803.15 v7(1716.54,1036.22) ; v7(1636.22,1116.54) 1674.02,1114.96 1714.96,1114.96 1757.48,1157.48 v7(1757.48,1207.87) ; v7(1646.65,1106.3) 1715.55,1116.14 1792.32,1192.91 1792.32,1277.56 1801.57,1286.61 1820.47,1286.61 v3(1836.22,1267.72)
  Bottom Layer w6.69: RAD_R32.2@1562.2,713.78 v9(1565.35,713.39) ; v7(1646.65,1106.3) v7(1636.22,1116.54) v7(1716.54,1036.22) ; v7(1702.36,1262.99) v7(1757.48,1207.87)
TI_NetC17_1: RAD_C17.1 RAD_R47.2 RAD_U11.9 | length 1192.1
  SIG2 w6.69: v6(1724.41,759.84) 1759.84,795.28 1779.53,795.28 1826.77,842.52 1826.77,854.33 1984.25,1011.81 1984.25,1090.55 2003.94,1110.24 2011.81,1110.24 2031.5,1129.92 2031.5,1157.48 2043.31,1169.29 2043.31,1220.47 2027.56,1236.22 2027.56,1464.57 v6(2125.98,1562.99)
  Bottom Layer w6.69: RAD_C17.1@1692.91,767.72 1716.54,767.72 v6(1724.41,759.84) ; RAD_U11.9@2071.85,1594.49 2070.87,1594.49 2098.43,1594.49 2106.3,1586.61 2106.3,1582.68 v6(2125.98,1562.99)
  Bottom Layer w7.09: RAD_C17.1@1692.91,767.72 1691.93,767.72 1706.69,752.95 1709.65,752.95 1715.55,747.05 1715.55,744.09 1750.98,708.66 RAD_R47.2@1751.97,708.66
TI_NetC17_2: RAD_C17.2 RAD_R65.2 RAD_U11.10 | length 2403.8
  Top Layer w6.69: v5(1078.74,1806.3) RAD_R65.2@1099.61,1805.91 ; RAD_R65.2@1099.61,1811.02 v5(1115.16,1811.02)
  GND1 w6.69: v3(1026.57,1860.24) 1150.59,1860.24 1167.32,1843.5 1167.32,1828.74 1157.48,1818.9 v5(1115.16,1811.02)
  GND2 w6.69: v3(1026.57,1860.24) 1246.06,1860.24 1292.91,1812.6 1527.56,1582.68 2045.67,1582.68 v9(2053.54,1574.8) ; v9(1698.82,736.22) 1734.25,740.16 1856.3,872.05 v7(1994.09,992.13) ; v7(2053.15,1181.1) 2066.93,1240.16 v7(2066.93,1561.02)
  Bottom Layer w6.69: RAD_C17.2@1698.03,735.43 v9(1698.82,736.22) ; v7(1994.09,992.13) 2025.59,1064.96 2033.46,1161.42 v7(2053.15,1181.1) ; v9(2053.54,1574.8) RAD_U11.10@2053.94,1575 ; RAD_U11.10@2053.94,1574.61 v7(2066.93,1561.02)
TI_NetC19_1: RAD_C19.1 RAD_R348.2 RAD_U12.9 | length 2714.4
  Top Layer w6.69: v8(1515.75,688.98) 1515.75,625.98 1531.5,610.24 2413.39,610.24 2771.65,968.5 2771.65,1322.83 2763.78,1330.71 2748.03,1330.71 2736.22,1318.9 2736.22,1295.28 RAD_U12.9@2736.22,1294.29
  PWR1 w7.09: v3(1014.76,1081.69) 1214.57,879.92 1259.84,879.92 1289.37,850.39 1289.37,836.61 1407.48,738.19 1484.25,661.42 v3(1484.25,603.35)
  GND1 w6.69: v3(1484.25,603.35) v8(1515.75,688.98)
  GND2 w6.69: v9(1003.94,1062.99) v3(1014.76,1081.69)
TI_NetC19_2: RAD_C19.2 RAD_R352.2 RAD_U12.10 | length 1995.2
  Top Layer w6.69: RAD_C19.2@1562.2,694.09 1568.5,677.17 1598.43,647.24 v5(1870.87,647.24) ; v8(2754.33,1272.44) RAD_U12.10@2755.71,1276.38
  Top Layer w7.09: v2(1538.39,637.8) 1556.1,655.51 1556.1,687.99 RAD_C19.2@1555.12,688.98
  PWR1 w6.69: v3(2187.4,741.73) 2618.9,1177.95 2707.09,1182.68 v3(2744.88,1220.47)
  GND1 w6.69: v5(1870.87,647.24) 2012.6,727.56 2173.23,727.56 v3(2187.4,741.73) ; v3(2744.88,1220.47) 2759.06,1236.22 2757.48,1269.29 v8(2754.33,1272.44)
  SIG1 w7.09: v2(1204.72,723.43) 1225.39,702.76 1240.16,702.76 1246.06,696.85 1423.23,696.85 1479.33,640.75 1535.43,640.75 v2(1538.39,637.8)
  Bottom Layer w7.09: v2(1204.72,723.43) 1219.49,738.19 1219.49,788.39 RAD_R352.2@1220.47,787.4
TI_NetC21_1: RAD_C21.1 RAD_U2.2 | length 65.2
  Top Layer w8: RAD_C21.1@757.87,1671.39 RAD_U2.2@757.87,1736.61
TI_NetC21_2: RAD_C21.2 RAD_L6.1 RAD_U2.1
TI_NetC81_1: RAD_C81.1 RAD_R56.2 RAD_U22.9 | length 1806.5
  Top Layer w7.09: v8(1811.02,787.4) 1810.04,788.39 1810.04,764.76 v2(1836.61,738.19)
  PWR2 w7.09: v3(949.8,1032.48) 1204.72,1033.46 1240.16,998.03 1507.87,998.03 1614.17,891.73 1614.17,887.8 1627.95,874.02 1647.64,874.02 1696.85,824.8 v3(1696.85,812.01)
  GND1 w6.69: v3(949.8,1032.48) v8(984.25,1062.99) ; v3(1696.85,812.01) v8(1811.02,787.4)
  SIG1 w7.09: v2(1836.61,738.19) 1845.47,738.19 1848.43,735.24 1851.38,735.24 1854.33,732.28 1883.86,732.28 1889.76,726.38 1913.39,726.38 1922.24,735.24 1922.24,1024.61 1848.43,1098.43 1848.43,1122.05 1857.28,1130.91 1942.91,1130.91 v2(1990.16,1178.15)
  Bottom Layer w7.09: RAD_U22.9@1943.9,1161.42 1942.91,1160.43 1972.44,1160.43 v2(1990.16,1178.15)
TI_NetC81_2: RAD_C81.2 RAD_R66.2 RAD_U22.10 | length 1295.4
  Top Layer w7.09: v2(1745.08,838.58) 1745.08,806.1 1753.94,797.24 1762.8,797.24 1771.65,788.39 RAD_C81.2@1771.65,787.4
  SIG1 w7.09: v2(1745.08,838.58) 1750.98,844.49 1750.98,1012.8 1818.9,1080.71 1818.9,1133.86 v2(1821.85,1136.81)
  SIG2 w7.09: v2(1102.36,748.03) 1143.7,789.37 1198.82,789.37 1208.66,799.21 1259.84,799.21 1285.43,824.8 1568.9,824.8 1570.87,826.77 1572.83,826.77 1574.8,828.74 1576.77,828.74 1578.74,830.71 1651.57,830.71 1655.51,834.65 1657.48,834.65 1661.42,838.58 1746.06,838.58 v2(1745.08,838.58)
  Bottom Layer w7.09: v2(1102.36,748.03) 1112.2,757.87 1112.2,777.56 RAD_R66.2@1141.73,807.09 ; v2(1821.85,1136.81) 1866.14,1181.1 1942.91,1181.1 RAD_U22.10@1943.9,1181.1
TI_NetC100_1: RAD_C100.1 RAD_L5.1 | length 366.7
  Top Layer w7.09: RAD_C100.1@860.24,2303.15 860.24,2338.24 1035.24,2338.24 1070.28,2373.28 RAD_L5.1@1070.28,2480.32
TI_NetC104_1: RAD_C104.1 RAD_C126.1 | length 577.4
  Top Layer w7.09: RAD_C104.1@720.47,2224.41 720.47,2223.43 738.19,2205.71 741.14,2205.71 750,2196.85 891.73,2196.85 995.08,2093.5 1021.65,2093.5 1033.46,2081.69 1095.47,2081.69 1130.91,2046.26 1133.86,2046.26 1136.81,2043.31 1154.53,2043.31 1201.77,1996.06 RAD_C126.1@1200.79,1996.06
TI_NetC123_2: RAD_C123.2 RAD_U8.18 | length 362
  Top Layer w6.69: RAD_C123.2@2019.69,1220.47 v5(2042.32,1208.66) 2042.32,1173.23 2032.48,1163.39 2032.48,1127.95 2040.35,1120.08 2043.31,1119.09 2052.66,1110.24 v5(2052.66,1103.35) ; v5(2202.26,1043.31) RAD_U8.18@2233.07,1043.5
  Top Layer w7.09: RAD_U8.18@2233.07,1043.5 2233.07,1043.31 RAD_U8.18@2245.08,1043.31
  GND1 w6.69: v5(2052.66,1103.35) 2110.24,1044.09 v5(2202.26,1043.31)
TI_NetC149_2: RAD_C149.2 RAD_P1.2 RAD_U27.5 | length 2326.3
  Top Layer w6.69: RAD_P1.2@1899.61,3011.81 1897.64,3011.81 v6(2102.36,2807.09) ; RAD_U27.5@2610.24,1238.19 2610.24,1240.16 2610.24,1212.6 v6(2625.98,1196.85)
  Top Layer w7.09: RAD_U27.5@2610.24,1238.19 2610.24,1237.2 2610.24,1213.58 2636.81,1187.01 2639.76,1187.01 2639.76,1184.06 2642.72,1184.06 2642.72,1104.33 2645.67,1101.38 RAD_C149.2@2645.67,1102.36
  SIG2 w6.69: v6(2267.72,2641.73) 2267.72,1688.98 2625.98,1330.71 v6(2625.98,1196.85)
  Bottom Layer w6.69: v6(2102.36,2807.09) v6(2267.72,2641.73)
TI_NetJ17_1: RAD_R300.2 TP_RAD_FLASH.1 | length 383.7
  Top Layer w7.09: v2(1662.4,758.86) 1668.31,764.76 1691.93,764.76 1697.83,770.67 1697.83,773.62 1712.6,788.39 RAD_R300.2@1712.6,787.4
  SIG1 w7.09: v2(1585.63,690.94) 1647.64,752.95 1656.5,752.95 v2(1662.4,758.86)
  Bottom Layer w7.09: TP_RAD_FLASH.1@1535.43,787.4 1535.43,788.39 1535.43,770.67 1494.09,729.33 1494.09,726.38 1491.14,723.43 1491.14,693.9 1494.09,690.94 1494.09,687.99 1582.68,687.99 v2(1585.63,690.94)
TI_NetL1_1: RAD_L1.1 RAD_U8.11 | length 325.7
  Top Layer w7.09: v2(2004.92,1074.8) 2007.87,1077.76 RAD_L1.1@2007.87,1098.43 ; RAD_U8.11@2145.67,987.2 2146.65,986.22 RAD_U8.11@2149.61,989.17
  GND1 w7.09: v8(2145.67,1012.8) v2(2211.61,1021.65)
  SIG1 w7.09: v2(2004.92,1074.8) 2037.4,1042.32 2182.09,1042.32 2199.8,1024.61 2208.66,1024.61 v2(2211.61,1021.65)
TI_NetR1_1: RAD_R1.1 RAD_U2.5 | length 455.2
  Top Layer w7.09: RAD_U2.5@816.93,1736.61 817.91,1736.22 820.87,1733.27 820.87,1715.55 823.82,1712.6 850.39,1712.6 983.27,1845.47 983.27,1863.19 1045.28,1925.2 1119.09,1925.2 1142.72,1948.82 RAD_R1.1@1141.73,1948.82
TI_NetR2_2: RAD_R2.2 RAD_U2.4 | length 833.4
  GND1 w6.69: v8(797.24,1736.61) 817.91,1715.55 v3(822.83,1693.9)
  SIG2 w6.69: v3(773.62,2152.56) 716.54,2096.46 663.39,2096.46 643.7,2076.77 643.7,1897.64 671.26,1870.08 671.26,1751.97 740.16,1683.07 811.02,1683.07 v3(822.83,1693.9)
  GND2 w6.69: v3(773.62,2152.56) 787.4,2162.4 792.32,2171.26 792.32,2180.12 v9(787.4,2244.09)
TI_NetR3_2: RAD_U29.U9
TI_NetR4_2: RAD_U2.7
TI_NetR27_1: RAD_R27.1 RAD_U9.5 | length 1364.9
  Top Layer w6.69: RAD_R27.1@1673.23,708.66 1674.21,708.66 1688.98,723.43 1688.98,726.38 1691.93,729.33 1812.99,729.33 1916.34,625.98 2341.54,625.98 2607.28,891.73 2607.28,968.5 2604.33,968.5 2604.33,974.41 2598.43,980.32 2580.71,980.32 2562.99,998.03 2562.99,1000.98 2521.65,1042.32 2474.41,1042.32 2459.65,1057.09 RAD_U9.5@2460.63,1058.07
TI_NetR29_1: RAD_R29.1 RAD_U9.4 | length 2277.2
  Top Layer w6.69: v5(905.51,1240.16) v3(919.68,1223.62)
  PWR1 w6.69: v3(919.68,1223.62) 949.61,1245.67 1025.2,1245.67 1157.48,1377.95 1285.04,1418.9 1359.06,1418.9 1387.4,1390.55 1566.93,1387.4 v3(1590.55,1411.02)
  PWR2 w6.69: v3(1590.55,1411.02) 1700.79,1300.79 2333.86,1300.79 2607.87,1026.77 2637.8,1026.77 2648.82,1015.75 v3(2648.82,992.13)
  GND1 w6.69: v5(2440.94,1058.07) 2448.82,1050.39 2614.17,1050.39 2648.82,1015.75 v3(2648.82,992.13)
TI_NetR31_2: RAD_U29.R8
TI_NetR33_1: RAD_R33.1 RAD_U11.5 | length 1295.8
  Top Layer w6.69: RAD_R33.1@1614.17,669.29 v6(1661.42,669.29)
  SIG1 w6.69: v6(1661.42,669.29) 1570.87,669.29 1562.99,677.17 1562.99,712.6 1618.11,767.72 1618.11,818.9 1629.92,830.71 1649.61,830.71 1736.22,917.32 1736.22,1192.91 v6(1811.02,1267.72)
  SIG2 w6.69: v6(1811.02,1267.72) 1811.02,1586.61 v6(1866.14,1641.73)
  Bottom Layer w6.69: v6(1866.14,1641.73) 1877.95,1653.54 1905.51,1653.54 RAD_U11.5@1904.53,1653.54
TI_NetR35_1: RAD_R35.1 RAD_U11.4 | length 1390.7
  PWR1 w6.69: v3(1446.85,618.11) 1474.41,584.65 1494.09,584.65 1517.72,608.27 1517.72,671.26 1620.08,773.62 1620.08,814.96 1637.8,832.68 1645.67,832.68 1848.43,1035.43 1848.43,1179.13 v3(1979.33,1611.22)
  GND1 w6.69: v3(1446.85,618.11) v8(1456.69,669.29)
  GND2 w6.69: v9(1904.53,1633.86) v3(1979.33,1611.22)
TI_NetR57_1: RAD_R57.1 RAD_U22.5 | length 1421.9
  Top Layer w6.69: RAD_R57.1@1141.73,807.09 1157.48,791.34 v6(1157.48,767.72)
  Bottom Layer w6.69: v6(1157.48,767.72) 1181.1,744.09 1181.1,712.6 1251.97,641.73 1500,641.73 1535.43,606.3 1795.28,606.3 1925.2,736.22 1925.2,748.03 1929.13,751.97 1972.44,751.97 2031.5,811.02 2031.5,1015.75 2110.24,1094.49 2110.24,1102.36 RAD_U22.5@2111.22,1102.36
TI_NetR58_1: RAD_R58.1 RAD_U12.5 | length 2053.3
  Top Layer w6.69: v6(2543.31,1374.02) 2590.55,1374.02 2677.17,1460.63 RAD_U12.5@2677.17,1461.61
  SIG1 w6.69: v6(1677.17,1236.22) 1811.02,1370.08 2251.97,1370.08 2318.9,1437.01 v6(2366.14,1437.01)
  SIG2 w6.69: v6(1035.43,933.07) 1086.61,881.89 1086.61,866.14 1106.3,846.46 1133.86,846.46 1149.61,830.71 1192.91,830.71 1228.35,866.14 1228.35,874.02 1590.55,1236.22 v6(1677.17,1236.22) ; v6(2366.14,1437.01) 2480.32,1437.01 v6(2543.31,1374.02)
  Bottom Layer w6.69: v6(1035.43,933.07) 1035.43,929.13 1043.31,921.26 1047.24,921.26 RAD_R58.1@1062.99,905.51
TI_NetR59_1: RAD_R59.1 RAD_U12.4 | length 1948.1
  Top Layer w6.69: RAD_R59.1@1279.53,1830.71 v23(1338.58,1897.64) ; v6(2669.29,1543.31) 2669.29,1511.81 2685.04,1496.06 2688.98,1496.06 2696.85,1488.19 2696.85,1460.63 RAD_U12.4@2696.85,1461.61
  SIG1 w6.69: v23(1338.58,1897.64) 1338.58,2098.43 1649.61,2098.43 1720.47,2027.56 2185.04,2027.56 v6(2669.29,1543.31)
TI_NetR62_1: RAD_R62.1 RAD_U22.2 RAD_U22.4 | length 913.7
  PWR1 w6.69: v3(1685.04,670.28) 1814.96,848.43 1940.94,974.41 1940.94,1106.3 1992.13,1157.48 v3(2004.92,1158.46)
  GND2 w6.69: v9(1614.17,688.98) 1666.34,688.98 1673.23,685.04 v3(1685.04,670.28) ; v3(2004.92,1158.46) 2060.04,1157.48 v9(2111.22,1122.05)
  Bottom Layer w7.09: v9(2111.22,1122.05) 2108.27,1125 2081.69,1125 2075.79,1130.91 2075.79,1151.57 2078.74,1154.53 2078.74,1157.48 2108.27,1157.48 2111.22,1160.43 RAD_U22.2@2111.22,1161.42
TI_NetR63_1: RAD_R63.1 RAD_U8.1 | length 2624.5
  PWR2 w6.69: v3(1617.32,1411.02) 1674.02,1464.57 2237.8,1464.57 2409.45,1292.91 2437.8,1292.91 2527.56,1203.15 2527.56,1157.48 2696.06,988.98 2696.06,837.8 2530.71,672.44 v3(2356.3,672.24)
  GND1 w6.69: v3(1617.32,1411.02) 1617.32,1289.76 1637.8,1269.29 1672.44,1269.29 1689.76,1250.39 1770.08,1193.7 1833.07,1193.7 1866.14,1226.77 2050.39,1226.77 2105.51,1171.65 v5(2105.58,1142.22)
  GND2 w6.69: v7(2355.12,694.09) v3(2356.3,672.24)
  Bottom Layer w7.09: v7(2355.12,694.09) 2360.24,688.98 RAD_R63.1@2362.2,688.98
TI_NetR159_2: RAD_R409.1 RAD_U27.3 | length 200.1
  Top Layer w7.09: RAD_U27.3@2507.87,1163.39 2506.89,1163.39 2506.89,1136.81 2562.99,1080.71 2562.99,1039.37 2577.76,1024.61 2577.76,1021.65 2592.52,1006.89 2595.47,1006.89 RAD_R409.1@2598.43,1003.94
TI_NetR186_1: RAD_R186.1 RAD_U8.8 | length 380.3
  Top Layer w7.09: v3(2083.46,746.85) 2109.65,704.13 2109.65,672.44 RAD_R186.1@2090.55,653.54 ; RAD_U8.8@2084.65,1003.74 v5(2084.65,1002.95) v5(2099.41,1002.95)
  PWR1 w6.69: v3(2083.46,746.85) v3@2085.04,881.89
  GND1 w6.69: v5(2084.65,1002.95) v3@2085.04,881.89
  other v3: 2084.84,886.02
TI_NetR190_2: RAD_R190.2 RAD_R292.2 RAD_U8.4 | length 1204.4
  Top Layer w6.69: v5(2353.35,1151.57) 2389.76,1187.99 v12(2404.72,1188.19)
  Top Layer w7.09: RAD_U8.4@2085.63,1082.68 2097.52,1082.68 2097.84,1083 2098,1082.84 v5(2097.64,1082.48) ; v5(2492.91,1068.11) 2498.03,1062.99 RAD_R190.2@2500,1062.99
  GND1 w6.69: v5(2097.64,1082.48) 2143.7,1128.94 2173.23,1128.94 2187.99,1143.7 2187.99,1166.34 2196.85,1175.2 2225.39,1175.2 2241.14,1159.45 2295.28,1159.45 2303.15,1151.57 v5(2353.35,1151.57) ; v12@2404.72,1185.83 2462.99,1129.13 2462.99,1097.64 v5@2491.34,1069.29
  GND2 w6.69: v9(2322.83,1555.12) v7(2452.76,1437.99) ; v7@2469.49,1358.27 2448.82,1232.28 v12(2404.72,1188.19) 2472.44,1255.91 v7(2472.44,1359.25)
  Bottom Layer w6.69: v7(2452.76,1437.99) v7@2469.49,1358.27
TI_NetR193_1: RAD_R193.1 RAD_U8.2 | length 464.5
  Top Layer w6.69: RAD_U8.2@2095.67,1121.85 2124.02,1094.49 v3(2124.02,1082.68)
  GND2 w6: v9(1857.83,792.87) 1902.56,793.31 v7(2048.23,938.98)
  Bottom Layer w6: v7(2048.23,938.98) v3@2123.03,1081.69
  Bottom Layer w6.69: v3@2123.03,1081.69 v3(2124.02,1082.68)
TI_NetR298_1: RAD_R299.2 RAD_R300.1 RAD_R302.2 | length 1044.5
  Top Layer w7.09: v2(989.17,992.13) 998.03,1000.98 998.03,1027.56 1042.32,1071.85 1042.32,1083.66 RAD_R299.2@1043.31,1082.68
  GND1 w6.69: v2(1249.02,859.25) 1320.87,787.4 1574.8,737.2 1592.52,736.22 1619.09,736.22 1642.72,761.81 1643.7,767.72 1649.61,775.59 v8(1673.23,787.4)
  SIG1 w7.09: v2(989.17,992.13) 1071.85,992.13 1113.19,1033.46 1136.81,1033.46 1175.2,995.08 1210.63,995.08 1249.02,956.69 v2(1249.02,859.25)
  Bottom Layer w7.09: RAD_R302.2@1220.47,885.83 1219.49,885.83 1222.44,885.83 v2(1249.02,859.25)
TI_NetR304_1: RAD_R305.2 RAD_R307.2 | length 518.4
  Top Layer w6.69: RAD_R307.2@1286.61,821.65 1289.37,856.3 1311.02,875.98 1311.02,895.67 1295.28,909.45 v5(1295.28,942.91)
  GND1 w6.69: v5(1295.28,942.91) v3(1393.7,944.88)
  GND2 w6.69: v3(1393.7,944.88) 1490.16,925.2 1588.58,830.71 1598.43,826.77 v7(1608.27,816.93)
  Bottom Layer w6.69: v7(1608.27,816.93) RAD_R305.2@1609.06,794.49
TI_NetR308_1: RAD_R310.2 RAD_R311.1 RAD_R313.2 | length 494.2
  Top Layer w7.09: v2(1139.76,876.97) 1148.62,885.83 1160.43,885.83 RAD_R311.1@1161.42,885.83
  SIG1 w7.09: v2(1125,1012.8) 1157.48,980.32 1201.77,980.32 1210.63,971.46 1210.63,947.83 v2(1139.76,876.97)
  Bottom Layer w7.09: RAD_R313.2@1043.31,1122.05 1042.32,1122.05 1080.71,1122.05 1083.66,1125 1122.05,1125 1122.05,1122.05 1125,1119.09 1125,1045.28 1110.24,1030.51 1110.24,1021.65 1104.33,1015.75 1104.33,1006.89 RAD_R310.2@1101.38,1003.94 ; RAD_R310.2@1102.36,1003.94 RAD_R310.2@1101.38,1003.94 ; v2(1125,1012.8) 1116.14,1003.94 RAD_R310.2@1101.38,1003.94
TI_NetR380_2: RAD_U29.T13
TI_NetR381_2: RAD_U29.V12
TI_NetR386_2: RAD_R386.2 RAD_U29.D15 | length 1297.9
  Top Layer w6.69: v8(1675.69,1157.48) RAD_U29.D15@1676.41,1157.86
  GND1 w6.69: v3(1282.97,721.95) 1294.78,717.52 1370.08,721.95 1389.27,738.19 1504.43,732.28 1582.68,721.95 1774.61,724.9 1829.23,781 1827.76,803.15 1688.98,946.36 1683.07,1077.76 1660.93,1101.38 1659.45,1140.75 1662.4,1144.19 v8(1675.69,1157.48)
  GND2 w6.69: v9(1130.91,910.93) 1207.68,881.4 1228.35,845.96 1229.82,775.1 v3(1282.97,721.95)
  Bottom Layer w6.69: RAD_R386.2@1129.13,910.63 v9(1130.91,910.93)
TI_NetR392_2: RAD_U29.U16
TI_NetTP8_1: RAD_TP8.1 RAD_U8.22 | length 840.5
  Top Layer w6.69: RAD_TP8.1@1988.19,688.98 1987.2,687.99 1999.02,699.8 v6(2004.92,699.8) ; v6(2211.61,1254.92) 2267.72,1198.82 2267.72,1163.39 ; RAD_U8.22@2246.06,1122.05 2247.05,1122.05 RAD_U8.22@2252.95,1122.05 ; RAD_U8.22@2257.09,1122.24 2265.75,1126.97 2272.64,1133.86 2272.64,1158.46 2267.72,1163.39 ; 2270.67,1163.39 2267.72,1163.39
  SIG2 w6.69: v6(2004.92,699.8) 2140.75,835.63 2140.75,1039.37 2211.61,1110.24 v6(2211.61,1254.92)
TI_NRSTOUT: RAD_R99.2 RAD_U8.6 | length 786.5
  Top Layer w6.69: RAD_U8.6@2097.64,1043.11 v5(2124.02,1016.73) ; v5(2335.43,872.44) 2385.83,872.44 2437.8,924.41 2437.01,952.76 2462.6,901.57 2469.49,897.64 2522.64,897.64 2529.53,901.57 2531.5,904.53 2531.5,952.76 RAD_R99.2@2500,984.25
  Top Layer w7.09: RAD_U8.6@2085.63,1043.31 2097.64,1043.31 RAD_U8.6@2097.64,1043.11
  GND1 w6.69: v5(2124.02,1016.73) 2127.56,886.61 2163.78,850.39 2313.39,850.39 v5(2335.43,872.44)
TI_OSC_CLK_OUT_ETHERNET: RAD_U29.B11
TI_OSC_CLKTOP: RAD_U29.A11
TI_PMIC_CLK: RAD_R75.1
TI_PMIC_CLK_OUT: RAD_R218.1 RAD_U29.T17 | length 420.5
  GND1 w6.69: v8(1371.48,1108.85) 1413.39,1063.98 1460.63,963.58 1461.61,955.71 1588.58,828.74 1594.49,827.76 1602.36,821.85 1605.32,815.94 v8(1614.17,778.74)
TI_PMIC_EN: RAD_R125.1 RAD_U8.15 | length 438.2
  Top Layer w6.69: v5(2225.58,983.08) v5(2243.11,980.32) 2243.11,954.72 2265.75,932.09 2265.75,903.54 2265.75,886.81 v5(2250,871.06) ; v5(2336.61,725.39) RAD_R125.1@2342.52,708.66
  GND1 w6.69: v5@2251.97,869.29 2314.96,900.79 2333.86,900.79 2352.76,881.89 2352.76,744.88 v5@2335.43,727.56
TI_PMIC_NINT: RAD_R13.2 RAD_R17.2 RAD_R106.1 RAD_U8.7 | length 888.6
  Top Layer w6.69: v5(2053.15,1031.5) 2060.04,1018.7 RAD_U8.7@2083.17,1023.62
  Top Layer w7.09: RAD_R13.2@1771.65,984.25 1771.65,983.27 1786.42,968.5 1789.37,968.5 v5(1792.32,965.55) 1792.32,909.45 1768.7,885.83 1768.7,847.44 1807.09,809.06 1830.71,809.06 1866.14,773.62 1866.14,741.14 1869.09,738.19 1870.08,737.5 ; RAD_R106.1@1870.08,767.72 1870.08,737.5 ; RAD_R17.2@2047.24,688.98 2047.24,700 2023.32,723.92 1883.66,723.92 1870.08,737.5
  GND1 w6.69: v5(1792.32,965.55) 1798.43,959.06 1981.1,959.06 v5(2053.15,1031.5)
TI_PMIC_SPI_CLK: RAD_R63.2
TI_PMIC_SPI_CS0: RAD_R190.1
TI_PMIC_SPI_MISO: RAD_R193.2
TI_PMIC_SPI_MOSI: RAD_R186.2
TI_PMICOUT_1V0: RAD_C132.1 RAD_C134.1 RAD_L8.2 RAD_R71.2 RAD_R73.1 RAD_R111.1 | length 1452.9
  Top Layer w9.84: RAD_R111.1@1852.36,944.88 1851.38,944.88 1866.14,959.65 1872.05,959.65 1875,962.6 1877.95,962.6 1880.91,965.55 1883.86,965.55 1886.81,968.5 1886.81,971.46 1889.76,974.41 1889.76,989.17 1910.43,1009.84 RAD_C134.1@1909.45,1008.86 ; v2(2161.42,897.64) 2164.37,900.59 2164.37,921.26 RAD_L8.2@2165.35,921.26
  Top Layer w15.75: v5(1903.54,1045.28) RAD_C134.1@1935.24,997.34
  GND1 w15.75: v3(1826.77,1169.29) 1846.46,1149.61 1844.49,1096.46 1860.24,1084.65 v5(1903.54,1045.28)
  SIG1 w9.84: v3(2147.64,814.96) 2152.56,856.3 ; v2(2161.42,897.64) 2161.42,894.68 2152.56,885.83 2152.56,882.87 2149.61,879.92 2149.61,862.2 2152.56,859.25 2152.56,856.3 ; v2(2483.27,874.02) 2471.46,874.02 2465.55,868.11 2300.2,868.11 2288.39,856.3 2193.9,856.3 2185.04,847.44 2164.37,847.44 2161.42,850.39 2158.46,850.39 2152.56,856.3
  GND2 w15.75: v3(1826.77,1169.29) 1891.73,1125.98 v7(2082.68,935.04)
  Bottom Layer w9.84: RAD_R71.2@1952.36,733.86 2039.37,734.25 2120.08,814.96 v3(2147.64,814.96) ; RAD_R73.1@2458.66,846.46 2459.65,847.44 2477.36,865.16 2477.36,868.11 v2(2483.27,874.02)
  Bottom Layer w15.75: v7(2082.68,935.04) 2100.39,917.32 RAD_C132.1@2119.88,918.01
  Bottom Layer w21.65: RAD_C132.1@2145.67,906.5 v2(2161.42,897.64)
TI_PMICOUT_1V2: RAD_C129.1 RAD_C130.1 RAD_L2.2 RAD_R30.1 RAD_R32.1 RAD_R291.2 | length 2605.8
  Top Layer w9.84: RAD_R30.1@1043.31,891.73 1042.32,891.73 1042.32,865.16 v2(1060.04,847.44) ; v2(1833.66,897.64) 1845.47,909.45 1922.24,909.45 1928.15,903.54 1928.15,874.02 1954.72,847.44 RAD_C129.1@1953.74,846.46 ; v2(2320.87,1051.18) 2323.82,1048.23 2323.82,1027.56 RAD_L2.2@2322.83,1027.56
  SIG1 w9.84: v2(1060.04,847.44) 1068.9,838.58 1068.9,820.87 1071.85,817.91 1071.85,812.01 1172.24,711.61 1175.2,711.61 1231.3,655.51 1240.16,655.51 1251.97,643.7 1334.65,643.7 1340.55,637.8 1455.71,637.8 1467.52,625.98 1470.47,625.98 1473.43,623.03 1517.72,623.03 1523.62,617.13 1526.57,617.13 1529.53,614.17 1547.24,614.17 1550.2,617.13 1553.15,617.13 1559.06,623.03 1559.06,625.98 v2(1570.87,637.8) ; v2(1765.75,817.91) 1821.85,874.02 1821.85,885.83 v2(1833.66,897.64) ; v2(1999.02,1133.86) 2013.78,1133.86 2037.4,1157.48 2040.35,1157.48 2043.31,1160.43 2223.43,1160.43 2235.24,1172.24 2238.19,1172.24 2241.14,1175.2 2258.86,1175.2 2261.81,1172.24 2264.76,1172.24 2314.96,1122.05 2314.96,1057.09 v2(2320.87,1051.18)
  Bottom Layer w8.66: v2(1833.66,897.64) 1832.68,897.64 1840.55,905.51 1893.7,905.51 1895.67,907.48 1897.64,907.48 1899.61,909.45 1899.61,962.6 1905.51,968.5 1905.51,1011.81 1946.85,1053.15 1946.85,1055.12 RAD_C130.1@1948.82,1057.09
  Bottom Layer w9.84: RAD_R32.1@1515.75,708.66 RAD_R32.1@1514.76,708.66 ; v2(1570.87,637.8) 1573.82,634.84 1585.63,634.84 1597.44,623.03 1626.97,623.03 1629.92,625.98 1632.87,625.98 1635.83,628.94 1635.83,631.89 1638.78,634.84 1638.78,705.71 1635.83,708.66 1635.83,711.61 1632.87,711.61 1629.92,714.57 1591.54,714.57 1573.82,732.28 1535.43,732.28 ; v2(1765.75,817.91) 1774.61,826.77 1774.61,829.72 RAD_R291.2@1792.32,847.44 ; RAD_R291.2@1791.34,846.46 RAD_R291.2@1792.32,847.44 ; RAD_C130.1@1948.82,1058.07 1948.82,1057.09 1999.02,1107.28 v2(1999.02,1133.86) ; RAD_R32.1@1514.76,708.66 1529.53,723.43 1529.53,726.38 1535.43,732.28 ; RAD_R32.1@1514.76,708.66 1514.76,711.61 1535.43,732.28 ; 1535.43,732.28 1585.63,732.28 1594.49,723.43 1653.54,723.43 1671.26,705.71 1674.21,705.71 1677.17,702.76 1715.55,702.76 1733.27,685.04 1810.04,685.04 1815.94,690.94 1815.94,726.38 1810.04,732.28 1810.04,744.09 1786.42,767.72 1786.42,841.54 RAD_R291.2@1792.32,847.44
TI_PMICOUT_1V8: RAD_C60.1 RAD_C125.1 RAD_L9.2 RAD_R14.2 RAD_R104.1 | length 3793.3
  Top Layer w8.66: v6(1812.99,915.35) 1810.04,912.4 1810.04,891.73 1812.99,888.78 1812.99,882.87 1815.94,882.87 1815.94,879.92 1830.71,865.16 RAD_R14.2@1830.71,866.14 ; v6(1960.63,1021.65) 1960.63,1009.84 1963.58,1006.89
  Top Layer w9.84: RAD_C125.1@1948.82,1146.65 1948.82,1145.67 1948.82,1107.28 1951.77,1104.33 1951.77,1101.38 1954.72,1098.43 1954.72,1033.46 1963.58,1024.61 1963.58,1006.89 1981.3,989.17 1993.11,989.17 1999.02,983.27 2004.92,983.27 RAD_L9.2@2007.87,980.32
  Top Layer w15.75: v8(2559.06,926.18) RAD_R104.1@2570.87,926.18 v8(2578.74,926.18)
  PWR2 w15.75: v6(1960.63,1021.65) 1960.63,946.46 2045.67,861.42 2051.97,861.42 2121.26,792.13 2171.65,792.13 2212.6,751.18 2255.91,726.38 2271.65,726.38 2557.48,751.18 2620.47,814.17 2620.47,844.09 v12(2677.17,901.57)
  GND1 w15.75: v8(2559.06,926.18) v8(2578.74,926.18) v12(2677.17,901.57)
  SIG2 w8.66: v3(773.62,2176.18) 1092.52,2176.18 1210.63,2294.29 1231.3,2294.29 1340.55,2185.04 1340.55,1886.81 1706.69,1520.67 1706.69,1189.96 1683.07,1166.34 1658.46,1142.72 1658.46,1069.88 1683.07,1045.28 v6(1812.99,915.35) 1860.24,962.6 1901.57,962.6 v6(1960.63,1021.65)
  Bottom Layer w8.66: RAD_C60.1@728.35,2196.85 729.33,2196.85 741.14,2185.04 764.76,2185.04 v3(773.62,2176.18)
TI_PVIN3V3: RAD_C3.2 RAD_C6.2 RAD_C8.2 RAD_C9.1 RAD_C9.3 RAD_C15.1 RAD_C31.1 RAD_C58.1 RAD_C58.3 RAD_C143.1 RAD_C144.2 RAD_C153.2 RAD_C199.1 RAD_C200.1 RAD_C201.1 RAD_C202.1 RAD_L1.2 RAD_R125.2 RAD_R200.2 RAD_U8.13 RAD_U8.20 RAD_U8.25 RAD_U8.27 | length 4074.2
  Top Layer w7.48: RAD_U8.27@2145.67,1138.78 2145.67,1164.37 v18(2161.42,1190.75) 2185.04,1167.13 RAD_U8.25@2185.04,1138.78 ; RAD_U8.20@2245.08,1082.68 v18(2277.36,1082.68)
  Top Layer w9.84: RAD_C9.1@1830.71,1031.5 1830.71,1030.51 1818.9,1042.32 1798.23,1042.32 1795.28,1045.28 1795.28,1048.23 1792.32,1051.18 1792.32,1074.8 1795.28,1077.76 1795.28,1080.71 1798.23,1083.66 ; RAD_C9.3@1830.71,1094.49 RAD_C9.3@1830.71,1095.47 ; v2(1869.09,1110.24) 1842.52,1083.66 1798.23,1083.66 ; RAD_C15.1@1870.08,1151.57 1869.09,1151.57 1866.14,1148.62 1866.14,1130.91 RAD_C9.3@1830.71,1095.47 ; v2(2046.26,1065.94) RAD_L1.2@2007.87,1027.56 2028.54,1006.89 2043.31,1006.89 2046.26,1003.94 2049.21,1003.94 2052.17,1000.98 2052.17,918.31 2055.12,915.35 v2(2055.91,916.54) ; RAD_C202.1@2111.22,787.4 2111.22,788.39 2173.23,726.38 2173.23,720.47 RAD_C200.1@2185.04,708.66 2220.47,708.66 2226.38,714.57 2261.81,714.57 RAD_C153.2@2294.29,747.05 ; RAD_C201.1@2249.02,826.77 RAD_C201.1@2250,826.77 ; RAD_C153.2@2294.29,748.03 RAD_C153.2@2294.29,747.05 ; RAD_C6.2@2294.29,905.51 RAD_C6.2@2294.29,906.5 ; RAD_C143.1@2362.2,979.33 2362.2,980.32 2294.29,912.4 RAD_C6.2@2294.29,906.5 ; RAD_R125.2@2381.89,708.66 2382.87,708.66 RAD_C31.1@2382.87,776.57 ; RAD_C31.1@2381.89,777.56 RAD_C31.1@2382.87,776.57 ; v2(2433.07,782.48) 2427.17,776.57 RAD_C31.1@2382.87,776.57 ; 1798.23,1083.66 1818.9,1083.66 RAD_C9.3@1830.71,1095.47 ; RAD_C201.1@2250,826.77 2294.29,782.48 RAD_C153.2@2294.29,747.05 ; RAD_C201.1@2250,826.77 2294.29,871.06 RAD_C6.2@2294.29,906.5 ; RAD_C153.2@2294.29,747.05 2353.35,747.05 RAD_C31.1@2382.87,776.57
  Top Layer w17.72: v2(2055.91,916.54) RAD_C8.2@2086.61,916.34 ; RAD_C6.2@2294.29,905.51 v2(2294.29,937.8) ; v2(2428.35,1271.65) 2446.06,1289.37 RAD_C3.2@2472.44,1289.37
  PWR1 w21.65: v2(2055.91,916.54) 2086.61,1009.84 2354.33,1161.42 v2(2428.35,1271.65)
  PWR1 w29.53: v18(2161.42,1190.75) 2119.09,1148.62 2091.54,1087.6 2086.61,1009.84 ; v18(2277.36,1082.68) 2086.61,1009.84 ; v2(2294.29,937.8) 2086.61,1009.84
  PWR1 w33.46: v2(1846.46,830.71) v2(1870.08,818.9) v2(1897.64,818.9)
  PWR1 w88.58: v2(1870.08,818.9) 2086.61,1009.84
  GND1 w11.81: v8(2185.04,998.03) 2186.52,960.63 2188.98,954.23 2200.3,942.42 2289.86,942.42 v2(2294.29,937.8)
  SIG1 w9.84: v2(1869.09,1110.24) 2001.97,1110.24 2016.73,1095.47 2019.68,1095.47 2043.31,1071.85 2043.31,1068.9 v2(2046.26,1065.94) ; v2(2430.12,806.1) 2433.07,803.15 v2(2433.07,782.48)
  SIG2 w8.66: v6(2047.24,1248.03) 2104.33,1248.03 2161.42,1190.94 v18(2161.42,1190.75)
  Bottom Layer w8.66: v6(2047.24,1248.03) 2055.12,1240.16 2078.74,1240.16 RAD_C144.2@2077.76,1240.16
  Bottom Layer w9.84: RAD_C58.3@1897.64,787.4 RAD_C58.3@1898.62,788.39 ; v2(1897.64,818.9) 1898.62,817.91 RAD_C58.3@1898.62,788.39 ; RAD_C58.1@1960.63,787.4 1960.63,788.39 1963.58,791.34 1963.58,797.24 1993.11,826.77 1993.11,874.02 1987.2,879.92 1910.43,879.92 1898.62,868.11 RAD_C58.3@1898.62,788.39 ; v2(2430.12,806.1) 2441.93,806.1 2459.65,788.39 RAD_C199.1@2460.63,787.4
  Bottom Layer w21.65: v2(1846.46,830.71) RAD_R200.2@1870.08,854.33 ; RAD_R200.2@1870.08,846.46 v2(1897.64,818.9)
  Bottom Layer w29.53: v2(1870.08,818.9) RAD_R200.2@1870.08,868.11 ; RAD_R200.2@1870.08,846.46 RAD_R200.2@1870.08,868.11 ; RAD_R200.2@1870.08,854.33 RAD_R200.2@1870.08,868.11
  other v8: 2185.04,970.47
TI_QSPI_CS: RAD_R38.1 RAD_U1.1 RAD_U29.U12 | length 701.2
  Top Layer w6.69: RAD_R38.1@1122.05,1594.49 v5(1142.72,1589.57) ; v5(1142.72,1537.4) RAD_U1.1@1157.48,1525.59
  Top Layer w7.09: RAD_U1.1@1157.68,1524.67 1157.48,1525.59 1175.2,1507.87 1175.2,1480.32 v3(1222.44,1433.07)
  GND1 w6.69: v5(1142.72,1537.4) v5(1142.72,1589.57)
  GND1 w7.09: v3(1296.26,1114.17) 1345.47,1181.1 v8(1345.89,1236.8)
  SIG2 w7.09: v3(1222.44,1433.07) 1222.44,1187.01 v3(1296.26,1114.17)
TI_QSPI_D0: RAD_R45.2 RAD_U29.U11
  other v12: 1345.89,1262.39
TI_QSPI_D0_FLASH: RAD_R45.1 RAD_U1.5 | length 1317.4
  Top Layer w6.69: v5(992.13,1306.1) RAD_U1.5@1007.68,1309.98 ; v5(1001.97,1331.69) RAD_U1.5@1010.54,1294.69
  PWR1 w6.69: v3(884.84,1343.5) 858.27,1368.11 858.27,1423.23 1082.68,1647.64 1082.68,1775.59 v3(1087.6,1779.53)
  GND1 w6.69: v3(884.84,1309.06) 897.64,1301.18 984.25,1301.18 1000,1316.93 1000,1329.72 v5(1001.97,1331.69) ; v3(884.84,1343.5) 912.4,1342.52 968.5,1304.13 981.3,1304.13 v5(992.13,1306.1) ; v3@1083.66,1775.59 v3(1087.6,1779.53)
  GND2 w6.69: v3(884.84,1309.06) 903.54,1290.35 v7(973.43,1290.35)
  Bottom Layer w6.69: v7(973.43,1290.35) 1092.52,1290.35 1119.09,1263.78 RAD_R45.1@1322.08,1263.57
TI_QSPI_D1: RAD_R39.1 RAD_R49.1 RAD_U29.V11 | length 942.2
  Top Layer w6.69: RAD_R39.1@1072.83,1228.35 v5(1084.65,1234.25) ; v5(1233.27,1584.65) RAD_R49.1@1250,1584.65 v5(1266.73,1572.83) ; v5(1309.06,1254.92) RAD_U29.V11@1320.3,1262.39
  GND1 w6.69: v5(1084.65,1234.25) 1108.27,1203.74 1115.16,1199.8 1128.94,1199.8 1200.79,1229.33 1208.66,1239.17 1203.74,1429.13 1203.74,1555.12 v5(1233.27,1584.65) ; v5(1266.73,1572.83) 1250.98,1352.36 1233.27,1308.07 1233.27,1293.31 1237.2,1286.42 v5(1309.06,1254.92)
TI_QSPI_D1_FLASH: RAD_R39.2 RAD_U1.2 | length 747.9
  GND1 w6.69: v3(926.67,1599.9) 926.67,1586.12 1006.89,1503.94 v8(1074.02,1252.17) ; v3(1043.31,1658.46) v8(1103.82,1524.67)
  GND2 w6.69: v3(926.67,1599.9) 931.59,1580.71 962.11,1553.15 985.73,1553.15 1043.31,1617.62 v3(1043.31,1658.46)
TI_QSPI_D2: RAD_R42.1 RAD_R43.1 RAD_U29.T11 | length 765.2
  Top Layer w7.09: v3(887.99,1366.54) 870.08,1370.37 859.84,1380.61 859.84,1448.43 RAD_R42.1@915.35,1503.94 ; v3(1177.17,1284.65) v8(1250,1299.21) ; v5(1253.94,1312.99) RAD_R43.1@1255.12,1292.13
  GND1 w7.09: v5(1253.94,1312.99) 1263.78,1322.83 1272.64,1331.69 1324.8,1331.69 1328.74,1330.22 1335.63,1324.31 1338.58,1317.42 1338.58,1296.26 v8(1371.48,1262.39)
  SIG1 w7.09: v3(887.99,1366.54) 969.88,1284.65 v3(1177.17,1284.65)
TI_QSPI_D2_FLASH: RAD_R42.2 RAD_U1.3 | length 208.5
  Top Layer w7.09: RAD_R42.2@915.35,1527.56 v3(977.56,1571.26) ; RAD_U1.3@1057.68,1524.67 v3(1058.17,1576.38)
  SIG2 w7.09: v3(977.56,1571.26) v3(1058.17,1576.38)
TI_QSPI_D3: RAD_R40.2 RAD_R41.1 RAD_U29.R12 | length 837.6
  Top Layer w6.69: v5(1010.83,1606.3) RAD_R40.2@1023.62,1606.3 ; RAD_R41.1@1171.26,1240.16 v5(1191.93,1245.08) ; v8(1178.15,1241.14) v5(1225.39,1243.11)
  GND1 w6.69: v5(1010.83,1606.3) 1141.73,1320.87 1161.42,1273.62 v5(1191.93,1245.08) v8(1178.15,1241.14) ; v3(1186.02,1145.67) v5(1225.39,1243.11)
  GND2 w6.69: v3(1186.02,1145.67) v12(1397.08,1236.8)
TI_QSPI_D3_FLASH: RAD_R40.1 RAD_U1.7 | length 444.2
  Top Layer w7.09: v3(995.47,1628.84) 1033.86,1622.44 1040.26,1616.04 1040.26,1596.85 RAD_R40.1@1023.62,1582.68 ; RAD_U1.7@1107.68,1309.98 v3(1123.43,1315.35)
  SIG1 w7.09: v3(995.47,1628.84) v3(1123.43,1315.35)
TI_QSPI_SCLK: RAD_R44.2 RAD_U29.R10 | length 623.1
  Top Layer w6.69: v5(1389.76,1299.21) RAD_U29.R10@1397.08,1287.98
  GND1 w6.69: v8(1003.94,1251.97) 1013.78,1317.91 1015.75,1321.85 v3(1033.46,1333.66) ; v5(1389.76,1299.21) 1415.35,1361.22 1415.35,1373.03 v3(1393.7,1412.4)
  Bottom Layer w6.69: v3(1033.46,1333.66) 1112.2,1413.39 v3(1393.7,1412.4)
TI_QSPI_SCLK_FLASH: RAD_R44.1 RAD_U1.6 | length 147.1
  Top Layer w7.09: v3(976.28,1265.45) 976.28,1253.94 1001.87,1228.35 RAD_R44.1@1003.94,1228.35 ; v3(1031.3,1310.24) RAD_U1.6@1057.68,1309.98
  SIG2 w7.09: v3(976.28,1265.45) v3(1031.3,1310.24)
TI_REGOUT_3V3: RAD_C22.2 RAD_C23.1 RAD_C25.1 RAD_C26.1 RAD_C29.1 RAD_C145.1 RAD_L6.2 RAD_R200.1 RAD_U2.8 RAD_U9.6 RAD_U11.2 RAD_U11.6 RAD_U12.1 RAD_U12.6 RAD_U22.6 RAD_U27.1 | length 4374.8
  Top Layer w8: v25(805.91,1881.42) 816.93,1870.39 RAD_U2.8@816.93,1846.06
  Top Layer w8.66: v2(2413.39,1112.2) 2415.35,1114.17 2419.29,1114.17 2427.17,1122.05 2431.1,1122.05 2437.01,1127.95 2437.01,1129.92 2438.98,1131.89 2438.98,1135.83 2440.94,1137.8 2440.94,1139.76 2460.63,1159.45 2460.63,1226.38 RAD_U9.6@2459.65,1225.39
  Top Layer w9.84: RAD_U9.6@2460.63,1225.39 2459.65,1225.39 2495.08,1225.39 RAD_U27.1@2506.89,1237.2 ; RAD_U27.1@2507.87,1238.19 RAD_U27.1@2506.89,1237.2 ; RAD_C145.1@2677.17,1173.23 2678.15,1172.24 2645.67,1204.72 2645.67,1249.02 2648.62,1251.97 2648.62,1254.92 2678.15,1284.45 RAD_U12.6@2678.15,1293.31 ; RAD_U12.6@2677.17,1294.29 RAD_U12.6@2678.15,1293.31 ; RAD_U12.1@2755.91,1461.61 2754.92,1461.61 2754.92,1432.09 2749.02,1426.18 2731.3,1426.18 2678.15,1373.03 RAD_U12.6@2678.15,1293.31 ; RAD_U27.1@2506.89,1237.2 2554.13,1237.2 2580.71,1263.78 2604.33,1263.78 2630.91,1290.35 2675.2,1290.35 RAD_U12.6@2678.15,1293.31
  Top Layer w12.6: RAD_C25.1@507.82,1891.04 RAD_C22.2@546.28,1921.91
  Top Layer w13.78: v2(473.03,1756.27) RAD_C29.1@507.82,1756.27 ; v2(473.03,1787.76) RAD_C29.1@507.82,1787.76 ; v2(473.03,1845.37) RAD_C25.1@507.82,1845.37 ; v2(473.03,1876.87) RAD_C25.1@507.82,1876.87
  Top Layer w17.72: RAD_C25.1@507.82,1861.12 RAD_C25.1@507.82,1891.04
  Top Layer w59.06: RAD_C25.1@507.82,1861.12 507.82,1756.15 549.41,1714.57 RAD_L6.2@549.41,1659.68
  PWR2 w21.65: v2(473.03,1756.27) 515.75,1756.27 ; v2(473.03,1787.76) 515.75,1787.76 ; v2(473.03,1845.37) 515.75,1845.37
  PWR2 w33.46: 515.75,1756.27 562.99,1724.41 ; 515.75,1787.76 562.99,1724.41 ; 515.75,1845.37 562.99,1724.41 ; v2(1838.58,980.32) 1775.59,1025.59 ; v2(1850.39,1003.94) 1775.59,1025.59 ; v2(1866.14,984.25) 1775.59,1025.59
  SIG1 w7.87: v2(473.03,1876.87) 649.61,1814.96 v25(805.91,1881.42)
  SIG1 w8.66: v2(2019.68,1179.13) 2118.11,1179.13 2147.64,1208.66 2149.61,1208.66 2151.57,1210.63 2155.51,1210.63 2157.48,1212.6 2275.59,1212.6 2293.31,1230.32 2295.28,1230.32 2297.24,1232.28 2328.74,1232.28 2330.71,1230.32 2332.68,1230.32 2350.39,1212.6 2354.33,1212.6 2358.27,1208.66 2358.27,1206.69 2360.24,1204.72 2360.24,1165.35 2364.17,1161.42 2364.17,1145.67 2366.14,1143.7 2366.14,1141.73 2372.05,1135.83 2374.02,1135.83 2375.98,1133.86 2377.95,1133.86 2379.92,1131.89 2393.7,1131.89 v2(2413.39,1112.2)
  SIG2 w8.66: 1922.24,1275.59 1921.26,1275.59 1996.06,1200.79 1998.03,1200.79 2001.97,1196.85 2003.94,1196.85 2017.72,1183.07 2017.72,1181.1 v2(2019.68,1179.13)
  SIG2 w9.84: v2(1869.09,1042.32) 1892.72,1065.94 1892.72,1219.49 1925.2,1251.97 1925.2,1272.64 1922.24,1275.59 1922.24,1278.54 1904.53,1296.26 v2(1904.53,1550.2)
  Bottom Layer w9.84: v2(1850.39,1003.94) 1851.38,1003.94 1901.57,1054.13 1901.57,1060.04 1904.53,1062.99 1904.53,1080.71 ; v2(1869.09,1042.32) 1904.53,1077.76 1904.53,1080.71 ; v2(1904.53,1550.2) 1910.43,1556.1 1934.06,1556.1 1939.96,1562.01 1939.96,1588.58 1937.01,1591.54 1934.06,1591.54 1931.1,1594.49 RAD_U11.2@1904.53,1594.49 1934.06,1594.49 1990.16,1650.59 2043.31,1650.59 2046.26,1653.54 2072.83,1653.54 RAD_U11.6@2071.85,1653.54 ; RAD_U22.6@1943.9,1102.36 RAD_U22.6@1942.91,1101.38 ; 1904.53,1080.71 1910.43,1086.61 ; 1910.43,1086.61 1928.15,1086.61 RAD_U22.6@1942.91,1101.38 ; 1910.43,1086.61 1913.39,1086.61 1928.15,1101.38 RAD_U22.6@1942.91,1101.38
  Bottom Layer w13.78: v2(473.03,1756.27) RAD_C26.1@507.82,1756.27 ; v2(473.03,1787.76) RAD_C26.1@507.82,1787.76 ; v2(473.03,1845.37) RAD_C23.1@507.82,1845.37 ; v2(473.03,1876.87) RAD_C23.1@507.82,1876.87
  Bottom Layer w21.65: v2(1838.58,980.32) RAD_R200.1@1870.08,948.82 ; v2(1850.39,1003.94) v2@1870.08,984.25 ; v2(1866.14,984.25) v2@1870.08,980.32
  Bottom Layer w29.53: RAD_R200.1@1870.08,948.82 RAD_R200.1@1870.08,942.91 ; v2@1870.08,980.32 RAD_R200.1@1870.08,942.91 ; v2@1870.08,984.25 RAD_R200.1@1870.08,942.91
  Bottom Layer w59.06: RAD_C26.1@507.82,1756.27 RAD_C23.1@507.82,1876.87
TI_RX1: RAD_U29.M2 | length 1487.5
  Top Layer w4: 1438.41,2003.15 1462.83,2003.15 1464.8,2005.12 1464.8,2010.98 1462.83,2012.95 1414,2012.95 1412.03,2014.92 1412.03,2020.77 1414,2022.74 1438.41,2022.74 ; 1438.41,2063.29 1460.71,2063.29 1462.67,2065.26 1462.67,2071.12 1460.71,2073.09 1416.12,2073.09 1414.15,2075.06 1414.15,2080.92 1416.12,2082.88 1438.41,2082.88 ; 1438.41,2123.44 1459.53,2123.44 1461.49,2125.4 1461.49,2131.26 1459.53,2133.23 1417.3,2133.23 1415.33,2135.2 1415.33,2141.06 1417.3,2143.03 1438.41,2143.03 ; 1438.41,2183.58 1438.41,2193.37 1438.41,2203.17 ; 1438.41,2243.72 1417.3,2243.72 1415.33,2245.69 1415.33,2251.55 1417.3,2253.51 1459.53,2253.51 1461.49,2255.48 1461.49,2261.34 1459.53,2263.31 1438.41,2263.31 ; 1438.41,2303.86 1416.12,2303.86 1414.15,2305.83 1414.15,2311.69 1416.12,2313.66 1460.71,2313.66 1462.67,2315.63 1462.67,2321.48 1460.71,2323.45 1438.41,2323.45 ; 1438.41,2364 1414,2364 1412.03,2365.97 1412.03,2371.83 1414,2373.8 1462.83,2373.8 1464.8,2375.77 1464.8,2381.63 1462.83,2383.59 1438.41,2383.59
  Top Layer w8.4: 1438.41,1849.22 1401.01,1849.22 1401.01,2193.37 1438.41,2193.37 ; 1438.41,1850.21 1438.41,1641.36 ccw(c1479.21,1641.36) 1450.36,1612.51 1465.86,1597.01 cw(c1446.59,1577.74) 1473.85,1577.74 RAD_U29.M2@1473.85,1492.7
TI_RX2: RAD_U29.K2 | length 1488.1
  Top Layer w4: 1513.22,2003.15 1537.63,2003.15 1539.6,2005.12 1539.6,2010.98 1537.63,2012.95 1488.8,2012.95 1486.83,2014.92 1486.83,2020.77 1488.8,2022.74 1513.22,2022.74 ; 1513.22,2063.29 1535.51,2063.29 1537.48,2065.26 1537.48,2071.12 1535.51,2073.09 1490.92,2073.09 1488.96,2075.06 1488.96,2080.92 1490.92,2082.88 1513.22,2082.88 ; 1513.22,2123.44 1534.33,2123.44 1536.3,2125.4 1536.3,2131.26 1534.33,2133.23 1492.1,2133.23 1490.14,2135.2 1490.14,2141.06 1492.1,2143.03 1513.22,2143.03 ; 1513.22,2183.58 1513.22,2193.37 1513.22,2203.17 ; 1513.22,2243.72 1492.1,2243.72 1490.14,2245.69 1490.14,2251.55 1492.1,2253.51 1534.33,2253.51 1536.3,2255.48 1536.3,2261.34 1534.33,2263.31 1513.22,2263.31 ; 1513.22,2303.86 1490.92,2303.86 1488.96,2305.83 1488.96,2311.69 1490.92,2313.66 1535.51,2313.66 1537.48,2315.63 1537.48,2321.48 1535.51,2323.45 1513.22,2323.45 ; 1513.22,2364 1488.8,2364 1486.83,2365.97 1486.83,2371.83 1488.8,2373.8 1537.63,2373.8 1539.6,2375.77 1539.6,2381.63 1537.63,2383.59 1513.22,2383.59
  Top Layer w8.4: 1513.22,1849.22 1475.82,1849.22 1475.82,2193.37 1513.22,2193.37 ; 1513.22,1850.21 1513.22,1760.27 cw(c1487.73,1760.27) 1505.75,1742.24 ccw(c1529.41,1718.59) 1495.95,1718.59 1495.95,1635.46 ccw(c1527.78,1635.46) 1505.27,1612.96 cw(c1457.59,1565.27) 1525.03,1565.27 RAD_U29.K2@1525.03,1492.7
TI_RX3: RAD_U29.H2 | length 1488.1
  Top Layer w4: 1588.02,2003.15 1612.44,2003.15 1614.41,2005.12 1614.41,2010.98 1612.44,2012.95 1563.6,2012.95 1561.63,2014.92 1561.63,2020.77 1563.6,2022.74 1588.02,2022.74 ; 1588.02,2063.29 1610.31,2063.29 1612.28,2065.26 1612.28,2071.12 1610.31,2073.09 1565.73,2073.09 1563.76,2075.06 1563.76,2080.92 1565.73,2082.88 1588.02,2082.88 ; 1588.02,2123.44 1609.13,2123.44 1611.1,2125.4 1611.1,2131.26 1609.13,2133.23 1566.91,2133.23 1564.94,2135.2 1564.94,2141.06 1566.91,2143.03 1588.02,2143.03 ; 1588.02,2183.58 1588.02,2193.37 1588.02,2203.17 ; 1588.02,2243.72 1566.91,2243.72 1564.94,2245.69 1564.94,2251.55 1566.91,2253.51 1609.13,2253.51 1611.1,2255.48 1611.1,2261.34 1609.13,2263.31 1588.02,2263.31 ; 1588.02,2303.86 1565.73,2303.86 1563.76,2305.83 1563.76,2311.69 1565.73,2313.66 1610.31,2313.66 1612.28,2315.63 1612.28,2321.48 1610.31,2323.45 1588.02,2323.45 ; 1588.02,2364 1563.6,2364 1561.63,2365.97 1561.63,2371.83 1563.6,2373.8 1612.44,2373.8 1614.41,2375.77 1614.41,2381.63 1612.44,2383.59 1588.02,2383.59
  Top Layer w8.4: RAD_U29.H2@1576.21,1492.7 1576.21,1565.27 cw(c1643.65,1565.27) 1595.96,1612.96 ccw(c1573.46,1635.46) 1605.28,1635.46 1605.28,1718.59 ccw(c1571.83,1718.59) 1595.49,1742.24 cw(c1613.51,1760.27) 1588.02,1760.27 1588.02,1850.21 ; 1588.02,1849.22 1550.62,1849.22 1550.62,2193.37 1588.02,2193.37
TI_RX4: RAD_U29.F2 | length 1487.5
  Top Layer w4: 1662.82,2003.15 1687.24,2003.15 1689.21,2005.12 1689.21,2010.98 1687.24,2012.95 1638.41,2012.95 1636.44,2014.92 1636.44,2020.77 1638.41,2022.74 1662.82,2022.74 ; 1662.82,2063.29 1685.12,2063.29 1687.08,2065.26 1687.08,2071.12 1685.12,2073.09 1640.53,2073.09 1638.56,2075.06 1638.56,2080.92 1640.53,2082.88 1662.82,2082.88 ; 1662.82,2123.44 1683.94,2123.44 1685.9,2125.4 1685.9,2131.26 1683.94,2133.23 1641.71,2133.23 1639.74,2135.2 1639.74,2141.06 1641.71,2143.03 1662.82,2143.03 ; 1662.82,2183.58 1662.82,2193.37 1662.82,2203.17 ; 1662.82,2243.72 1641.71,2243.72 1639.74,2245.69 1639.74,2251.55 1641.71,2253.51 1683.94,2253.51 1685.9,2255.48 1685.9,2261.34 1683.94,2263.31 1662.82,2263.31 ; 1662.82,2303.86 1640.53,2303.86 1638.56,2305.83 1638.56,2311.69 1640.53,2313.66 1685.12,2313.66 1687.08,2315.63 1687.08,2321.48 1685.12,2323.45 1662.82,2323.45 ; 1662.82,2364 1638.41,2364 1636.44,2365.97 1636.44,2371.83 1638.41,2373.8 1687.24,2373.8 1689.21,2375.77 1689.21,2381.63 1687.24,2383.59 1662.82,2383.59
  Top Layer w8.4: RAD_U29.F2@1627.39,1492.7 1627.39,1577.74 cw(c1654.64,1577.74) 1635.37,1597.01 1650.87,1612.51 ccw(c1622.03,1641.36) 1662.82,1641.36 1662.82,1850.21 ; 1662.82,1849.22 1625.42,1849.22 1625.42,2193.37 1662.82,2193.37
TI_SOP0_TDO: RAD_R310.1 RAD_R386.1 | length 142.7
  Bottom Layer w7.09: RAD_R310.1@1062.99,1003.94 1080.71,986.22 1080.71,983.27 1125,938.98 1127.95,938.98 1139.76,927.17 1142.72,927.17 1145.67,924.21 1145.67,921.26 1160.43,906.5 RAD_R386.1@1161.42,905.51
TI_SOP1_MSS_SPIB_CS2: RAD_R305.1 RAD_U29.R14 | length 705.9
  GND2 w6.69: v7(1312.01,952.76) 1328.74,857.28 1332.68,853.35 1332.68,828.74 1375.98,785.43 1445.87,785.43 1449.8,789.37 1534.45,789.37 v7(1572.83,750.98)
  Bottom Layer w6.69: v7(1312.01,952.76) 1312.01,1057.09 1313.98,1107.28 1369.09,1162.4 v12(1394.12,1182.67) ; v7(1572.83,750.98) 1604.33,750 RAD_R305.1@1609.06,755.12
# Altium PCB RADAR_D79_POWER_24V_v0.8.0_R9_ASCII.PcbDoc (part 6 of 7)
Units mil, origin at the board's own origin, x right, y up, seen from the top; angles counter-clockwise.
Board outline 3110.24 x 3110.24 mil, 8 copper layers (Top Layer, GND1, SIG1, PWR1, PWR2, SIG2, GND2, Bottom Layer), stack 55.2 mil thick; 304 components, 269 nets, 1408 pads, 1366 vias.

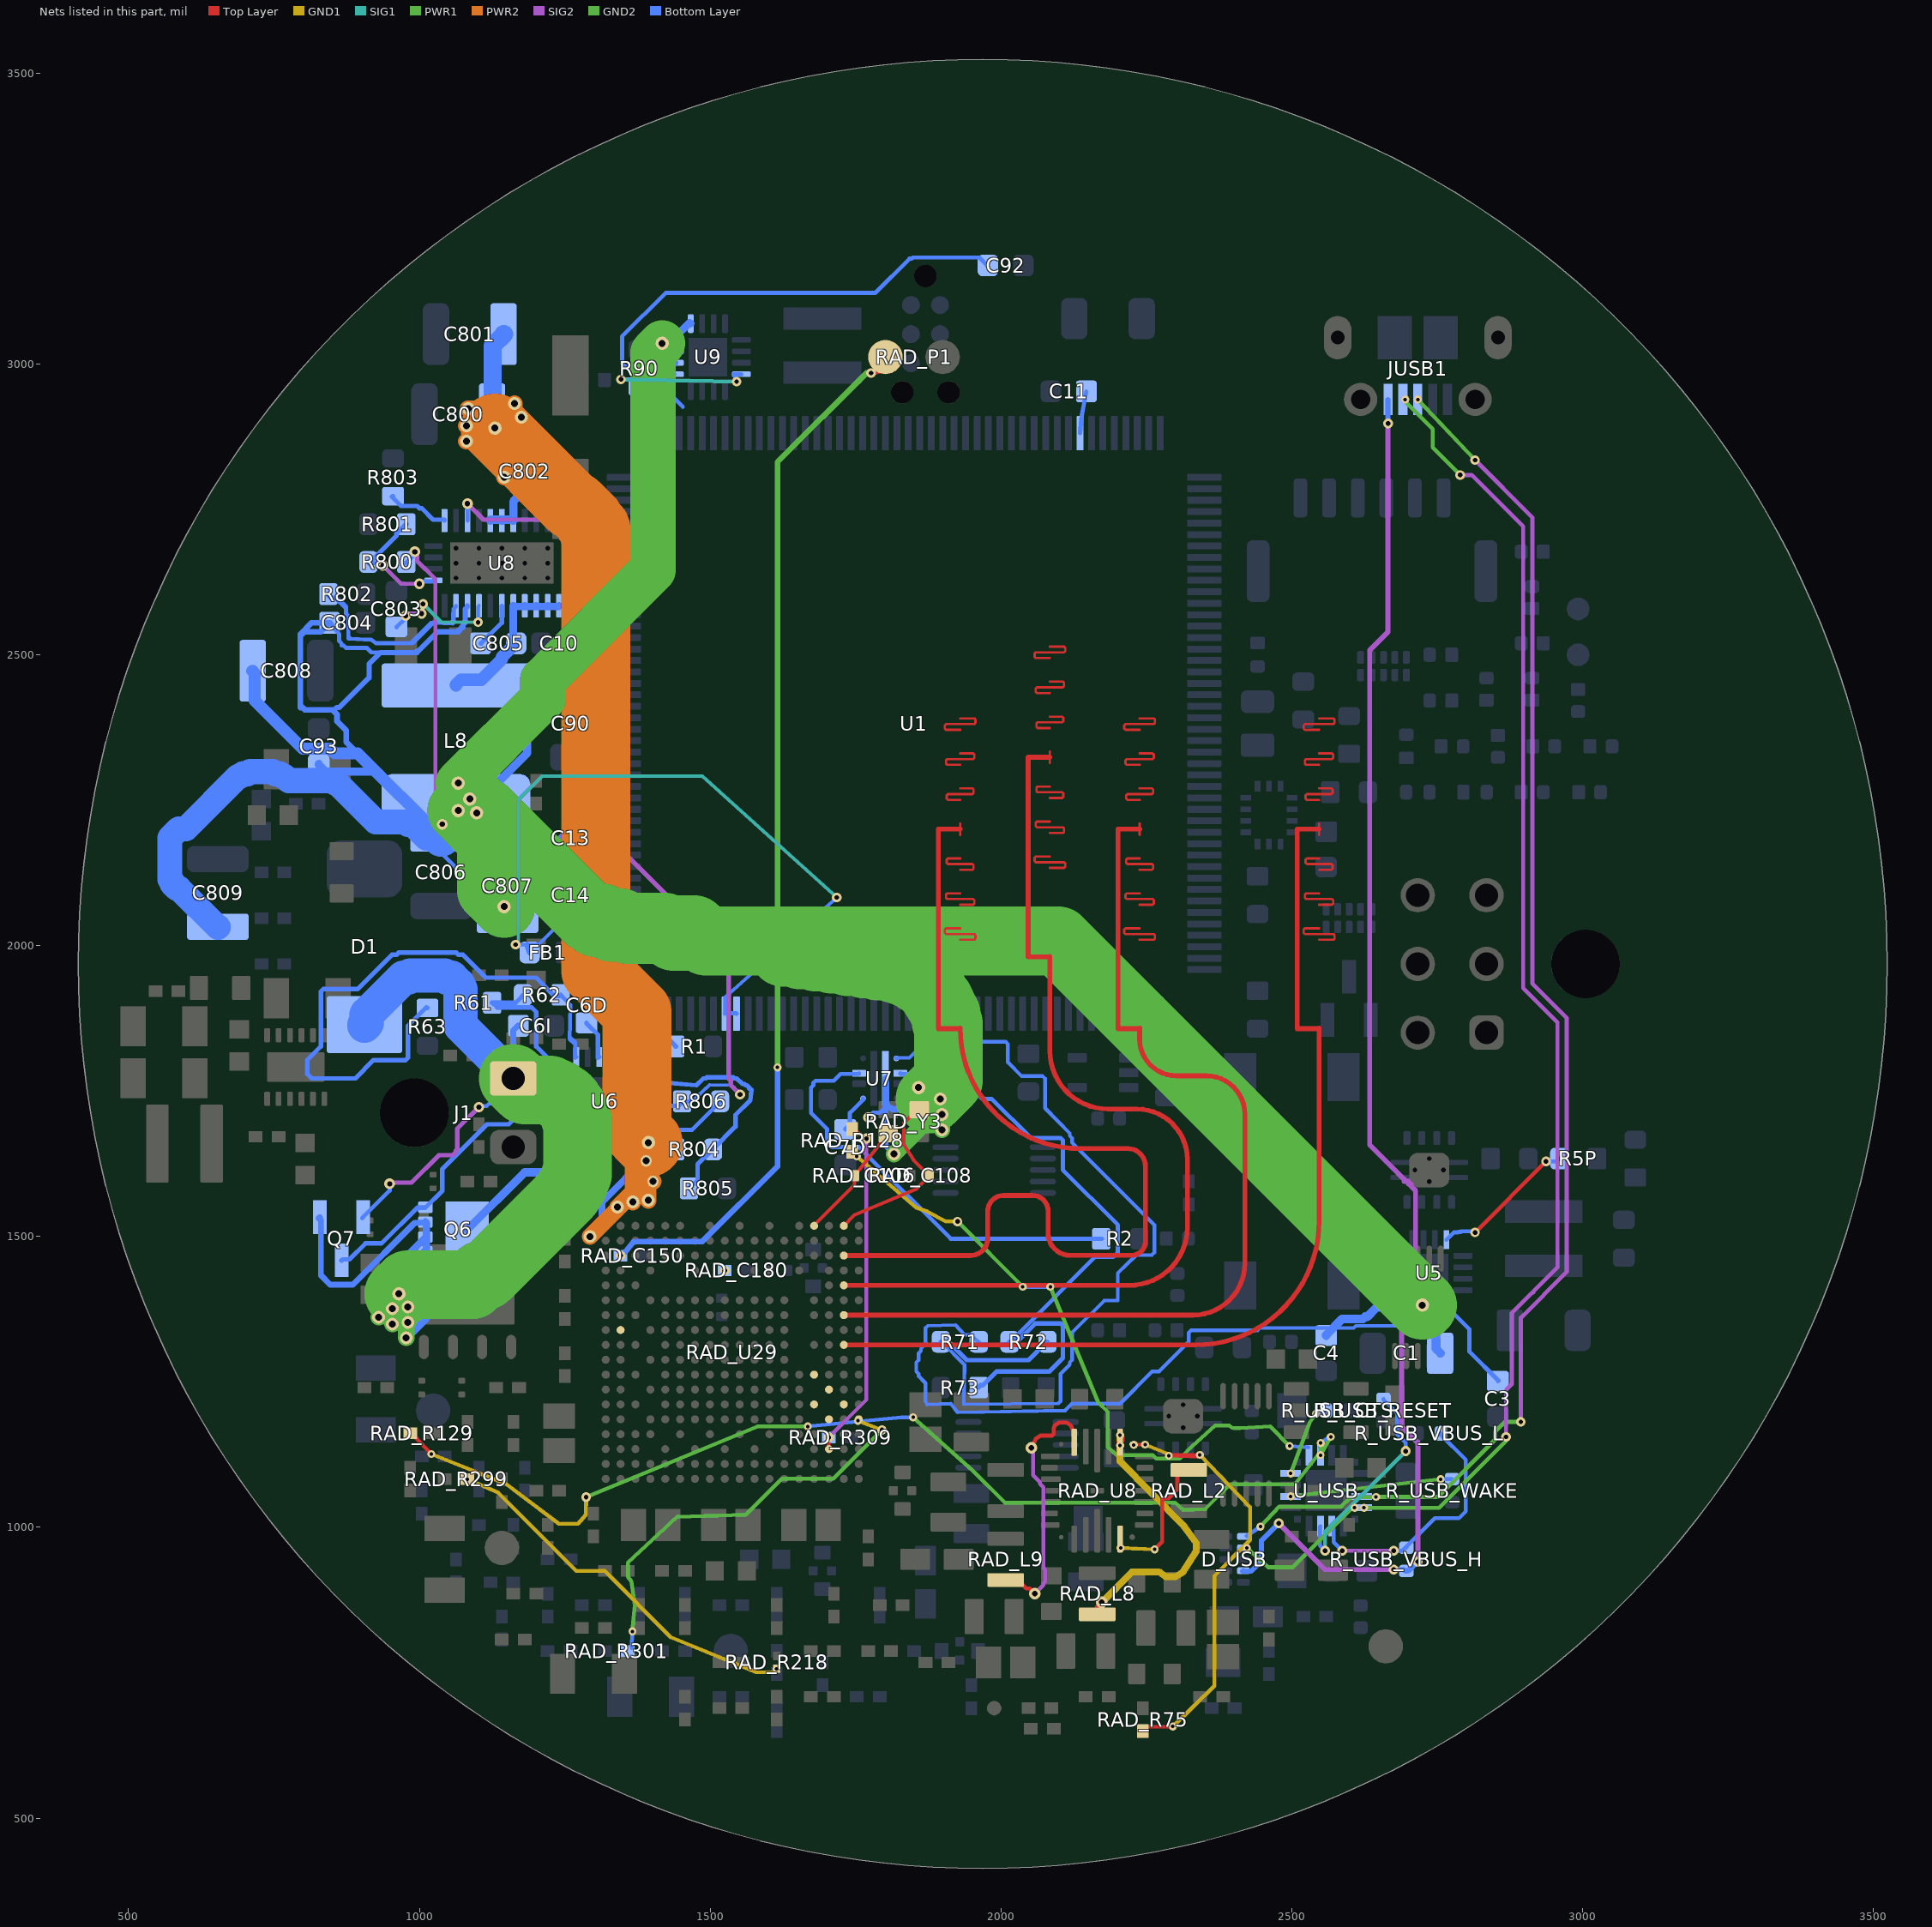
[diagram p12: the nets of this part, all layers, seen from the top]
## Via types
v1: diameter 13.77, hole 5.9, Top Layer to GND1, tented both sides, 513 vias
v2: diameter 19.68, hole 9.84, Top Layer to Bottom Layer, tented both sides, 196 vias
v3: diameter 16.54, hole 7.87, Top Layer to Bottom Layer, tented both sides, 129 vias
v4: diameter 13.77, hole 5.9, Top Layer to GND1, tented top, 104 vias
v5: diameter 13.78, hole 5.91, Top Layer to GND1, tented both sides, 83 vias
v6: diameter 17.32, hole 7.87, Top Layer to Bottom Layer, tented both sides, 69 vias
v7: diameter 13.78, hole 5.91, GND2 to Bottom Layer, tented both sides, 68 vias
v8: diameter 13.78, hole 5.91, Top Layer to GND1, tented bottom, 55 vias
v9: diameter 13.78, hole 5.91, GND2 to Bottom Layer, tented top, 43 vias
v10: diameter 22.05, hole 11.81, Top Layer to Bottom Layer, tented both sides, 23 vias
v11: diameter 16.54, hole 7.87, GND2 to Bottom Layer, tented both sides, 22 vias
v12: diameter 16.54, hole 7.87, Top Layer to Bottom Layer, 14 vias
v13: diameter 22.83, hole 11.81, Top Layer to Bottom Layer, tented both sides, 11 vias
v14: diameter 18.11, hole 9.06, Top Layer to Bottom Layer, tented both sides, 8 vias
v15: diameter 19.68, hole 7.87, Top Layer to Bottom Layer, 3 vias
v16: diameter 17.32, hole 8.66, Top Layer to Bottom Layer, tented both sides, 3 vias
v17: diameter 20.47, hole 9.84, Top Layer to Bottom Layer, tented both sides, 3 vias
v18: diameter 17.72, hole 9.84, Top Layer to Bottom Layer, tented both sides, 2 vias
v19: diameter 22.05, hole 11.02, Top Layer to Bottom Layer, tented both sides, 2 vias
v20: diameter 19.68, hole 11.81, Top Layer to Bottom Layer, tented both sides, 2 vias
v21: diameter 19.68, hole 9.84, SIG1 to Bottom Layer, tented both sides, 2 vias
v22: diameter 16.54, hole 7.87, SIG1 to SIG2, tented both sides, 2 vias
v23: diameter 16.54, hole 7.87, Top Layer to SIG1, 2 vias
v24: diameter 13.78, hole 5.91, Top Layer to GND1, 2 vias
v25: diameter 18, hole 9.84, Top Layer to Bottom Layer, tented both sides, 1 vias
v26: diameter 19.68, hole 9.84, GND2 to Bottom Layer, tented both sides, 1 vias
v27: diameter 17.32, hole 7.87, SIG1 to Bottom Layer, tented both sides, 1 vias
v28: diameter 19.68, hole 9.84, SIG2 to Bottom Layer, tented both sides, 1 vias
v29: diameter 16.54, hole 7.87, PWR2 to GND1, tented both sides, 1 vias

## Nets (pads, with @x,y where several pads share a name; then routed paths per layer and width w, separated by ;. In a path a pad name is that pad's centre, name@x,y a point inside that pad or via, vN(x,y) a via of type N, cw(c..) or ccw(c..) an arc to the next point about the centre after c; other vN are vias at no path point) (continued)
TI_SOP2_PMIC_CLK: RAD_R218.2 RAD_R299.1 | length 654.2
  GND1 w6.69: v8(1082.68,1082.68) 1134.84,1060.04 1269.68,925.2 1318.9,925.2 1432.09,811.02 1578.74,750.98 1607.28,750 v8(1614.17,756.69)
TI_SOP3_MSS_UARTB_TX: RAD_R301.1 RAD_U29.A14 | length 722.5
  Top Layer w6.69: RAD_U29.A14@1753.18,1183.45 v8(1753.94,1183.07)
  GND1 w6.69: v8(1753.94,1183.07) v3(1795.28,1167.32)
  GND2 w6.69: v7(1366.14,820.87) 1370.08,866.14 1364.17,907.48 1358.27,915.35 1358.27,938.98 1442.91,1017.72 1561.02,1021.65 1623.03,1083.66 1711.61,1083.66 1763.78,1135.83 v3(1795.28,1167.32)
  Bottom Layer w6.69: RAD_R301.1@1365.35,792.52 v7(1366.14,820.87)
TI_SOP4_MSS_UARTA_TX: RAD_R128.1 RAD_R309.1 RAD_U29.C16 | length 591.8
  Top Layer w6.69: v6(1703.74,1154.53) 1703.74,1133.86 RAD_U29.C16@1704.16,1134.44 ; RAD_R128.1@1744.09,1685.04 v6(1768.7,1668.31)
  SIG2 w6.69: v6(1703.74,1154.53) 1768.7,1219.49 v6(1768.7,1668.31)
TI_SW_B1: RAD_L9.1 RAD_U8.28 | length 440.6
  Top Layer w7.09: RAD_L9.1@2007.87,909.45 2028.54,909.45 2043.31,894.68 2049.21,894.68 v2(2058.07,885.83) ; v2(2052.17,1136.81) 2060.04,1152.56 2067.91,1157.48 2072.83,1157.48 2087.6,1157.48 2090.55,1160.43 2090.55,1170.28 2092.52,1175.2 2100.39,1180.12 2112.2,1180.12 2120.08,1175.2 RAD_U8.28@2125.98,1160.62 ; RAD_U8.28@2125.98,1145.67 RAD_U8.28@2125.98,1146.16
  SIG2 w7.09: v2(2052.17,1136.81) 2055.12,1133.86 2055.12,1089.57 2066.93,1077.76 2066.93,1074.8 2072.83,1068.9 2072.83,930.12 2075.79,927.17 2075.79,906.5 2072.83,903.54 2072.83,900.59 v2(2058.07,885.83)
TI_SW_B2: RAD_L8.1 RAD_U8.24 | length 519.5
  Top Layer w7.09: RAD_L8.1@2165.35,850.39 2164.37,850.39 2164.37,862.2 v2(2173.23,871.06) ; RAD_U8.24@2204.72,1146.16 2205.71,1145.67 2208.66,1148.62 RAD_U8.24@2208.66,1154.53
  Top Layer w11.81: v8(2204.72,1140.75) RAD_U8.24@2204.72,1146.16
  GND1 w11.81: v2(2173.23,871.06) 2225.39,923.23 2270.67,923.23 2273.62,922.24 2282.48,915.35 2300.2,915.35 2312.01,922.24 2335.63,958.66 2335.63,972.44 2334.65,974.41 2313.98,1002.95 2204.72,1113.19 v8(2204.72,1158.46) v8(2204.72,1140.75)
TI_SW_B3: RAD_L2.1 RAD_U8.14 | length 257.2
  Top Layer w7.09: RAD_U8.14@2204.72,979.82 2204.72,962 v8(2205.71,964.57) ; v5(2264,962) 2277,975 2277,1049 2278,1050 2288,1050 2303,1065 2303,1098.43 RAD_L2.1@2322.83,1098.43
  GND1 w7.09: v8(2205.71,964.57) v5(2264,962)
TI_SYNCCLKIN: RAD_R75.2 RAD_U8.23 | length 799.1
  Top Layer w6.69: RAD_U8.23@2225.63,1142.85 v5(2228.35,1141.73) v24(2247.7,1142.22) ; RAD_R75.2@2238.98,656.69 2243.99,656.76 v5(2295.28,657.48) ; v24(2288.39,1123.03) v5@2341.62,1121.2 ; v24@2291.34,1124.41 v5(2341.73,1124.41)
  Top Layer w7.09: RAD_R75.2@2238.98,656.69 2244.09,656.69 RAD_R75.2@2244.09,649.61
  GND1 w6.69: v24(2247.7,1142.22) 2289.29,1125.25 v24@2291.34,1124.41 ; v5(2295.28,657.48) 2366.93,727.56 2366.93,916.54 2428.35,977.95 2428.35,1034.65 v5(2341.73,1124.41)
TI_TCK: RAD_U29.C12
TI_TDI: RAD_U29.D13
TI_TMS: RAD_U29.C14
TI_TX1: RAD_U29.B3 | length 2386.8
  Top Layer w4: 1929.74,2010.1 1954.15,2010.1 1956.12,2012.07 1956.12,2017.93 1954.15,2019.9 1905.32,2019.9 1903.35,2021.86 1903.35,2027.72 1905.32,2029.69 1929.74,2029.69 ; 1929.74,2070.24 1952.03,2070.24 1954,2072.21 1954,2078.07 1952.03,2080.04 1907.45,2080.04 1905.48,2082.01 1905.48,2087.86 1907.45,2089.83 1929.74,2089.83 ; 1929.74,2130.38 1950.85,2130.38 1952.82,2132.35 1952.82,2138.21 1950.85,2140.18 1908.63,2140.18 1906.66,2142.15 1906.66,2148.01 1908.63,2149.98 1929.74,2149.98 ; 1929.74,2190.53 1929.74,2200.32 1929.74,2210.12 ; 1929.74,2250.67 1908.63,2250.67 1906.66,2252.64 1906.66,2258.5 1908.63,2260.46 1950.85,2260.46 1952.82,2262.43 1952.82,2268.29 1950.85,2270.26 1929.74,2270.26 ; 1929.74,2310.81 1907.45,2310.81 1905.48,2312.78 1905.48,2318.64 1907.45,2320.61 1952.03,2320.61 1954,2322.57 1954,2328.43 1952.03,2330.4 1929.74,2330.4 ; 1929.74,2370.95 1905.32,2370.95 1903.35,2372.92 1903.35,2378.78 1905.32,2380.75 1954.15,2380.75 1956.12,2382.72 1956.12,2388.57 1954.15,2390.54 1929.74,2390.54
  Top Layer w8.4: RAD_U29.B3@1729.75,1467.11 1947.25,1467.11 ccw(c1947.25,1496.94) 1977.08,1496.94 1977.08,1543.13 cw(c2004.41,1543.13) 2004.41,1570.46 2054.41,1570.46 cw(c2054.41,1544.11) 2080.76,1544.11 2080.76,1505.64 ccw(c2118.96,1505.64) 2118.96,1467.45 2224.28,1467.45 ccw(c2224.28,1491.29) 2248.12,1491.29 2248.12,1620.82 ccw(c2217.95,1620.82) 2217.95,1651 2136.82,1651 cw(c2136.82,1858.08) 1929.74,1858.08 ; 1929.74,1857.1 1892.34,1857.1 1892.34,2200.32 1929.74,2200.32
TI_TX2: RAD_U29.B5 | length 2386.9
  Top Layer w4: 2083.99,2133.53 2108.41,2133.53 2110.38,2135.49 2110.38,2141.35 2108.41,2143.32 2059.57,2143.32 2057.6,2145.29 2057.6,2151.15 2059.57,2153.12 2083.99,2153.12 ; 2083.99,2193.67 2106.28,2193.67 2108.25,2195.64 2108.25,2201.49 2106.28,2203.46 2061.7,2203.46 2059.73,2205.43 2059.73,2211.29 2061.7,2213.26 2083.99,2213.26 ; 2083.99,2253.81 2105.1,2253.81 2107.07,2255.78 2107.07,2261.64 2105.1,2263.61 2062.88,2263.61 2060.91,2265.57 2060.91,2271.43 2062.88,2273.4 2083.99,2273.4 ; 2083.99,2313.95 2083.99,2323.75 2083.99,2333.54 ; 2083.99,2374.09 2062.88,2374.09 2060.91,2376.06 2060.91,2381.92 2062.88,2383.89 2105.1,2383.89 2107.07,2385.86 2107.07,2391.72 2105.1,2393.68 2083.99,2393.68 ; 2083.99,2434.24 2061.7,2434.24 2059.73,2436.2 2059.73,2442.06 2061.7,2444.03 2106.28,2444.03 2108.25,2446 2108.25,2451.86 2106.28,2453.83 2083.99,2453.83 ; 2083.99,2494.38 2059.57,2494.38 2057.6,2496.35 2057.6,2502.2 2059.57,2504.17 2108.41,2504.17 2110.38,2506.14 2110.38,2512 2108.41,2513.97 2083.99,2513.97
  Top Layer w8.4: RAD_U29.B5@1729.75,1415.93 2220.58,1415.93 ccw(c2220.58,1515.65) 2320.3,1515.65 2320.3,1632.41 ccw(c2233.71,1632.41) 2233.71,1719.01 2183.99,1719.01 cw(c2183.99,1819.01) 2083.99,1819.01 2083.99,1981.51 ; 2083.99,1980.52 2046.59,1980.52 2046.59,2323.75 2083.99,2323.75
TI_TX3: RAD_U29.B7 | length 2387.1
  Top Layer w4: 2238.28,2010.1 2262.7,2010.1 2264.67,2012.07 2264.67,2017.93 2262.7,2019.9 2213.86,2019.9 2211.9,2021.86 2211.9,2027.72 2213.86,2029.69 2238.28,2029.69 ; 2238.28,2070.24 2260.57,2070.24 2262.54,2072.21 2262.54,2078.07 2260.57,2080.04 2215.99,2080.04 2214.02,2082.01 2214.02,2087.86 2215.99,2089.83 2238.28,2089.83 ; 2238.28,2130.38 2259.39,2130.38 2261.36,2132.35 2261.36,2138.21 2259.39,2140.18 2217.17,2140.18 2215.2,2142.15 2215.2,2148.01 2217.17,2149.98 2238.28,2149.98 ; 2238.28,2190.53 2238.28,2200.32 2238.28,2210.12 ; 2238.28,2250.67 2217.17,2250.67 2215.2,2252.64 2215.2,2258.5 2217.17,2260.46 2259.39,2260.46 2261.36,2262.43 2261.36,2268.29 2259.39,2270.26 2238.28,2270.26 ; 2238.28,2310.81 2215.99,2310.81 2214.02,2312.78 2214.02,2318.64 2215.99,2320.61 2260.57,2320.61 2262.54,2322.57 2262.54,2328.43 2260.57,2330.4 2238.28,2330.4 ; 2238.28,2370.95 2213.86,2370.95 2211.9,2372.92 2211.9,2378.78 2213.86,2380.75 2262.7,2380.75 2264.67,2382.72 2264.67,2388.57 2262.7,2390.54 2238.28,2390.54
  Top Layer w8.4: RAD_U29.B7@1729.75,1364.75 2329.91,1364.75 ccw(c2329.91,1453.99) 2419.15,1453.99 2419.15,1710.08 ccw(c2353.05,1710.08) 2353.05,1776.18 2301.52,1776.18 cw(c2301.52,1839.41) 2238.28,1839.41 2238.28,1858.08 ; 2238.28,1857.1 2200.88,1857.1 2200.88,2200.32 2238.28,2200.32
TI_TX4: RAD_U29.B9 | length 2387.8
  Top Layer w4: 2546.82,2010.1 2571.24,2010.1 2573.21,2012.07 2573.21,2017.93 2571.24,2019.9 2522.41,2019.9 2520.44,2021.86 2520.44,2027.72 2522.41,2029.69 2546.82,2029.69 ; 2546.82,2070.24 2569.12,2070.24 2571.09,2072.21 2571.09,2078.07 2569.12,2080.04 2524.53,2080.04 2522.56,2082.01 2522.56,2087.86 2524.53,2089.83 2546.82,2089.83 ; 2546.82,2130.38 2567.94,2130.38 2569.91,2132.35 2569.91,2138.21 2567.94,2140.18 2525.71,2140.18 2523.74,2142.15 2523.74,2148.01 2525.71,2149.98 2546.82,2149.98 ; 2546.82,2190.53 2546.82,2200.32 2546.82,2210.12 ; 2546.82,2250.67 2525.71,2250.67 2523.74,2252.64 2523.74,2258.5 2525.71,2260.46 2567.94,2260.46 2569.91,2262.43 2569.91,2268.29 2567.94,2270.26 2546.82,2270.26 ; 2546.82,2310.81 2524.53,2310.81 2522.56,2312.78 2522.56,2318.64 2524.53,2320.61 2569.12,2320.61 2571.09,2322.57 2571.09,2328.43 2569.12,2330.4 2546.82,2330.4 ; 2546.82,2370.95 2522.41,2370.95 2520.44,2372.92 2520.44,2378.78 2522.41,2380.75 2571.24,2380.75 2573.21,2382.72 2573.21,2388.57 2571.24,2390.54 2546.82,2390.54
  Top Layer w8.4: RAD_U29.B9@1729.75,1313.57 2334.62,1313.57 ccw(c2334.62,1525.77) 2546.82,1525.77 2546.82,1858.08 ; 2546.82,1857.1 2509.42,1857.1 2509.42,2200.32 2546.82,2200.32
TI_VBGAP: RAD_C180.1 RAD_U29.K4
  other v12: 1525.03,1441.52
TI_VPP_1P7: RAD_C150.2 RAD_P1.1 RAD_U29.U3 | length 1776.7
  Top Layer w9.84: v3(1776.38,2984.25) RAD_P1.1@1792.32,2988.19
  GND2 w9.84: v7(1615.75,1790.55) 1615.75,2831.5 1768.5,2984.25 v3(1776.38,2984.25)
  Bottom Layer w9.84: RAD_C150.2@1352.98,1472.23 1368.5,1491.34 1486.61,1491.34 1615.75,1620.47 v7(1615.75,1790.55)
  other v12: 1345.89,1467.11
TI_VPP_EN: RAD_U29.U8
TI_XDSET_UARTA_RX: RAD_R129.2 U_USB.18 | length 1852.9
  Top Layer w6.69: RAD_R129.2@991.34,1156.3 v5(1020.47,1125.98)
  GND1 w6.69: v5(1020.47,1125.98) 1148.62,1074.8 1240.16,1005.91 1272.64,1005.91 1286.42,1021.65 v3(1286.61,1051.97)
  GND2 w6.69: v3(1286.61,1051.97) 1581.1,1173.23 v7(1667.72,1173.23) ; v7(1848.82,1188.98) 1951.18,1097.64 2006.3,1042.52 2299.21,1042.52 2313.39,1029.92 2351.18,1031.5 2393.7,1074.02 2505.51,1074.02 2549.61,1130.71 v7(2549.61,1144.88) ; v9(2549.21,1124.02) v7(2566.93,1155.51)
  Bottom Layer w6.69: v7(1667.72,1173.23) 1828.35,1188.98 v7(1848.82,1188.98) ; U_USB.18@2548.03,1137.01 v7(2549.61,1144.88) 2564.96,1155.51 v7(2566.93,1155.51)
TI_XDSET_UARTA_TX: RAD_R128.2 U_USB.17 | length 1110
  Top Layer w6.69: RAD_R128.2@1749.21,1638.58 v8(1751.97,1637.8)
  GND1 w6.69: v8(1751.97,1637.8) 1854.33,1549.21 1872.05,1543.31 1905.51,1525.59 v3(1925.2,1525.59)
  GND2 w6.69: v3(1925.2,1525.59) v7(2037.4,1413.39) ; v7(2084.65,1413.39) 2167.32,1214.57 2183.07,1198.82 2183.07,1137.8 2198.82,1124.02 2260.83,1124.02 2266.73,1118.11 2307.09,1118.11 2320.87,1131.89 2368.11,1175.2 2391.73,1175.2 2397.15,1171.26 2400.1,1170.28 2411.42,1170.28 2462.6,1173.23 v7(2496.06,1139.76)
  Bottom Layer w6.69: v7(2037.4,1413.39) v7(2084.65,1413.39) ; v7(2496.06,1139.76) U_USB.17@2528.35,1137.01
TI_XREF_CLK0: RAD_U29.B13
TI_XREF_CLK1: RAD_U29.D11
TI_XTALM: RAD_C108.1 RAD_U29.B1 RAD_Y3.3 | length 315.3
  Top Layer w6: RAD_U29.B1@1729.75,1518.3 1747.05,1536.42 1854.33,1581.69 RAD_C108.1@1876.7,1604.58 1849.41,1631.89 1832.68,1658.46 1832.68,1694.88 1844.49,1706.69 RAD_Y3.3@1859.26,1718.02
TI_XTALP: RAD_C106.1 RAD_U29.D1 RAD_Y3.1 | length 207.6
  Top Layer w6: RAD_U29.D1@1678.57,1518.3 1678.57,1519.47 1747.97,1588.86 RAD_C106.1@1747.97,1604.37 RAD_Y3.1@1806.11,1676.68
U5_PG: R5P.1 U5.4 | length 253.9
  Top Layer w7.09: v3(2814.96,1506.89) v3(2937.01,1628.94)
  Bottom Layer w7.09: U5.4@2765.75,1494.59 2765.75,1494.09 2778.54,1506.89 2785.43,1506.89 2786.42,1507.87 2790.35,1507.87 2791.34,1508.86 2809.06,1508.86 2811.02,1506.89 v3(2814.96,1506.89) ; v3(2937.01,1628.94) 2954.72,1628.94 R5P.1@2959.65,1633.86
U5_SS_LOCAL: C3.1 U5.9 | length 166.2
  Bottom Layer w7.09: U5.9@2765.75,1379.43 2766.73,1378.94 2805.12,1340.55 2805.12,1302.17 2855.32,1251.97 C3.1@2854.33,1250.98
U6_BGATE: Q6.4 Q7.3 U6.3 | length 509
  Bottom Layer w7.87: Q7.3@866.14,1459.15 866.14,1458.66 868.11,1460.63 879.92,1460.63 907.48,1488.19 935.04,1488.19 996.06,1549.21 Q6.4@1009.84,1549.21 ; Q6.4@1010.24,1550 Q6.4@1009.84,1549.21 ; U6.3@1242.62,1722.44 1242.13,1722.44 1226.38,1722.44 1220.47,1716.54 1218.5,1716.54 1216.54,1714.57 1175.2,1714.57 1153.54,1692.91 1116.14,1692.91 1039.37,1616.14 1039.37,1578.74 Q6.4@1009.84,1549.21
U6_DRV: Q7.1 U6.4 | length 459.1
  SIG2 w7.87: v14(948.82,1590.55) 950.79,1592.52 986.22,1592.52 1033.46,1639.76 1057.09,1639.76 1062.99,1645.67 1062.99,1647.64 1064.96,1649.61 1064.96,1685.04 v16(1102.36,1722.44)
  Bottom Layer w6.69: v16(1102.36,1722.44) 1104.33,1724.41 1116.14,1724.41 1120.08,1728.35 1212.6,1728.35 1220.81,1736.55 1236.22,1737.17 1242.13,1742.13 U6.4@1242.62,1742.13
  Bottom Layer w7.09: Q7.1@903.54,1532.97 901.57,1531.5 948.82,1578.74 v14(948.82,1590.55)
U6_DVDT: C6D.1 U6.9 | length 70.7
  Bottom Layer w7.87: C6D.1@1287.4,1867.13 1287.4,1866.14 1307.09,1846.46 1307.09,1807.09 U6.9@1309.06,1808.56
U6_ILIM_LOCAL: R1.1 U6.10 | length 147.1
  Bottom Layer w7.87: U6.10@1328.74,1808.56 1326.77,1807.09 1330.71,1811.02 1330.71,1830.71 1338.58,1838.58 1429.13,1838.58 1440.94,1826.77 R1.1@1439.96,1826.77
U6_IN_BLOCKED: Q6.5 U6.1 U6.2 | length 282.3
  Bottom Layer w13.78: U6.1@1242.62,1683.07 1244.09,1685.04 1244.09,1700.79 U6.2@1242.62,1702.76
  Bottom Layer w14.17: Q6.5@1082.09,1511.81 1082.68,1511.81 1181.1,1610.24 1212.6,1610.24 1232.28,1629.92 1232.28,1673.23 1244.09,1685.04 U6.1@1242.62,1683.07
U6_OVP_LOCAL: R62.2 R63.1 U6.7 | length 1162.4
  Bottom Layer w6.3: R62.2@1243.11,1915.35 1244.09,1913.39 1259.84,1897.64 1258.56,1842.85 1267.72,1834.65 1267.72,1807.09 U6.7@1269.68,1808.56
  Bottom Layer w6.69: R62.2@1243.11,1915.35 1244.09,1913.39 1259.84,1897.64 1258.01,1838.92 1267.72,1830.71 1267.72,1807.09 U6.7@1269.68,1808.56
  Bottom Layer w7.87: R63.1@1013.78,1892.72 1011.81,1893.7 980.32,1862.2 980.32,1807.09 976.38,1803.15 921.26,1803.15 889.76,1771.65 814.96,1771.65 807.09,1779.53 807.09,1803.15 830.71,1826.77 830.71,1921.26 834.65,1925.2 893.7,1925.2 952.76,1984.25 960.63,1984.25 964.57,1988.19 1062.99,1988.19 1066.93,1984.25 1074.8,1984.25 1114.17,1944.88 1200.79,1944.88 1232.28,1913.39 1244.09,1913.39 R62.2@1243.11,1915.35
U6_PGTH_LOCAL: R804.2 R805.1 U6.15 | length 417.4
  Bottom Layer w7.87: U6.15@1395.18,1742.13 1395.67,1742.13 1413.39,1742.13 1421.26,1750 1421.26,1751.97 1429.13,1764.13 1476.38,1759.84 1488.19,1771.65 1492.13,1771.65 1494.09,1773.62 1539.37,1773.62 1541.34,1771.65 1545.28,1771.65 1555.59,1762.28 1559.06,1761.81 1561.02,1759.84 1562.99,1759.84 1566.93,1755.91 1566.93,1753.94 1570.87,1751.97 1568.9,1734.25 1543.31,1708.66 1543.31,1688.98 R804.2@1503.94,1649.61 ; R805.1@1463.58,1582.68 1464.57,1582.68 1478.35,1596.46 1478.35,1624.02 R804.2@1503.94,1649.61 ; R804.2@1504.92,1649.61 R804.2@1503.94,1649.61
U6_UVLO_LOCAL: R61.2 R62.1 U6.6 | length 263.3
  Bottom Layer w7.87: R61.2@1125,1901.57 R61.2@1125.98,1901.57 ; R62.1@1178.15,1915.35 1177.17,1913.39 1165.35,1901.57 R61.2@1125.98,1901.57 ; U6.6@1242.62,1781.5 1244.09,1783.46 1200.79,1826.77 1200.79,1885.83 1192.91,1893.7 1133.86,1893.7 R61.2@1125.98,1901.57
U7_DVDT: C7D.1 U7.7 | length 133.2
  Bottom Layer w6.69: C7D.1@1732.28,1684.06 1732.28,1685.04 1740.16,1692.91 1740.16,1712.6 1763.78,1736.22 U7.7@1762.8,1737.2
  Bottom Layer w7.09: C7D.1@1732.28,1684.06 1732.28,1685.04 1740.16,1692.91 1740.16,1712.6 1763.78,1736.22 U7.7@1762.8,1737.2
U7_ILIM_LOCAL: R2.1 U7.9 | length 743.6
  Bottom Layer w7.09: U7.9@1755.91,1780.51 1755.91,1779.53 1724.41,1779.53 1712.6,1767.72 1681.1,1767.72 1677.17,1763.78 1677.17,1759.84 1673.23,1755.91 1673.23,1712.6 1700.79,1685.04 1700.79,1661.42 1708.66,1653.54 1755.91,1653.54 1913.39,1496.06 2173.23,1496.06 R2.1@2172.24,1496.06
U7_OVLO_LOCAL: R72.2 R73.1 U7.2 | length 1141.9
  Bottom Layer w7.09: U7.2@1826.77,1780.51 1826.77,1779.53 1866.14,1779.53 1870.08,1783.46 1921.26,1783.46 1968.5,1736.22 1984.25,1736.22 2051.18,1669.29 2102.36,1669.29 2106.3,1665.35 2106.3,1614.17 2200.79,1519.68 2200.79,1472.44 2192.91,1464.57 2161.42,1464.57 2015.75,1318.9 R72.2@2014.76,1318.9
  Bottom Layer w7.87: R73.1@1961.61,1240.16 1960.63,1240.16 1964.57,1244.09 1968.5,1244.09 1992.13,1267.72 2082.68,1267.72 2106.3,1291.34 2106.3,1346.46 2102.36,1350.39 2059.06,1350.39 2027.56,1318.9 2015.75,1318.9 R72.2@2014.76,1318.9
U7_UVLO_LOCAL: R71.2 R72.1 U7.1 | length 1545.3
  Bottom Layer w6.3: U7.1@1819.88,1806.1 1818.9,1807.09 1842.52,1807.09 1870.08,1834.65 2007.87,1834.65 2011.81,1830.71 2011.81,1799.21 2035.43,1775.59 2070.87,1775.59 2075.79,1771.65 2075.79,1720.47 2118.11,1677.17 2118.11,1673.23 2122.05,1669.29 2122.05,1661.42 2263.78,1519.68 2263.78,1472.44 2259.84,1468.5 2231.95,1467.7 2200.79,1437.01 2200.79,1389.76 2177.17,1389.29 2122.05,1334.65 2122.05,1287.4 2118.11,1283.46 2118.11,1279.53 2102.36,1263.78 2102.36,1216.54 2098.43,1213.07 1935.95,1211.54 1937.01,1279.53 1897.64,1318.9 R71.2@1896.65,1318.9
  Bottom Layer w7.09: R71.2@1896.65,1318.9 R71.2@1897.64,1318.9
  Bottom Layer w7.87: R71.2@1896.65,1318.9 1897.64,1318.9 1909.45,1318.9 1940.94,1287.4 2047.24,1287.4 2078.74,1318.9 R72.1@2079.72,1318.9
U8_BOOT: C805.1 U8.6 | length 80.1
  Bottom Layer w7.87: C805.1@1105.32,2519.68 1106.3,2519.68 1141.73,2555.12 1141.73,2582.68 U8.6@1141.73,2584.15
U8_ENABLE: R806.1 U6.16 U8.18 | length 1550.3
  SIG2 w7.87: v14(1082.68,2759.84) 1110.24,2732.28 1212.6,2732.28 1216.54,2728.35 1220.47,2728.35 1244.09,2704.72 1244.09,2700.79 1248.03,2696.85 1248.03,2692.91 1251.97,2688.98 1251.97,2590.55 1358.27,2484.25 1358.27,2153.54 1531.5,1980.32 1531.5,1771.65 1535.43,1767.72 1535.43,1759.84 v16(1551.18,1744.09)
  Bottom Layer w6.3: R806.1@1451.77,1732.28 1452.76,1732.28 1468.5,1732.28 1499.09,1760.51 1535.43,1759.84 1541.34,1755.91 1541.34,1753.94 v16(1551.18,1744.09)
  Bottom Layer w7.09: U8.18@1082.68,2730.81 1082.68,2732.28 v14(1082.68,2759.84) ; U6.16@1395.18,1722.44 1393.7,1724.41 1444.88,1724.41 1452.76,1732.28 R806.1@1451.77,1732.28
  Bottom Layer w7.87: U6.16@1395.18,1722.44 1393.7,1724.41 1444.88,1724.41 1452.76,1732.28 R806.1@1451.77,1732.28
U8_FB_LOCAL: R800.2 R801.1 U8.12 | length 227
  SIG2 w7.09: v14(937.01,2653.54) 968.5,2622.05 v14(1000,2622.05)
  Bottom Layer w7.09: R800.2@912.4,2659.45 913.39,2657.48 933.07,2657.48 v14(937.01,2653.54) ; v14(1000,2622.05) 1003.94,2625.98 1023.62,2625.98 U8.12@1024.11,2627.95
  Bottom Layer w7.87: R800.2@912.4,2659.45 913.39,2657.48 960.63,2704.72 960.63,2708.66 976.38,2724.41 R801.1@977.36,2724.41
U8_PGOOD: R803.1 U8.16 | length 110.5
  Bottom Layer w7.87: R803.1@954.72,2772.64 952.76,2771.65 968.5,2755.91 996.06,2755.91 1000,2751.97 1003.94,2751.97 1023.62,2732.28 1043.31,2732.28 U8.16@1043.31,2730.81
U8_RT_LOCAL: R802.1 U8.10 | length 647.9
  Bottom Layer w6.3: R802.1@843.5,2604.33 842.52,2602.36 846.46,2598.43 854.33,2598.43 874.02,2578.74 874.02,2570.87 877.95,2566.93 877.95,2531.5 881.89,2527.56 916.99,2525.81 925.2,2519.68 984.25,2519.68 1019.68,2555.12 1054.78,2554.31 1059.06,2559.06 1059.06,2578.74 1062.99,2582.68 U8.10@1062.99,2584.15
  Bottom Layer w7.09: R802.1@843.5,2604.33 842.52,2602.36 846.46,2598.43 858.27,2598.43 874.02,2582.68 874.02,2570.87 877.95,2566.93 877.95,2527.56 916.99,2525.81 925.2,2519.68 988.19,2519.68 1023.62,2555.12 1057.38,2553.45 1059.06,2578.74 1062.99,2582.68 U8.10@1062.99,2584.15
U8_SW: C805.2 L8.1 U8.1 U8.2 U8.3 U8.4 U8.5 | length 289.8
  Bottom Layer w12.6: U8.5@1161.42,2584.15 1161.42,2582.68 U8.4@1181.1,2582.68 ; U8.4@1181.1,2584.15 U8.4@1181.1,2582.68 ; U8.3@1200.79,2584.15 U8.3@1200.79,2582.68 ; U8.2@1220.47,2584.15 U8.2@1220.47,2582.68 ; U8.1@1240.16,2584.15 1240.16,2582.68 U8.2@1220.47,2582.68 ; U8.4@1181.1,2582.68 U8.3@1200.79,2582.68 ; U8.3@1200.79,2582.68 U8.2@1220.47,2582.68
  Bottom Layer w13.39: U8.5@1161.42,2584.15 1161.42,2582.68 1161.42,2523.62 1165.35,2519.68 C805.2@1166.34,2519.68
  Bottom Layer w21.26: L8.1@1062.99,2447.24 1062.99,2448.82 1070.87,2456.69 1106.3,2456.69 1141.73,2492.13 1141.73,2496.06 1165.35,2519.68 C805.2@1166.34,2519.68
U8_VCC: C803.1 U8.8 | length 239.3
  SIG1 w6.3: v3(1006.3,2587.4) 1037.8,2555.91 v3(1100.79,2555.91)
  SIG2 w7.48: v14(976.38,2566.93) 980.32,2570.87 v16(1003.94,2570.87)
  Bottom Layer w5.91: C803.1@960.63,2548.23 960.63,2547.24 976.38,2562.99 v14(976.38,2566.93)
  Bottom Layer w6.3: v16(1003.94,2570.87) 1004.72,2570.08 1006.3,2571.65 v3(1006.3,2587.4) ; v3(1100.79,2555.91) 1100.79,2582.68 1102.36,2584.25 U8.8@1102.36,2584.15
  Bottom Layer w7.09: C803.1@960.63,2548.23 960.63,2547.24 976.38,2562.99 v14(976.38,2566.93)
U9_PG: R90.1 U9.4 | length 442.3
  SIG1 w7.09: v3(1346.46,2973.43) v3(1545.28,2969.49)
  Bottom Layer w7.09: v3(1346.46,2973.43) 1406.5,2973.43 1452.76,2926.18 1420.28,2958.66 1378.94,2958.66 1377.95,2959 R90.1@1377.95,2959.65 ; v3(1545.28,2969.49) 1541.34,2982.28 1540,2982.28 U9.4@1553.64,2982.28
U9_SS_LOCAL: C92.1 U9.9 | length 835.4
  Bottom Layer w7.09: U9.9@1438.48,2982.28 1438.98,2982.28 1419.29,2982.28 1409.45,2992.13 1358.27,2992.13 1348.43,3001.97 1348.43,3047.24 1423.23,3122.05 1783.46,3122.05 1842.52,3181.1 1846.46,3181.1 1848.43,3183.07 1962.6,3183.07 1976.38,3169.29 C92.1@1977.36,3169.29
USB_BRIDGE_RESET_N: R_USB_RESET.2 U_USB.9 | length 381
  SIG1 w6.69: v6(2557.09,959.65) 2557.09,992.13 v6(2695.87,1130.91)
  Bottom Layer w6.69: U_USB.9@2549.21,1001.97 2548.23,1000.98 2548.23,968.5 v6(2557.09,959.65) ; R_USB_RESET.2@2657.48,1220.87 2657.48,1219.49 2681.1,1195.87 2681.1,1160.43 2695.87,1145.67 v6(2695.87,1130.91)
USB_CTS_N: R_USB_CTS.2 U_USB.15 | length 130
  GND2 w6.69: v9(2498.03,1092.52) 2530.51,1180.12 v7(2541.34,1194.88)
  Bottom Layer w6.69: v7(2541.34,1194.88) R_USB_CTS.2@2558.66,1200.79
USB_DM: D_USB.2 JUSB1.2 U_USB.5 | length 2480.4
  SIG2 w7.09: v3(2789.37,2809.06) 2809.06,2809.06 2897.64,2720.47 2897.64,1927.17 2956.69,1868.11 2956.69,1446.85 2915.35,1405.51 2915.35,1403.54 2913.39,1403.54 2877.95,1368.11 2877.95,1246.06 2868.11,1236.22 v3(2868.11,1155.51)
  GND2 w7.09: v9(2422.64,964.57) 2459.65,931.1 2500.98,931.1 2603.35,1033.46 v7(2607.81,1033.46) ; v9(2624.02,1033.46) 2752.95,1033.46 2868.11,1148.62 v3(2868.11,1155.51) ; v9(2694.88,2938.98) 2694.88,2935.04 2742.13,2887.8 2742.13,2856.3 v3(2789.37,2809.06)
USB_DP: D_USB.1 JUSB1.3 U_USB.4 | length 2478.2
  SIG2 w7.09: v3(2814.96,2834.65) 2913.39,2736.22 2913.39,1935.04 2972.44,1875.98 2972.44,1438.98 2893.7,1360.24 v3(2893.7,1181.1)
  GND2 w7.09: v7(2445.87,1000.98) 2478.35,1035.43 2584.65,1035.43 2600.39,1051.18 v7(2644.68,1052.17) 2750.98,1052.17 2849.41,1150.59 2849.41,1164.37 2866.14,1181.1 v3(2893.7,1181.1) ; v9(2716.54,2938.98) v3(2814.96,2834.65)
  Bottom Layer w7.09: D_USB.1@2422.64,985.24 v7(2445.87,1000.98) ; U_USB.4@2620.08,1053.15 v7(2644.68,1052.17)
USB_VBUS: D_USB.4 JUSB1.1 R_USB_VBUS_H.1 | length 2471
  SIG2 w8.66: v6(2477.36,1006.89) 2557.09,927.17 v6(2675.2,927.17) ; v6(2665.35,2897.64) 2665.35,2539.37 2633.86,2507.87 2633.86,1657.48 2692.91,1598.43 2692.91,1594.49 2700.79,1594.49 2700.79,1590.55 2704.72,1590.55 2704.72,1586.61 2712.6,1578.74 2712.6,1409.45 2688.98,1385.83 2688.98,1173.23 2716.54,1145.67 v6(2716.54,940.94)
  Bottom Layer w8.66: D_USB.4@2416.73,925.2 2415.35,924.21 2430.12,924.21 2447.83,941.93 2447.83,977.36 v6(2477.36,1006.89) ; v6(2665.35,2897.64) 2665.35,2937.01 JUSB1.1@2665.35,2938.98 ; v6(2675.2,927.17) 2692.91,927.17 2695.87,924.21 2696.85,924.8 2696.85,925.2 2700.79,925.2 v6(2716.54,940.94)
USB_VBUS_SENSE: R_USB_VBUS_H.2 R_USB_VBUS_L.1 U_USB.8 | length 444.5
  SIG2 w6.69: v6(2586.61,959.65) v6(2675.2,959.65)
  Bottom Layer w6.69: U_USB.8@2568.9,1001.97 2568.9,1000.98 2571.85,998.03 2571.85,974.41 v6(2586.61,959.65) ; v6(2675.2,959.65) 2689.96,959.65 R_USB_VBUS_H.2@2695.87,965.55 ; R_USB_VBUS_H.2@2696.85,964.96 R_USB_VBUS_H.2@2695.87,965.55 ; R_USB_VBUS_L.1@2756.3,1161.42 2754.92,1160.43 2799.21,1116.14 2799.21,1027.56 2787.4,1015.75 2746.06,1015.75 R_USB_VBUS_H.2@2695.87,965.55
USB_WAKE_N: R_USB_WAKE.2 U_USB.13 | length 279.2
  GND2 w6.69: v9(2498.03,1053.15) v7(2755.91,1082.68)
  Bottom Layer w6.69: v7(2755.91,1082.68) R_USB_WAKE.2@2775.59,1083.07
V12_SYS: C1.1 C4.1 C90.1 C93.1 C804.1 C806.1 C807.1 C808.1 C809.1 L8.2 R71.1 R800.1 U5.10 U5.11 U5.12 U5.13 U7.5 U8.9 U9.10 U9.11 U9.12 U9.13 | length 11180.8
  PWR1 w22.83: v13(1858.27,1755.91) 1877.95,1736.22
  PWR1 w28.35: v10(1815.94,1641.73) 1860.24,1686.02 1860.24,1718.5 1877.95,1736.22 ; 1893.7,1751.97 1892.72,1750.98 1895.67,1748.03 v10(1895.67,1736.22) ; v10(1898.62,1683.07) 1898.62,1715.55 1877.95,1736.22 ; v10(1898.62,1709.65) 1880.91,1727.36 1880.91,1733.27 1877.95,1736.22
  PWR1 w78.74: v13(1066.93,2279.53) 1212.6,2425.2 1212.6,2456.69 1401.57,2645.67 1401.57,3019.68 v13(1417.32,3035.43)
  PWR1 w106.3: v13(1066.93,2232.28) 1118.11,2181.1 1118.11,2094.49 v13(1145.67,2066.93)
  PWR1 w118.11: v13(1086.61,2251.97) 1291.34,2047.24 1314.96,2047.24 1330.71,2031.5 1421.26,2031.5 1437.01,2015.75 1484.25,2015.75 1492.13,2007.87 ; v13(1098.43,2228.35) 1114.17,2228.35 1303.15,2039.37 1346.46,2039.37 1358.27,2027.56 1472.44,2027.56 1492.13,2007.87 ; 1877.95,1736.22 1909.45,1767.72 1909.45,1866.14 1905.51,1870.08 1905.51,1881.89 1901.57,1885.83 1901.57,1889.76 1897.64,1893.7 1897.64,1897.64 1893.7,1901.57 1893.7,1905.51 1885.83,1913.39 1885.83,1917.32 1862.2,1940.94 1858.27,1940.94 1850.39,1948.82 1846.46,1948.82 1842.52,1952.76 1838.58,1952.76 1834.65,1956.69 1826.77,1956.69 1822.83,1960.63 1814.96,1960.63 1811.02,1964.57 1787.4,1964.57 1783.46,1968.5 1763.78,1968.5 1759.84,1972.44 1736.22,1972.44 1732.28,1976.38 1708.66,1976.38 1704.72,1980.32 1681.1,1980.32 1677.17,1984.25 1653.54,1984.25 1649.61,1988.19 1625.98,1988.19 1606.3,2007.87 1492.13,2007.87 ; v13(2724.41,1381.89) 2098.43,2007.87 1492.13,2007.87
  SIG2 w7.09: v14(992.13,2677.17) 996.06,2673.23 996.06,2661.42 1027.56,2629.92 1027.56,2220.47 v14(1039.37,2208.66)
  Bottom Layer w6.3: C806.1@1037.4,2184.06 1039.37,2185.04 1039.37,2157.48 1102.36,2094.49 1102.36,2090.55 1149.61,2043.31 C807.1@1151.57,2044.29 ; R71.1@1961.61,1318.9 1960.63,1318.9 1948.82,1330.71 1937.01,1330.71 1921.59,1347.74 1874.02,1346.46 1870.08,1342.52 1870.08,1314.96 1862.2,1307.09 1862.2,1303.15 1858.27,1299.21 1858.27,1287.4 1854.33,1283.46 1854.33,1267.72 1858.27,1263.78 1858.27,1259.84 1870.08,1248.03 1870.08,1216.54 1872.96,1211.07 1913.39,1212.6 1925.2,1197.44 2110.24,1200.79 2122.05,1212.6 2204.72,1212.6 2259.84,1267.72 2271.65,1267.72 2322.83,1318.9 2322.83,1334.65 2326.77,1338.58 2440.94,1338.58 2444.88,1342.52 2606.3,1342.52 2610.24,1346.46 2716.54,1346.46 2747.09,1377.95 U5.10@2746.06,1379.43
  Bottom Layer w7.09: C804.1@845.47,2555.12 846.46,2555.12 850.39,2551.18 850.39,2547.24 862.2,2535.43 862.2,2523.62 866.14,2519.68 866.14,2515.75 870.08,2515.75 874.02,2511.81 909.45,2511.81 917.32,2503.94 992.13,2503.94 996.06,2507.87 1000,2507.87 1031.5,2539.37 1062.99,2539.37 1066.93,2543.31 1070.87,2543.31 1070.87,2547.24 1078.74,2555.12 1078.74,2578.74 1082.68,2582.68 U8.9@1082.68,2584.15 ; R800.1@977.36,2659.45 976.38,2657.48 992.13,2673.23 v14(992.13,2677.17) ; C806.1@1037.4,2184.06 1039.37,2185.04 v14(1039.37,2208.66) ; v14(1771.65,1704.72) 1779.53,1712.6 1791.34,1712.6 1799.21,1720.47 1800.32,1771.65 U7.5@1801.18,1771.65
  Bottom Layer w8.66: L8.2@1062.99,2257.48 1062.99,2255.91 1082.68,2255.91 v13(1086.61,2251.97) ; U7.5@1801.18,1771.65 1800.32,1771.65 1803.15,1767.72 1803.15,1724.41 1807.09,1720.47 1830.71,1720.47 1834.65,1724.41 1834.65,1732.28 v13(1858.27,1755.91)
  Bottom Layer w9.06: C804.1@845.47,2555.12 846.46,2555.12 830.71,2539.37 803.15,2539.37 799.21,2535.43 795.28,2535.43 795.28,2409.45 799.21,2409.45 803.15,2405.51 854.33,2405.51 858.27,2409.45 862.2,2409.45 913.39,2460.63 913.39,2484.25 933.07,2503.94 996.06,2503.94 1031.5,2539.37 1066.93,2539.37 1074.8,2547.24 1074.8,2551.18 1078.74,2555.12 1078.74,2578.74 1082.68,2582.68 U8.9@1082.68,2584.15
  Bottom Layer w9.84: C804.1@845.47,2555.12 846.46,2555.12 814.96,2555.12 795.28,2535.43 795.28,2409.45 799.21,2409.45 803.15,2405.51 850.39,2405.51 858.27,2397.64 858.27,2385.83 874.02,2370.08 874.02,2350.39 1039.37,2185.04 C806.1@1037.4,2184.06
  Bottom Layer w10.24: v10(1815.94,1641.73) 1801.18,1656.5 U7.5@1801.18,1771.65 1801.18,1730.32 1804.13,1727.36 1804.13,1724.41 1807.09,1721.46 1810.04,1721.46 1812.99,1718.5 ; v10(1895.67,1736.22) 1877.95,1718.5 1812.99,1718.5 ; v10(1898.62,1683.07) 1863.19,1718.5 1812.99,1718.5 ; v10(1898.62,1709.65) 1889.76,1718.5 1812.99,1718.5
  Bottom Layer w12.6: U9.10@1438.48,3001.97 1437.01,3000 U9.11@1437.01,3019.68 ; U9.11@1438.48,3021.65 U9.11@1437.01,3019.68 ; U9.12@1438.48,3041.34 U9.12@1437.01,3043.31 ; U9.13@1466.54,3069.39 1464.57,3070.87 U9.12@1437.01,3043.31 ; U5.13@2678.64,1407.48 2677.17,1405.51 U5.12@2704.72,1377.95 ; U5.12@2706.69,1379.43 U5.12@2704.72,1377.95 ; U5.11@2726.38,1379.43 U5.11@2728.35,1377.95 ; U5.10@2746.06,1379.43 2747.09,1377.95 U5.11@2728.35,1377.95 ; U9.11@1437.01,3019.68 U9.12@1437.01,3043.31 ; U5.12@2704.72,1377.95 U5.11@2728.35,1377.95
  Bottom Layer w14.17: C93.1@826.77,2312.01 826.77,2311.02 838.58,2299.21 925.2,2299.21 C806.1@1039.37,2185.04 ; C806.1@1037.4,2184.06 C806.1@1039.37,2185.04 ; C90.1@1259.84,2439.96 1259.84,2440.94 1255.91,2437.01 1255.91,2433.07 1185.04,2362.2 1185.04,2330.71 C806.1@1039.37,2185.04
  Bottom Layer w14.57: L8.2@1062.99,2257.48 1062.99,2255.91 1062.99,2275.59 v13(1066.93,2279.53) ; v13(1417.32,3035.43) 1421.26,3035.43 1437.01,3019.68 U9.11@1438.48,3021.65
  Bottom Layer w14.96: L8.2@1062.99,2257.48 1062.99,2255.91 1086.61,2232.28 1094.49,2232.28 v13(1098.43,2228.35) ; C4.1@2559.06,1329.72 2559.06,1330.71 2586.61,1358.27 2622.05,1358.27 2625.98,1362.2 2629.92,1362.2 2645.67,1377.95 U5.10@2747.09,1377.95 ; v13(2724.41,1381.89) 2728.35,1377.95 U5.10@2747.09,1377.95 ; U5.10@2746.06,1379.43 U5.10@2747.09,1377.95 ; C1.1@2754.92,1299.21 2755.91,1299.21 2748.03,1307.09 U5.10@2747.09,1377.95
  Bottom Layer w20.47: C808.1@713.58,2472.44 712.6,2472.44 716.54,2468.5 716.54,2421.26 799.21,2338.58 846.46,2338.58 854.33,2330.71 893.7,2330.71 1039.37,2185.04 C806.1@1037.4,2184.06
  Bottom Layer w25.59: L8.2@1062.99,2257.48 1062.99,2255.91 1062.99,2236.22 v13(1066.93,2232.28) ; v13(1145.67,2066.93) 1149.61,2062.99 1149.61,2043.31 C807.1@1151.57,2044.29
  Bottom Layer w43.31: C809.1@653.54,2032.48 653.54,2031.5 586.61,2098.43 582.68,2098.43 574.8,2106.3 574.8,2110.24 570.87,2114.17 570.87,2185.04 586.61,2200.79 598.43,2200.79 688.98,2291.34 692.91,2291.34 696.85,2295.28 704.72,2295.28 708.66,2299.21 748.03,2299.21 751.97,2295.28 759.84,2295.28 763.78,2291.34 767.72,2291.34 775.59,2283.46 850.39,2283.46 854.33,2279.53 858.27,2279.53 925.2,2212.6 976.38,2212.6 980.32,2208.66 988.19,2208.66 1011.81,2185.04 1039.37,2185.04 C806.1@1037.4,2184.06
  Bottom Layer w62.99: C806.1@1037.4,2184.06 1039.37,2185.04 1062.99,2208.66 1062.99,2255.91 L8.2@1062.99,2257.48
VCAP1_LOCAL: C10.1 U1.81 | length 207.2
  Bottom Layer w7.09: C10.1@1270.67,2519.68 1269.68,2518.7 1308.07,2557.09 1308.07,2622.05 1311.02,2625 1311.02,2663.39 1313.98,2663.39 1316.93,2666.34 1352.36,2666.34 U1.81@1351.38,2667.32
VCAP2_LOCAL: C11.1 U1.125 | length 72.7
  Bottom Layer w7.09: U1.125@2135.83,2880.91 2138.78,2911.42 C11.1@2146.65,2952.76
VDDA_FILTERED: C13.1 C14.1 FB1.2 U1.38 U1.39 | length 1492.1
  SIG1 w6.3: v3(1165.35,2001.57) 1170.08,2006.3 1170.08,2250.39 1211.02,2291.34 1486.61,2291.34 v3(1717.52,2082.68)
  Bottom Layer w6.3: v3(1165.35,2001.57) 1204.72,2001.57 1259.84,2056.69 C14.1@1259.84,2056.1 ; U1.39@1525.59,1882.87 1525.98,1883.46 1525.98,1911.81 v3(1717.52,2082.68)
  Bottom Layer w7.09: U1.39@1525.59,1882.87 1526.57,1883.86 1544.29,1883.86 U1.38@1545.28,1882.87
  Bottom Layer w9.84: FB1.2@1185.04,2001.57 FB1.2@1189.47,1988.19 ; C14.1@1259.84,2067.52 1229.33,2099.41 1229.33,2130.91 1237.2,2180.12 C13.1@1259.84,2203.94
VIN_PROTECTED_24V: C800.1 C801.1 C802.1 R804.1 R806.2 U6.17 U6.18 U8.20 U8.21 U8.22 | length 4107.6
  PWR2 w28.35: v10(1080.71,2867.13) 1107.28,2867.13 v13@1130.91,2890.75 ; v10(1080.71,2893.7) 1127.95,2893.7 v13@1130.91,2890.75 ; v10(1083.66,2923.23) 1098.43,2923.23 v13@1130.91,2890.75 ; v13(1129.92,2889.76) v13@1130.91,2890.75 ; v10(1145.67,2805.12) 1145.67,2816.93 1175.2,2846.46 1174.54,2845.14 ; 1152.23,2867.45 1151.57,2867.13 1175.2,2890.75 v10(1175.2,2908.46) ; v10(1163.39,2932.09) 1163.39,2923.23 v13@1130.91,2890.75 ; v10(1293.31,1500) 1378.94,1585.63 1378.94,1641.73 1390.75,1653.54 1390.75,1659.45 v13@1393.7,1662.4 ; v10(1340.55,1550.2) 1378.94,1588.58 1378.94,1647.64 v13@1393.7,1662.4 ; v10(1367.13,1559.06) 1367.13,1635.83 v13@1393.7,1662.4 ; v10(1393.7,1562.01) v13@1393.7,1662.4 ; v13(1393.7,1661.42) v13@1393.7,1662.4
  PWR2 w29.53: v20(1389.76,1629.92) 1393.7,1629.92 v20@1393.7,1628.94 ; v20@1393.7,1595.47 1393.7,1596.46 1395.67,1594.49 v20(1401.57,1594.49)
  PWR2 w118.11: v13(1129.92,2889.76) 1263.78,2755.91 1267.72,2755.91 1291.34,2732.28 1291.34,2728.35 1303.15,2716.54 1303.15,1956.69 1374.02,1885.83 1374.02,1688.98 1377.95,1685.04 1377.95,1677.17 v13(1393.7,1661.42)
  Bottom Layer w7.09: R804.1@1439.96,1649.61 1438.98,1649.61 1405.51,1649.61 v13(1393.7,1661.42) 1395.67,1663.39 1399.61,1663.39 1419.29,1683.07 1468.5,1683.07 1517.72,1732.28 R806.2@1516.73,1732.28
  Bottom Layer w11.81: C800.1@1125,2913.39 1125.98,2913.39 1125.98,2893.7 v13(1129.92,2889.76) ; v10(1293.31,1500) 1296.26,1502.95 1296.26,1508.86 1313.98,1526.57 1313.98,1559.06 1393.7,1638.78 1393.7,1683.07 U6.18@1395.18,1683.07 ; v10(1340.55,1550.2) 1393.7,1603.35 U6.17@1393.7,1703.74 ; v10(1367.13,1559.06) 1393.7,1585.63 U6.17@1393.7,1703.74 ; v20(1389.76,1629.92) 1395.67,1635.83 1395.67,1683.07 U6.18@1395.18,1683.07 ; v10(1393.7,1562.01) U6.17@1393.7,1703.74 ; v13(1393.7,1661.42) 1393.7,1685.04 U6.18@1395.18,1683.07 ; v20(1401.57,1594.49) 1395.67,1600.39 1395.67,1702.76 U6.17@1395.18,1702.76 U6.17@1393.7,1703.74
  Bottom Layer w13.78: U8.22@1161.42,2730.81 1161.42,2732.28 1161.42,2763.78 1181.1,2783.46 C802.1@1181.1,2784.45 ; U6.18@1395.18,1683.07 1393.7,1685.04 1393.7,1700.79 U6.17@1395.18,1702.76
  Bottom Layer w14.96: U8.20@1122.05,2730.81 1122.05,2732.28 U8.21@1141.73,2732.28 ; U8.21@1141.73,2730.81 U8.21@1141.73,2732.28 ; U8.22@1161.42,2730.81 1161.42,2732.28 U8.21@1141.73,2732.28
  Bottom Layer w21.65: v10(1080.71,2867.13) 1089.57,2875.98 1089.57,2878.94 C800.1@1125,2914.37 ; v10(1080.71,2893.7) 1101.38,2914.37 C800.1@1125,2914.37 ; v10(1083.66,2923.23) 1092.52,2914.37 C800.1@1125,2914.37 ; v10(1145.67,2805.12) 1148.62,2802.17 1163.39,2802.17 C802.1@1181.1,2784.45 1181.1,2783.46 1153.54,2811.02 1149.61,2811.02 1133.86,2826.77 1133.86,2905.51 1125.98,2913.39 C800.1@1125,2913.39 C800.1@1125,2914.37 ; v10(1163.39,2932.09) 1142.72,2932.09 C800.1@1125,2914.37 ; v10(1175.2,2908.46) 1169.29,2914.37 C800.1@1125,2914.37
  Bottom Layer w31.5: C800.1@1125,2913.39 1125.98,2913.39 1125.98,3031.5 1145.67,3051.18 C801.1@1144.69,3051.18
VIN_RAW: C6I.1 D1.1 J1.1 Q6.1 Q6.2 Q6.3 Q7.2 R61.1 U6.5 | length 2912.9
  PWR1 w28.35: v10(930.12,1361.22) 965.55,1396.65 v13@965.55,1402.56 ; v10(953.74,1349.41) 953.74,1390.75 ; v10(953.74,1375.98) 953.74,1390.75 ; v13(964.57,1401.57) v13@965.55,1402.56 ; v10(977.36,1325.79) 977.36,1390.75 v13@965.55,1402.56 ; v10(980.32,1352.36) v10@980.32,1387.8 ; v10(980.32,1378.94) v10@980.32,1387.8 ; 953.74,1390.75 v13@965.55,1402.56 ; v13@965.55,1402.56 v10@980.32,1387.8
  PWR1 w118.11: v13(964.57,1401.57) 980.32,1417.32 1090.55,1417.32 1106.3,1433.07 1114.17,1433.07 1255.91,1574.8 1255.91,1578.74 1263.78,1586.61 1263.78,1590.55 1267.72,1594.49 1267.72,1602.36 1271.65,1606.3 1271.65,1700.79 1267.72,1704.72 1267.72,1712.6 1263.78,1716.54 1263.78,1720.47 1255.91,1728.35 1255.91,1732.28 1251.97,1736.22 1248.03,1736.22 1240.16,1744.09 1236.22,1744.09 1232.28,1748.03 1228.35,1748.03 1224.41,1751.97 1181.1,1751.97 J1.1@1161.42,1771.65
  Bottom Layer w9.84: R61.1@1060.04,1901.57 1059.06,1901.57 1094.49,1866.14 1094.49,1838.58 J1.1@1161.42,1771.65
  Bottom Layer w10.24: Q7.2@828.74,1532.97 826.77,1531.5 830.71,1527.56 830.71,1433.07 846.46,1417.32 885.83,1417.32 992.13,1523.62 1011.81,1523.62 Q6.3@1010.24,1524.8
  Bottom Layer w10.63: J1.1@1161.42,1771.65 1161.42,1854.33 1169.29,1862.2 C6I.1@1170.28,1862.2
  Bottom Layer w12.2: v13(964.57,1401.57) 964.57,1452.76 1011.81,1500 Q6.2@1010.24,1498.82
  Bottom Layer w12.6: Q6.1@1010.24,1473.62 1011.81,1472.44 Q6.2@1011.81,1500 ; Q6.2@1010.24,1498.82 Q6.2@1011.81,1500 ; Q6.3@1010.24,1524.8 1011.81,1523.62 Q6.2@1011.81,1500
  Bottom Layer w12.99: J1.1@1161.42,1771.65 1208.66,1771.65 1216.54,1763.78 1244.09,1763.78 U6.5@1242.62,1761.81
  Bottom Layer w14.96: v10(930.12,1361.22) 971.46,1402.56 971.46,1435.04 ; v10(953.74,1349.41) 971.46,1367.13 971.46,1435.04 ; v10(953.74,1375.98) 971.46,1393.7 971.46,1435.04 ; v10(977.36,1325.79) 1009.84,1358.27 Q6.1@1009.84,1473.43 ; v10(980.32,1352.36) 1009.84,1381.89 Q6.1@1009.84,1473.43 ; v10(980.32,1378.94) 1009.84,1408.46 Q6.1@1009.84,1473.43 ; Q6.1@1010.24,1473.62 Q6.1@1009.84,1473.43 ; 971.46,1435.04 Q6.1@1009.84,1473.43
  Bottom Layer w59.06: D1.1@905.51,1864.17 905.51,1862.2 909.45,1866.14 909.45,1881.89 972.44,1944.88 980.32,1944.88 984.25,1948.82 1043.31,1948.82 1047.24,1944.88 1055.12,1944.88 1066.93,1933.07 1066.93,1929.13 1070.87,1925.2 1070.87,1862.2 J1.1@1161.42,1771.65
pads on no net: D3.6 D3.7 D3.9 D3.10 D8.5 D8.6 D8.7 D8.9 D8.10 D_USB.5 D_USB.6 D_USB.7 D_USB.9 D_USB.10 J1.Un1 J6.Un1 J8.5 J8.MP J10.Un1 J10.Un2 J10.Un3 JUSB1.4 JUSB1.7 JUSB1.8 Q6.Un1 Q6.Un2 Q6.Un3 Q6.Un4 Q6.Un5 Q6.Un6 Q6.Un7 Q6.Un8 RAD_U2.11 RAD_U9.3 RAD_U11.3 RAD_U12.3 RAD_U22.3 RAD_U27.4 U1.3 U1.4 U1.5 U1.7 U1.8 U1.9 U1.10 U1.11 U1.12 U1.13 U1.16 U1.17 U1.18 U1.19 U1.20 U1.21 U1.24 U1.25 U1.26 U1.27 U1.28 U1.30 U1.32 U1.33 U1.34 U1.35 U1.41 U1.42 U1.43 U1.44 U1.45 U1.46 U1.47 U1.50 U1.51 U1.52 U1.53 U1.54 U1.55 U1.56 U1.57 U1.58 U1.59 U1.60 U1.63 U1.64 U1.65 U1.66 U1.67 U1.68 U1.69 U1.70 U1.73 U1.74 U1.75 U1.76 U1.77 U1.78 U1.83 U1.84 U1.85 U1.86 U1.87 U1.88 U1.89 U1.98 U1.99 U1.100 U1.101 U1.104 U1.105 U1.106 U1.107 U1.108 U1.109 U1.110 U1.111 U1.112 U1.115 U1.116 U1.117 U1.118 U1.119 U1.122 U1.123 U1.128 U1.129 U1.130 U1.131 U1.132 U1.133 U1.134 U1.138 U1.139 U1.140 U1.141 U1.144 U1.145 U1.146 U1.151 U1.152 U1.153 U1.154 U1.155 U1.156 U1.157 U1.160 U1.162 U1.163 U1.164 U1.165 U1.167 U1.168 U1.169 U1.170 U1.173 U1.174 U1.175 U1.176 U2.2 U2.3 U2.10 U2.11 U4.Un1 U4.Un2 U4.Un3 U4.Un4 U4.Un5 U5.7 U5.8 U5.Un1 U5.Un2 U5.Un3 U5.Un4 U6.12 U6.13 U6.19 U6.20 U6.21 U6.22 U6.23 U6.24 U6.Un1 U6.Un2 U6.Un3 U6.Un4 U7.3 U7.10 U7.Un1 U7.Un2 U7.Un3 U7.Un4 U8.7 U8.11 U8.23 U8.Un1 U8.Un2 U8.Un3 U8.Un4 U8.Un5 U8.Un6 U8.Un7 U8.Un8 U9.7 U9.8 U9.Un1 U9.Un2 U9.Un3 U9.Un4 U_CAN_RAD.Un1 U_CAN_RAD.Un2 U_CAN_RAD.Un3 U_CAN_RAD.Un4 U_CAN_RAD.Un5 U_FRAME.1 U_USB.1 U_USB.2 U_USB.10 U_USB.11 U_USB.14 U_USB.16 U_USB.19 U_USB.20 U_USB.P1 U_USB.P2 U_USB.P3 U_USB.P4 Y1.1

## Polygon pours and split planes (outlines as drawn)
TI_NetC21_2 on Top Layer "TI_NetC21_2" (solid, remove dead copper, pour order 0): 744.76,1750.23 615.47,1750.23 615.47,1558.2 737.3,1558.2 737.3,1699.8 744.76,1699.8
RADAR_12V on Top Layer "RADAR_12V" (solid, remove dead copper, pour order 1): 812.99,1930.08 748.03,1865.12 748.03,1834.07 665.45,1834.07 665.45,1968.5 812.99,1968.5
GND on Top Layer "GND" (solid, remove dead copper, pour order 2): 812.99,1756.35 598.43,1756.35 598.43,1968.5 640.28,1968.5 640.28,1814.86 812.99,1814.86
GND on GND1 "GND1_REFERENCE" (solid, remove dead copper, pour order 3): 2635.41,3327.06 2608.25,3340.45 2547.8,3367.05 2486.25,3390.99 2423.71,3412.22 2360.3,3430.7 2296.15,3446.4 2231.37,3459.29 2166.09,3469.33 2100.44,3476.52 2034.53,3480.84 1968.5,3482.28 1902.47,3480.84 1836.57,3476.52 1770.92,3469.33 1705.64,3459.29 1640.86,3446.4 1576.71,3430.7 1513.3,3412.22 1450.76,3390.99 1389.21,3367.05 1328.75,3340.45 1269.52,3311.24 1211.61,3279.48 1155.15,3245.21 1100.24,3208.52 1046.97,3169.47 995.47,3128.13 945.81,3084.58 898.1,3038.91 852.43,2991.2 808.88,2941.54 767.54,2890.03 728.49,2836.77 691.8,2781.86 657.53,2725.39 625.77,2667.49 596.55,2608.25 569.95,2547.8 546.02,2486.25 524.79,2423.71 506.31,2360.3 490.61,2296.15 477.72,2231.37 467.68,2166.09 460.48,2100.44 456.17,2034.53 454.72,1968.5 456.17,1902.47 460.48,1836.57 467.68,1770.92 477.72,1705.64 490.61,1640.86 506.31,1576.71 524.79,1513.3 546.02,1450.76 569.95,1389.21 596.55,1328.75 625.77,1269.52 657.53,1211.61 691.8,1155.15 728.49,1100.24 767.54,1046.97 808.88,995.47 852.43,945.81 898.1,898.1 945.81,852.43 995.47,808.88 1046.97,767.54 1100.24,728.49 1155.15,691.8 1211.61,657.53 1269.52,625.77 1328.75,596.55 1389.21,569.95 1450.76,546.02 1513.3,524.79 1576.71,506.31 1640.86,490.61 1705.64,477.72 1770.92,467.68 1836.57,460.48 1902.47,456.17 1968.5,454.72 2034.53,456.17 2100.44,460.48 2166.09,467.68 2231.37,477.72 2296.15,490.61 2360.3,506.31 2423.71,524.79 2486.25,546.02 2547.8,569.95 2608.25,596.55 2635.41,609.94
GND on GND2 "GND2_REFERENCE" (solid, remove dead copper, pour order 4): 3474.41,1968.5 3472.98,2034.19 3468.68,2099.75 3461.53,2165.06 3451.53,2230 3438.71,2294.44 3423.1,2358.26 3404.71,2421.34 3383.59,2483.55 3359.78,2544.79 3333.32,2604.93 3304.26,2663.85 3272.66,2721.46 3238.57,2777.63 3202.07,2832.26 3163.22,2885.24 3122.09,2936.48 3078.77,2985.88 3033.34,3033.34 2985.88,3078.77 2936.48,3122.09 2885.24,3163.22 2832.26,3202.07 2777.63,3238.57 2721.46,3272.66 2663.85,3304.26 2604.93,3333.32 2544.79,3359.78 2483.55,3383.59 2421.34,3404.71 2358.26,3423.1 2294.44,3438.71 2230,3451.53 2165.06,3461.53 2099.75,3468.68 2034.19,3472.98 1968.5,3474.41 1902.82,3472.98 1837.26,3468.68 1771.94,3461.53 1707.01,3451.53 1642.57,3438.71 1578.75,3423.1 1515.67,3404.71 1453.45,3383.59 1392.22,3359.78 1332.08,3333.32 1273.15,3304.26 1215.55,3272.66 1159.38,3238.57 1104.75,3202.07 1051.77,3163.22 1000.53,3122.09 951.13,3078.77 903.67,3033.34 858.23,2985.88 814.91,2936.48 773.79,2885.24 734.94,2832.26 698.44,2777.63 664.35,2721.46 632.75,2663.85 603.69,2604.93 577.23,2544.79 553.42,2483.55 532.3,2421.34 513.91,2358.26 498.29,2294.44 485.48,2230 475.48,2165.06 468.33,2099.75 464.03,2034.19 462.6,1968.5 464.03,1902.82 468.33,1837.26 475.48,1771.94 485.48,1707.01 498.29,1642.57 513.91,1578.75 532.3,1515.67 553.42,1453.45 577.23,1392.22 603.69,1332.08 632.75,1273.15 664.35,1215.55 698.44,1159.38 734.94,1104.75 773.79,1051.77 814.91,1000.53 858.23,951.13 903.67,903.67 951.13,858.23 1000.53,814.91 1051.77,773.79 1104.75,734.94 1159.38,698.44 1215.55,664.35 1273.15,632.75 1332.08,603.69 1392.22,577.23 1453.45,553.42 1515.67,532.3 1578.75,513.91 1642.57,498.29 1707.01,485.48 1771.94,475.48 1837.26,468.33 1902.82,464.03 1968.5,462.6 2034.19,464.03 2099.75,468.33 2165.06,475.48 2230,485.48 2294.44,498.29 2358.26,513.91 2421.34,532.3 2483.55,553.42 2544.79,577.23 2604.93,603.69 2663.85,632.75 2721.46,664.35 2777.63,698.44 2832.26,734.94 2885.24,773.79 2936.48,814.91 2985.88,858.23 3033.34,903.67 3078.77,951.13 3122.09,1000.53 3163.22,1051.77 3202.07,1104.75 3238.57,1159.38 3272.66,1215.55 3304.26,1273.15 3333.32,1332.08 3359.78,1392.22 3383.59,1453.45 3404.71,1515.67 3423.1,1578.75 3438.71,1642.57 3451.53,1707.01 3461.53,1771.94 3468.68,1837.26 3472.98,1902.82
GND on Bottom Layer "GND_BOTTOM_RETURN" (solid, remove dead copper, pour order 5): 3474.41,1968.5 3472.98,2034.19 3468.68,2099.75 3461.53,2165.06 3451.53,2230 3438.71,2294.44 3423.1,2358.26 3404.71,2421.34 3383.59,2483.55 3359.78,2544.79 3333.32,2604.93 3304.26,2663.85 3272.66,2721.46 3238.57,2777.63 3202.07,2832.26 3163.22,2885.24 3122.09,2936.48 3078.77,2985.88 3033.34,3033.34 2985.88,3078.77 2936.48,3122.09 2885.24,3163.22 2832.26,3202.07 2777.63,3238.57 2721.46,3272.66 2663.85,3304.26 2604.93,3333.32 2544.79,3359.78 2483.55,3383.59 2421.34,3404.71 2358.26,3423.1 2294.44,3438.71 2230,3451.53 2165.06,3461.53 2099.75,3468.68 2034.19,3472.98 1968.5,3474.41 1902.82,3472.98 1837.26,3468.68 1771.94,3461.53 1707.01,3451.53 1642.57,3438.71 1578.75,3423.1 1515.67,3404.71 1453.45,3383.59 1392.22,3359.78 1332.08,3333.32 1273.15,3304.26 1215.55,3272.66 1159.38,3238.57 1104.75,3202.07 1051.77,3163.22 1000.53,3122.09 951.13,3078.77 903.67,3033.34 858.23,2985.88 814.91,2936.48 773.79,2885.24 734.94,2832.26 698.44,2777.63 664.35,2721.46 632.75,2663.85 603.69,2604.93 577.23,2544.79 553.42,2483.55 532.3,2421.34 513.91,2358.26 498.29,2294.44 485.48,2230 475.48,2165.06 468.33,2099.75 464.03,2034.19 462.6,1968.5 464.03,1902.82 468.33,1837.26 475.48,1771.94 485.48,1707.01 498.29,1642.57 513.91,1578.75 532.3,1515.67 553.42,1453.45 577.23,1392.22 603.69,1332.08 632.75,1273.15 664.35,1215.55 698.44,1159.38 734.94,1104.75 773.79,1051.77 814.91,1000.53 858.23,951.13 903.67,903.67 951.13,858.23 1000.53,814.91 1051.77,773.79 1104.75,734.94 1159.38,698.44 1215.55,664.35 1273.15,632.75 1332.08,603.69 1392.22,577.23 1453.45,553.42 1515.67,532.3 1578.75,513.91 1642.57,498.29 1707.01,485.48 1771.94,475.48 1837.26,468.33 1902.82,464.03 1968.5,462.6 2034.19,464.03 2099.75,468.33 2165.06,475.48 2230,485.48 2294.44,498.29 2358.26,513.91 2421.34,532.3 2483.55,553.42 2544.79,577.23 2604.93,603.69 2663.85,632.75 2721.46,664.35 2777.63,698.44 2832.26,734.94 2885.24,773.79 2936.48,814.91 2985.88,858.23 3033.34,903.67 3078.77,951.13 3122.09,1000.53 3163.22,1051.77 3202.07,1104.75 3238.57,1159.38 3272.66,1215.55 3304.26,1273.15 3333.32,1332.08 3359.78,1392.22 3383.59,1453.45 3404.71,1515.67 3423.1,1578.75 3438.71,1642.57 3451.53,1707.01 3461.53,1771.94 3468.68,1837.26 3472.98,1902.82
GND on Top Layer "GND_COPLANAR_FEED_REFERENCE" (solid, remove dead copper, pour order 6): 2624.02,1830.71 2624.02,1200.79 1318.9,1200.79 1318.9,1830.71
GND on Top Layer "GND_TOP_DIGITAL_RETURN" (solid, remove dead copper, pour order 7): 1141.73,748.03 2066.93,748.03 2066.93,1190.94 1141.73,1190.94
TI_REGOUT_3V3 on PWR2 "REGOUT_3V3_WINDOW_8" (solid, pour order 8): 1479.33,1128.16 1484.49,1125.52 1489.88,1123.39 1495.45,1121.81 1501.16,1120.77 1506.93,1120.31 1512.73,1120.41 1518.48,1121.07 1524.15,1122.3 1529.66,1124.08 1534.98,1126.39 1540.04,1129.21 1544.81,1132.51 1549.22,1136.26 1553.25,1140.43 1556.85,1144.97 1559.99,1149.84 1562.63,1155 1564.75,1160.39 1566.34,1165.97 1567.37,1171.67 1567.84,1177.44 1567.74,1183.24 1567.08,1189 1565.85,1194.66 1564.07,1200.18 1561.76,1205.49 1558.94,1210.56 1555.64,1215.32 1551.89,1219.73 1547.72,1223.76 1543.18,1227.36 1538.31,1230.5 592.48,1775.58 587.32,1778.22 581.93,1780.35 576.36,1781.93 570.65,1782.97 564.88,1783.43 559.08,1783.34 553.33,1782.67 547.66,1781.44 542.15,1779.66 536.83,1777.35 531.77,1774.53 527,1771.23 522.59,1767.48 518.56,1763.31 514.96,1758.77 511.83,1753.9 509.18,1748.74 507.06,1743.35 505.47,1737.77 504.44,1732.07 503.97,1726.3 504.07,1720.5 504.73,1714.74 505.96,1709.08 507.74,1703.56 510.05,1698.25 512.87,1693.18 516.17,1688.42 519.92,1684.01 524.09,1679.98 528.63,1676.38 533.5,1673.24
